VERSION 5.8 ;
BUSBITCHARS "[]" ;
DIVIDERCHAR "/" ;
UNITS
    DATABASE MICRONS 1000 ;
END UNITS

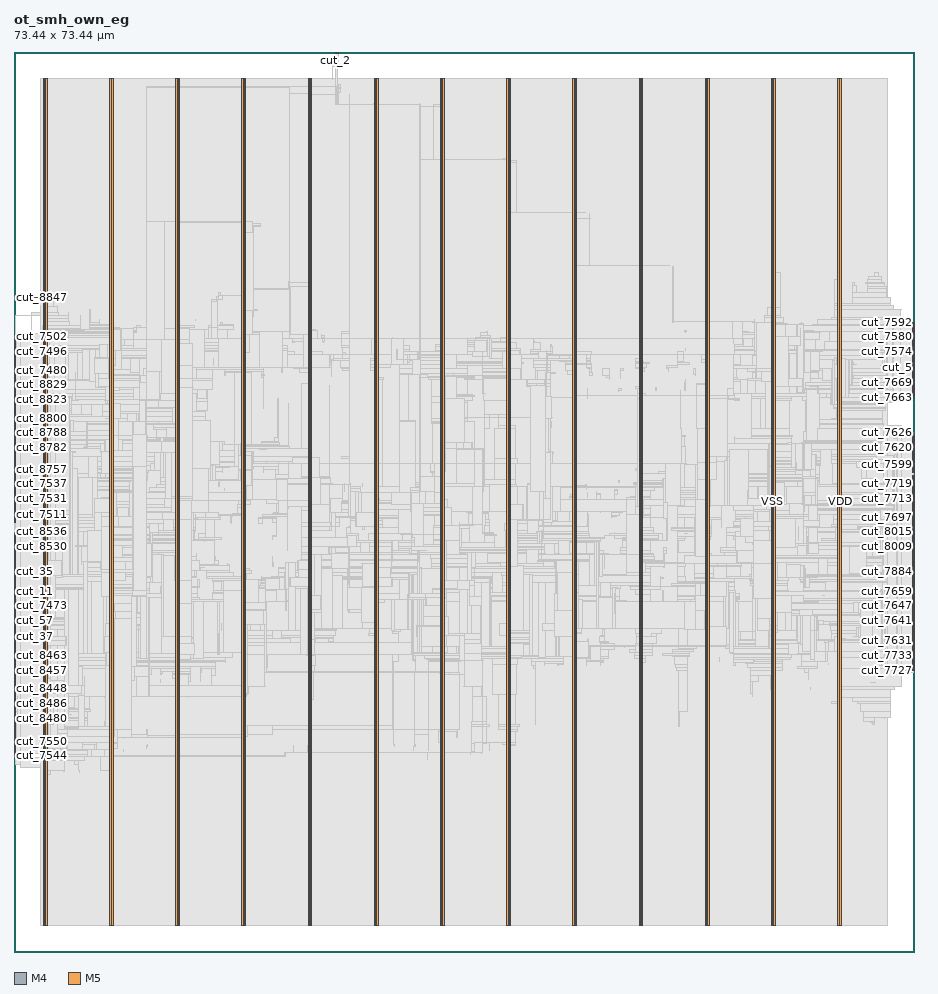
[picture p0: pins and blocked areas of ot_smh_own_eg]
MACRO ot_smh_own_eg
  FOREIGN ot_smh_own_eg 0 0 ;
  CLASS BLOCK ;
  SIZE 73.44 BY 73.44 ;
  PIN cut_10
    DIRECTION INPUT ;
    USE SIGNAL ;
    PORT
      LAYER M4 ;
        RECT  0 28.656 0.084 28.68 ;
    END
  END cut_10
  PIN cut_11
    DIRECTION INPUT ;
    USE SIGNAL ;
    PORT
      LAYER M4 ;
        RECT  0 28.752 0.084 28.776 ;
    END
  END cut_11
  PIN cut_12
    DIRECTION INPUT ;
    USE SIGNAL ;
    PORT
      LAYER M4 ;
        RECT  0 28.848 0.084 28.872 ;
    END
  END cut_12
  PIN cut_13
    DIRECTION INPUT ;
    USE SIGNAL ;
    PORT
      LAYER M4 ;
        RECT  0 28.944 0.084 28.968 ;
    END
  END cut_13
  PIN cut_14
    DIRECTION INPUT ;
    USE SIGNAL ;
    PORT
      LAYER M4 ;
        RECT  0 29.04 0.084 29.064 ;
    END
  END cut_14
  PIN cut_15
    DIRECTION INPUT ;
    USE SIGNAL ;
    PORT
      LAYER M4 ;
        RECT  0 29.136 0.084 29.16 ;
    END
  END cut_15
  PIN cut_16
    DIRECTION INPUT ;
    USE SIGNAL ;
    PORT
      LAYER M4 ;
        RECT  0 29.232 0.084 29.256 ;
    END
  END cut_16
  PIN cut_17
    DIRECTION INPUT ;
    USE SIGNAL ;
    PORT
      LAYER M4 ;
        RECT  0 29.328 0.084 29.352 ;
    END
  END cut_17
  PIN cut_18
    DIRECTION INPUT ;
    USE SIGNAL ;
    PORT
      LAYER M4 ;
        RECT  0 29.424 0.084 29.448 ;
    END
  END cut_18
  PIN cut_19
    DIRECTION INPUT ;
    USE SIGNAL ;
    PORT
      LAYER M4 ;
        RECT  0 29.52 0.084 29.544 ;
    END
  END cut_19
  PIN cut_2
    DIRECTION INPUT ;
    USE SIGNAL ;
    PORT
      LAYER M5 ;
        RECT  26.256 73.356 26.28 73.44 ;
    END
  END cut_2
  PIN cut_20
    DIRECTION INPUT ;
    USE SIGNAL ;
    PORT
      LAYER M4 ;
        RECT  0 29.616 0.084 29.64 ;
    END
  END cut_20
  PIN cut_21
    DIRECTION INPUT ;
    USE SIGNAL ;
    PORT
      LAYER M4 ;
        RECT  0 29.712 0.084 29.736 ;
    END
  END cut_21
  PIN cut_22
    DIRECTION INPUT ;
    USE SIGNAL ;
    PORT
      LAYER M4 ;
        RECT  0 29.808 0.084 29.832 ;
    END
  END cut_22
  PIN cut_23
    DIRECTION INPUT ;
    USE SIGNAL ;
    PORT
      LAYER M4 ;
        RECT  0 29.904 0.084 29.928 ;
    END
  END cut_23
  PIN cut_24
    DIRECTION INPUT ;
    USE SIGNAL ;
    PORT
      LAYER M4 ;
        RECT  0 30 0.084 30.024 ;
    END
  END cut_24
  PIN cut_25
    DIRECTION INPUT ;
    USE SIGNAL ;
    PORT
      LAYER M4 ;
        RECT  0 30.096 0.084 30.12 ;
    END
  END cut_25
  PIN cut_26
    DIRECTION INPUT ;
    USE SIGNAL ;
    PORT
      LAYER M4 ;
        RECT  0 30.192 0.084 30.216 ;
    END
  END cut_26
  PIN cut_27
    DIRECTION INPUT ;
    USE SIGNAL ;
    PORT
      LAYER M4 ;
        RECT  0 30.288 0.084 30.312 ;
    END
  END cut_27
  PIN cut_28
    DIRECTION INPUT ;
    USE SIGNAL ;
    PORT
      LAYER M4 ;
        RECT  0 30.384 0.084 30.408 ;
    END
  END cut_28
  PIN cut_29
    DIRECTION INPUT ;
    USE SIGNAL ;
    PORT
      LAYER M4 ;
        RECT  0 30.48 0.084 30.504 ;
    END
  END cut_29
  PIN cut_3
    DIRECTION INPUT ;
    USE SIGNAL ;
    PORT
      LAYER M5 ;
        RECT  26.352 73.356 26.376 73.44 ;
    END
  END cut_3
  PIN cut_30
    DIRECTION INPUT ;
    USE SIGNAL ;
    PORT
      LAYER M4 ;
        RECT  0 30.576 0.084 30.6 ;
    END
  END cut_30
  PIN cut_31
    DIRECTION INPUT ;
    USE SIGNAL ;
    PORT
      LAYER M4 ;
        RECT  0 30.672 0.084 30.696 ;
    END
  END cut_31
  PIN cut_32
    DIRECTION INPUT ;
    USE SIGNAL ;
    PORT
      LAYER M4 ;
        RECT  0 30.768 0.084 30.792 ;
    END
  END cut_32
  PIN cut_33
    DIRECTION INPUT ;
    USE SIGNAL ;
    PORT
      LAYER M4 ;
        RECT  0 30.864 0.084 30.888 ;
    END
  END cut_33
  PIN cut_34
    DIRECTION INPUT ;
    USE SIGNAL ;
    PORT
      LAYER M4 ;
        RECT  0 30.96 0.084 30.984 ;
    END
  END cut_34
  PIN cut_35
    DIRECTION INPUT ;
    USE SIGNAL ;
    PORT
      LAYER M4 ;
        RECT  0 31.056 0.084 31.08 ;
    END
  END cut_35
  PIN cut_36
    DIRECTION INPUT ;
    USE SIGNAL ;
    PORT
      LAYER M4 ;
        RECT  0 31.152 0.084 31.176 ;
    END
  END cut_36
  PIN cut_37
    DIRECTION INPUT ;
    USE SIGNAL ;
    PORT
      LAYER M4 ;
        RECT  0 25.104 0.084 25.128 ;
    END
  END cut_37
  PIN cut_38
    DIRECTION INPUT ;
    USE SIGNAL ;
    PORT
      LAYER M4 ;
        RECT  0 25.2 0.084 25.224 ;
    END
  END cut_38
  PIN cut_39
    DIRECTION INPUT ;
    USE SIGNAL ;
    PORT
      LAYER M4 ;
        RECT  0 25.296 0.084 25.32 ;
    END
  END cut_39
  PIN cut_4
    DIRECTION INPUT ;
    USE SIGNAL ;
    PORT
      LAYER M4 ;
        RECT  0 28.176 0.084 28.2 ;
    END
  END cut_4
  PIN cut_40
    DIRECTION INPUT ;
    USE SIGNAL ;
    PORT
      LAYER M4 ;
        RECT  0 25.392 0.084 25.416 ;
    END
  END cut_40
  PIN cut_41
    DIRECTION INPUT ;
    USE SIGNAL ;
    PORT
      LAYER M4 ;
        RECT  0 25.488 0.084 25.512 ;
    END
  END cut_41
  PIN cut_42
    DIRECTION INPUT ;
    USE SIGNAL ;
    PORT
      LAYER M4 ;
        RECT  0 25.584 0.084 25.608 ;
    END
  END cut_42
  PIN cut_43
    DIRECTION INPUT ;
    USE SIGNAL ;
    PORT
      LAYER M4 ;
        RECT  0 25.68 0.084 25.704 ;
    END
  END cut_43
  PIN cut_44
    DIRECTION INPUT ;
    USE SIGNAL ;
    PORT
      LAYER M4 ;
        RECT  0 25.776 0.084 25.8 ;
    END
  END cut_44
  PIN cut_45
    DIRECTION INPUT ;
    USE SIGNAL ;
    PORT
      LAYER M4 ;
        RECT  0 25.872 0.084 25.896 ;
    END
  END cut_45
  PIN cut_46
    DIRECTION INPUT ;
    USE SIGNAL ;
    PORT
      LAYER M4 ;
        RECT  0 25.968 0.084 25.992 ;
    END
  END cut_46
  PIN cut_47
    DIRECTION INPUT ;
    USE SIGNAL ;
    PORT
      LAYER M4 ;
        RECT  0 26.064 0.084 26.088 ;
    END
  END cut_47
  PIN cut_48
    DIRECTION INPUT ;
    USE SIGNAL ;
    PORT
      LAYER M4 ;
        RECT  0 26.16 0.084 26.184 ;
    END
  END cut_48
  PIN cut_49
    DIRECTION INPUT ;
    USE SIGNAL ;
    PORT
      LAYER M4 ;
        RECT  0 26.256 0.084 26.28 ;
    END
  END cut_49
  PIN cut_5
    DIRECTION OUTPUT ;
    USE SIGNAL ;
    PORT
      LAYER M4 ;
        RECT  73.356 48.336 73.44 48.36 ;
    END
  END cut_5
  PIN cut_50
    DIRECTION INPUT ;
    USE SIGNAL ;
    PORT
      LAYER M4 ;
        RECT  0 26.352 0.084 26.376 ;
    END
  END cut_50
  PIN cut_51
    DIRECTION INPUT ;
    USE SIGNAL ;
    PORT
      LAYER M4 ;
        RECT  0 26.448 0.084 26.472 ;
    END
  END cut_51
  PIN cut_52
    DIRECTION INPUT ;
    USE SIGNAL ;
    PORT
      LAYER M4 ;
        RECT  0 26.544 0.084 26.568 ;
    END
  END cut_52
  PIN cut_53
    DIRECTION INPUT ;
    USE SIGNAL ;
    PORT
      LAYER M4 ;
        RECT  0 26.64 0.084 26.664 ;
    END
  END cut_53
  PIN cut_54
    DIRECTION INPUT ;
    USE SIGNAL ;
    PORT
      LAYER M4 ;
        RECT  0 26.736 0.084 26.76 ;
    END
  END cut_54
  PIN cut_55
    DIRECTION INPUT ;
    USE SIGNAL ;
    PORT
      LAYER M4 ;
        RECT  0 26.832 0.084 26.856 ;
    END
  END cut_55
  PIN cut_56
    DIRECTION INPUT ;
    USE SIGNAL ;
    PORT
      LAYER M4 ;
        RECT  0 26.928 0.084 26.952 ;
    END
  END cut_56
  PIN cut_57
    DIRECTION INPUT ;
    USE SIGNAL ;
    PORT
      LAYER M4 ;
        RECT  0 27.024 0.084 27.048 ;
    END
  END cut_57
  PIN cut_6
    DIRECTION INPUT ;
    USE SIGNAL ;
    PORT
      LAYER M4 ;
        RECT  0 28.272 0.084 28.296 ;
    END
  END cut_6
  PIN cut_7
    DIRECTION INPUT ;
    USE SIGNAL ;
    PORT
      LAYER M4 ;
        RECT  0 28.368 0.084 28.392 ;
    END
  END cut_7
  PIN cut_7468
    DIRECTION INPUT ;
    USE SIGNAL ;
    PORT
      LAYER M4 ;
        RECT  0 27.12 0.084 27.144 ;
    END
  END cut_7468
  PIN cut_7469
    DIRECTION INPUT ;
    USE SIGNAL ;
    PORT
      LAYER M4 ;
        RECT  0 27.216 0.084 27.24 ;
    END
  END cut_7469
  PIN cut_7470
    DIRECTION INPUT ;
    USE SIGNAL ;
    PORT
      LAYER M4 ;
        RECT  0 27.312 0.084 27.336 ;
    END
  END cut_7470
  PIN cut_7471
    DIRECTION INPUT ;
    USE SIGNAL ;
    PORT
      LAYER M4 ;
        RECT  0 27.408 0.084 27.432 ;
    END
  END cut_7471
  PIN cut_7472
    DIRECTION INPUT ;
    USE SIGNAL ;
    PORT
      LAYER M4 ;
        RECT  0 27.504 0.084 27.528 ;
    END
  END cut_7472
  PIN cut_7473
    DIRECTION INPUT ;
    USE SIGNAL ;
    PORT
      LAYER M4 ;
        RECT  0 27.6 0.084 27.624 ;
    END
  END cut_7473
  PIN cut_7474
    DIRECTION INPUT ;
    USE SIGNAL ;
    PORT
      LAYER M4 ;
        RECT  0 27.696 0.084 27.72 ;
    END
  END cut_7474
  PIN cut_7475
    DIRECTION INPUT ;
    USE SIGNAL ;
    PORT
      LAYER M4 ;
        RECT  0 27.792 0.084 27.816 ;
    END
  END cut_7475
  PIN cut_7476
    DIRECTION INPUT ;
    USE SIGNAL ;
    PORT
      LAYER M4 ;
        RECT  0 27.888 0.084 27.912 ;
    END
  END cut_7476
  PIN cut_7477
    DIRECTION INPUT ;
    USE SIGNAL ;
    PORT
      LAYER M4 ;
        RECT  0 27.984 0.084 28.008 ;
    END
  END cut_7477
  PIN cut_7478
    DIRECTION INPUT ;
    USE SIGNAL ;
    PORT
      LAYER M4 ;
        RECT  0 28.08 0.084 28.104 ;
    END
  END cut_7478
  PIN cut_7479
    DIRECTION INPUT ;
    USE SIGNAL ;
    PORT
      LAYER M4 ;
        RECT  0 47.376 0.084 47.4 ;
    END
  END cut_7479
  PIN cut_7480
    DIRECTION INPUT ;
    USE SIGNAL ;
    PORT
      LAYER M4 ;
        RECT  0 47.472 0.084 47.496 ;
    END
  END cut_7480
  PIN cut_7481
    DIRECTION INPUT ;
    USE SIGNAL ;
    PORT
      LAYER M4 ;
        RECT  0 47.568 0.084 47.592 ;
    END
  END cut_7481
  PIN cut_7482
    DIRECTION INPUT ;
    USE SIGNAL ;
    PORT
      LAYER M4 ;
        RECT  0 47.664 0.084 47.688 ;
    END
  END cut_7482
  PIN cut_7483
    DIRECTION INPUT ;
    USE SIGNAL ;
    PORT
      LAYER M4 ;
        RECT  0 47.76 0.084 47.784 ;
    END
  END cut_7483
  PIN cut_7484
    DIRECTION INPUT ;
    USE SIGNAL ;
    PORT
      LAYER M4 ;
        RECT  0 47.856 0.084 47.88 ;
    END
  END cut_7484
  PIN cut_7485
    DIRECTION INPUT ;
    USE SIGNAL ;
    PORT
      LAYER M4 ;
        RECT  0 47.952 0.084 47.976 ;
    END
  END cut_7485
  PIN cut_7486
    DIRECTION INPUT ;
    USE SIGNAL ;
    PORT
      LAYER M4 ;
        RECT  0 48.048 0.084 48.072 ;
    END
  END cut_7486
  PIN cut_7487
    DIRECTION INPUT ;
    USE SIGNAL ;
    PORT
      LAYER M4 ;
        RECT  0 48.144 0.084 48.168 ;
    END
  END cut_7487
  PIN cut_7488
    DIRECTION INPUT ;
    USE SIGNAL ;
    PORT
      LAYER M4 ;
        RECT  0 48.24 0.084 48.264 ;
    END
  END cut_7488
  PIN cut_7489
    DIRECTION INPUT ;
    USE SIGNAL ;
    PORT
      LAYER M4 ;
        RECT  0 48.336 0.084 48.36 ;
    END
  END cut_7489
  PIN cut_7490
    DIRECTION INPUT ;
    USE SIGNAL ;
    PORT
      LAYER M4 ;
        RECT  0 48.432 0.084 48.456 ;
    END
  END cut_7490
  PIN cut_7491
    DIRECTION INPUT ;
    USE SIGNAL ;
    PORT
      LAYER M4 ;
        RECT  0 48.528 0.084 48.552 ;
    END
  END cut_7491
  PIN cut_7492
    DIRECTION INPUT ;
    USE SIGNAL ;
    PORT
      LAYER M4 ;
        RECT  0 48.624 0.084 48.648 ;
    END
  END cut_7492
  PIN cut_7493
    DIRECTION INPUT ;
    USE SIGNAL ;
    PORT
      LAYER M4 ;
        RECT  0 48.72 0.084 48.744 ;
    END
  END cut_7493
  PIN cut_7494
    DIRECTION INPUT ;
    USE SIGNAL ;
    PORT
      LAYER M4 ;
        RECT  0 48.816 0.084 48.84 ;
    END
  END cut_7494
  PIN cut_7495
    DIRECTION INPUT ;
    USE SIGNAL ;
    PORT
      LAYER M4 ;
        RECT  0 48.912 0.084 48.936 ;
    END
  END cut_7495
  PIN cut_7496
    DIRECTION INPUT ;
    USE SIGNAL ;
    PORT
      LAYER M4 ;
        RECT  0 49.008 0.084 49.032 ;
    END
  END cut_7496
  PIN cut_7497
    DIRECTION INPUT ;
    USE SIGNAL ;
    PORT
      LAYER M4 ;
        RECT  0 49.104 0.084 49.128 ;
    END
  END cut_7497
  PIN cut_7498
    DIRECTION INPUT ;
    USE SIGNAL ;
    PORT
      LAYER M4 ;
        RECT  0 49.2 0.084 49.224 ;
    END
  END cut_7498
  PIN cut_7499
    DIRECTION INPUT ;
    USE SIGNAL ;
    PORT
      LAYER M4 ;
        RECT  0 49.296 0.084 49.32 ;
    END
  END cut_7499
  PIN cut_7500
    DIRECTION INPUT ;
    USE SIGNAL ;
    PORT
      LAYER M4 ;
        RECT  0 49.392 0.084 49.416 ;
    END
  END cut_7500
  PIN cut_7501
    DIRECTION INPUT ;
    USE SIGNAL ;
    PORT
      LAYER M4 ;
        RECT  0 49.488 0.084 49.512 ;
    END
  END cut_7501
  PIN cut_7502
    DIRECTION INPUT ;
    USE SIGNAL ;
    PORT
      LAYER M4 ;
        RECT  0 49.584 0.084 49.608 ;
    END
  END cut_7502
  PIN cut_7503
    DIRECTION INPUT ;
    USE SIGNAL ;
    PORT
      LAYER M4 ;
        RECT  0 49.68 0.084 49.704 ;
    END
  END cut_7503
  PIN cut_7504
    DIRECTION INPUT ;
    USE SIGNAL ;
    PORT
      LAYER M4 ;
        RECT  0 49.776 0.084 49.8 ;
    END
  END cut_7504
  PIN cut_7505
    DIRECTION INPUT ;
    USE SIGNAL ;
    PORT
      LAYER M4 ;
        RECT  0 49.872 0.084 49.896 ;
    END
  END cut_7505
  PIN cut_7506
    DIRECTION INPUT ;
    USE SIGNAL ;
    PORT
      LAYER M4 ;
        RECT  0 49.968 0.084 49.992 ;
    END
  END cut_7506
  PIN cut_7507
    DIRECTION INPUT ;
    USE SIGNAL ;
    PORT
      LAYER M4 ;
        RECT  0 50.064 0.084 50.088 ;
    END
  END cut_7507
  PIN cut_7508
    DIRECTION INPUT ;
    USE SIGNAL ;
    PORT
      LAYER M4 ;
        RECT  0 50.16 0.084 50.184 ;
    END
  END cut_7508
  PIN cut_7509
    DIRECTION INPUT ;
    USE SIGNAL ;
    PORT
      LAYER M4 ;
        RECT  0 50.256 0.084 50.28 ;
    END
  END cut_7509
  PIN cut_7510
    DIRECTION INPUT ;
    USE SIGNAL ;
    PORT
      LAYER M4 ;
        RECT  0 50.352 0.084 50.376 ;
    END
  END cut_7510
  PIN cut_7511
    DIRECTION INPUT ;
    USE SIGNAL ;
    PORT
      LAYER M4 ;
        RECT  0 35.088 0.084 35.112 ;
    END
  END cut_7511
  PIN cut_7512
    DIRECTION INPUT ;
    USE SIGNAL ;
    PORT
      LAYER M4 ;
        RECT  0 35.184 0.084 35.208 ;
    END
  END cut_7512
  PIN cut_7513
    DIRECTION INPUT ;
    USE SIGNAL ;
    PORT
      LAYER M4 ;
        RECT  0 35.28 0.084 35.304 ;
    END
  END cut_7513
  PIN cut_7514
    DIRECTION INPUT ;
    USE SIGNAL ;
    PORT
      LAYER M4 ;
        RECT  0 35.376 0.084 35.4 ;
    END
  END cut_7514
  PIN cut_7515
    DIRECTION INPUT ;
    USE SIGNAL ;
    PORT
      LAYER M4 ;
        RECT  0 35.472 0.084 35.496 ;
    END
  END cut_7515
  PIN cut_7516
    DIRECTION INPUT ;
    USE SIGNAL ;
    PORT
      LAYER M4 ;
        RECT  0 35.568 0.084 35.592 ;
    END
  END cut_7516
  PIN cut_7517
    DIRECTION INPUT ;
    USE SIGNAL ;
    PORT
      LAYER M4 ;
        RECT  0 35.664 0.084 35.688 ;
    END
  END cut_7517
  PIN cut_7518
    DIRECTION INPUT ;
    USE SIGNAL ;
    PORT
      LAYER M4 ;
        RECT  0 35.76 0.084 35.784 ;
    END
  END cut_7518
  PIN cut_7519
    DIRECTION INPUT ;
    USE SIGNAL ;
    PORT
      LAYER M4 ;
        RECT  0 35.856 0.084 35.88 ;
    END
  END cut_7519
  PIN cut_7520
    DIRECTION INPUT ;
    USE SIGNAL ;
    PORT
      LAYER M4 ;
        RECT  0 35.952 0.084 35.976 ;
    END
  END cut_7520
  PIN cut_7521
    DIRECTION INPUT ;
    USE SIGNAL ;
    PORT
      LAYER M4 ;
        RECT  0 36.048 0.084 36.072 ;
    END
  END cut_7521
  PIN cut_7522
    DIRECTION INPUT ;
    USE SIGNAL ;
    PORT
      LAYER M4 ;
        RECT  0 36.144 0.084 36.168 ;
    END
  END cut_7522
  PIN cut_7523
    DIRECTION INPUT ;
    USE SIGNAL ;
    PORT
      LAYER M4 ;
        RECT  0 36.24 0.084 36.264 ;
    END
  END cut_7523
  PIN cut_7524
    DIRECTION INPUT ;
    USE SIGNAL ;
    PORT
      LAYER M4 ;
        RECT  0 36.336 0.084 36.36 ;
    END
  END cut_7524
  PIN cut_7525
    DIRECTION INPUT ;
    USE SIGNAL ;
    PORT
      LAYER M4 ;
        RECT  0 36.432 0.084 36.456 ;
    END
  END cut_7525
  PIN cut_7526
    DIRECTION INPUT ;
    USE SIGNAL ;
    PORT
      LAYER M4 ;
        RECT  0 36.528 0.084 36.552 ;
    END
  END cut_7526
  PIN cut_7527
    DIRECTION INPUT ;
    USE SIGNAL ;
    PORT
      LAYER M4 ;
        RECT  0 36.624 0.084 36.648 ;
    END
  END cut_7527
  PIN cut_7528
    DIRECTION INPUT ;
    USE SIGNAL ;
    PORT
      LAYER M4 ;
        RECT  0 36.72 0.084 36.744 ;
    END
  END cut_7528
  PIN cut_7529
    DIRECTION INPUT ;
    USE SIGNAL ;
    PORT
      LAYER M4 ;
        RECT  0 36.816 0.084 36.84 ;
    END
  END cut_7529
  PIN cut_7530
    DIRECTION INPUT ;
    USE SIGNAL ;
    PORT
      LAYER M4 ;
        RECT  0 36.912 0.084 36.936 ;
    END
  END cut_7530
  PIN cut_7531
    DIRECTION INPUT ;
    USE SIGNAL ;
    PORT
      LAYER M4 ;
        RECT  0 37.008 0.084 37.032 ;
    END
  END cut_7531
  PIN cut_7532
    DIRECTION INPUT ;
    USE SIGNAL ;
    PORT
      LAYER M4 ;
        RECT  0 37.104 0.084 37.128 ;
    END
  END cut_7532
  PIN cut_7533
    DIRECTION INPUT ;
    USE SIGNAL ;
    PORT
      LAYER M4 ;
        RECT  0 37.2 0.084 37.224 ;
    END
  END cut_7533
  PIN cut_7534
    DIRECTION INPUT ;
    USE SIGNAL ;
    PORT
      LAYER M4 ;
        RECT  0 37.296 0.084 37.32 ;
    END
  END cut_7534
  PIN cut_7535
    DIRECTION INPUT ;
    USE SIGNAL ;
    PORT
      LAYER M4 ;
        RECT  0 37.392 0.084 37.416 ;
    END
  END cut_7535
  PIN cut_7536
    DIRECTION INPUT ;
    USE SIGNAL ;
    PORT
      LAYER M4 ;
        RECT  0 37.488 0.084 37.512 ;
    END
  END cut_7536
  PIN cut_7537
    DIRECTION INPUT ;
    USE SIGNAL ;
    PORT
      LAYER M4 ;
        RECT  0 37.584 0.084 37.608 ;
    END
  END cut_7537
  PIN cut_7538
    DIRECTION INPUT ;
    USE SIGNAL ;
    PORT
      LAYER M4 ;
        RECT  0 37.68 0.084 37.704 ;
    END
  END cut_7538
  PIN cut_7539
    DIRECTION INPUT ;
    USE SIGNAL ;
    PORT
      LAYER M4 ;
        RECT  0 37.776 0.084 37.8 ;
    END
  END cut_7539
  PIN cut_7540
    DIRECTION INPUT ;
    USE SIGNAL ;
    PORT
      LAYER M4 ;
        RECT  0 37.872 0.084 37.896 ;
    END
  END cut_7540
  PIN cut_7541
    DIRECTION INPUT ;
    USE SIGNAL ;
    PORT
      LAYER M4 ;
        RECT  0 37.968 0.084 37.992 ;
    END
  END cut_7541
  PIN cut_7542
    DIRECTION INPUT ;
    USE SIGNAL ;
    PORT
      LAYER M4 ;
        RECT  0 38.064 0.084 38.088 ;
    END
  END cut_7542
  PIN cut_7543
    DIRECTION INPUT ;
    USE SIGNAL ;
    PORT
      LAYER M4 ;
        RECT  0 15.888 0.084 15.912 ;
    END
  END cut_7543
  PIN cut_7544
    DIRECTION INPUT ;
    USE SIGNAL ;
    PORT
      LAYER M4 ;
        RECT  0 15.984 0.084 16.008 ;
    END
  END cut_7544
  PIN cut_7545
    DIRECTION INPUT ;
    USE SIGNAL ;
    PORT
      LAYER M4 ;
        RECT  0 16.08 0.084 16.104 ;
    END
  END cut_7545
  PIN cut_7546
    DIRECTION INPUT ;
    USE SIGNAL ;
    PORT
      LAYER M4 ;
        RECT  0 16.176 0.084 16.2 ;
    END
  END cut_7546
  PIN cut_7547
    DIRECTION INPUT ;
    USE SIGNAL ;
    PORT
      LAYER M4 ;
        RECT  0 16.272 0.084 16.296 ;
    END
  END cut_7547
  PIN cut_7548
    DIRECTION INPUT ;
    USE SIGNAL ;
    PORT
      LAYER M4 ;
        RECT  0 16.368 0.084 16.392 ;
    END
  END cut_7548
  PIN cut_7549
    DIRECTION INPUT ;
    USE SIGNAL ;
    PORT
      LAYER M4 ;
        RECT  0 16.464 0.084 16.488 ;
    END
  END cut_7549
  PIN cut_7550
    DIRECTION INPUT ;
    USE SIGNAL ;
    PORT
      LAYER M4 ;
        RECT  0 16.56 0.084 16.584 ;
    END
  END cut_7550
  PIN cut_7551
    DIRECTION INPUT ;
    USE SIGNAL ;
    PORT
      LAYER M4 ;
        RECT  0 16.656 0.084 16.68 ;
    END
  END cut_7551
  PIN cut_7552
    DIRECTION INPUT ;
    USE SIGNAL ;
    PORT
      LAYER M4 ;
        RECT  0 16.752 0.084 16.776 ;
    END
  END cut_7552
  PIN cut_7553
    DIRECTION INPUT ;
    USE SIGNAL ;
    PORT
      LAYER M4 ;
        RECT  0 16.848 0.084 16.872 ;
    END
  END cut_7553
  PIN cut_7554
    DIRECTION INPUT ;
    USE SIGNAL ;
    PORT
      LAYER M4 ;
        RECT  0 16.944 0.084 16.968 ;
    END
  END cut_7554
  PIN cut_7555
    DIRECTION INPUT ;
    USE SIGNAL ;
    PORT
      LAYER M4 ;
        RECT  0 17.04 0.084 17.064 ;
    END
  END cut_7555
  PIN cut_7556
    DIRECTION INPUT ;
    USE SIGNAL ;
    PORT
      LAYER M4 ;
        RECT  0 17.136 0.084 17.16 ;
    END
  END cut_7556
  PIN cut_7557
    DIRECTION INPUT ;
    USE SIGNAL ;
    PORT
      LAYER M4 ;
        RECT  0 17.232 0.084 17.256 ;
    END
  END cut_7557
  PIN cut_7558
    DIRECTION INPUT ;
    USE SIGNAL ;
    PORT
      LAYER M4 ;
        RECT  0 17.328 0.084 17.352 ;
    END
  END cut_7558
  PIN cut_7559
    DIRECTION INPUT ;
    USE SIGNAL ;
    PORT
      LAYER M4 ;
        RECT  0 17.424 0.084 17.448 ;
    END
  END cut_7559
  PIN cut_7560
    DIRECTION INPUT ;
    USE SIGNAL ;
    PORT
      LAYER M4 ;
        RECT  0 17.52 0.084 17.544 ;
    END
  END cut_7560
  PIN cut_7561
    DIRECTION INPUT ;
    USE SIGNAL ;
    PORT
      LAYER M4 ;
        RECT  0 17.616 0.084 17.64 ;
    END
  END cut_7561
  PIN cut_7562
    DIRECTION INPUT ;
    USE SIGNAL ;
    PORT
      LAYER M4 ;
        RECT  0 17.712 0.084 17.736 ;
    END
  END cut_7562
  PIN cut_7563
    DIRECTION INPUT ;
    USE SIGNAL ;
    PORT
      LAYER M4 ;
        RECT  0 17.808 0.084 17.832 ;
    END
  END cut_7563
  PIN cut_7564
    DIRECTION INPUT ;
    USE SIGNAL ;
    PORT
      LAYER M4 ;
        RECT  0 17.904 0.084 17.928 ;
    END
  END cut_7564
  PIN cut_7565
    DIRECTION INPUT ;
    USE SIGNAL ;
    PORT
      LAYER M4 ;
        RECT  0 18 0.084 18.024 ;
    END
  END cut_7565
  PIN cut_7566
    DIRECTION INPUT ;
    USE SIGNAL ;
    PORT
      LAYER M4 ;
        RECT  0 18.096 0.084 18.12 ;
    END
  END cut_7566
  PIN cut_7567
    DIRECTION INPUT ;
    USE SIGNAL ;
    PORT
      LAYER M4 ;
        RECT  0 18.192 0.084 18.216 ;
    END
  END cut_7567
  PIN cut_7568
    DIRECTION OUTPUT ;
    USE SIGNAL ;
    PORT
      LAYER M4 ;
        RECT  73.356 48.432 73.44 48.456 ;
    END
  END cut_7568
  PIN cut_7569
    DIRECTION OUTPUT ;
    USE SIGNAL ;
    PORT
      LAYER M4 ;
        RECT  73.356 48.528 73.44 48.552 ;
    END
  END cut_7569
  PIN cut_7570
    DIRECTION OUTPUT ;
    USE SIGNAL ;
    PORT
      LAYER M4 ;
        RECT  73.356 48.624 73.44 48.648 ;
    END
  END cut_7570
  PIN cut_7571
    DIRECTION OUTPUT ;
    USE SIGNAL ;
    PORT
      LAYER M4 ;
        RECT  73.356 48.72 73.44 48.744 ;
    END
  END cut_7571
  PIN cut_7572
    DIRECTION OUTPUT ;
    USE SIGNAL ;
    PORT
      LAYER M4 ;
        RECT  73.356 48.816 73.44 48.84 ;
    END
  END cut_7572
  PIN cut_7573
    DIRECTION OUTPUT ;
    USE SIGNAL ;
    PORT
      LAYER M4 ;
        RECT  73.356 48.912 73.44 48.936 ;
    END
  END cut_7573
  PIN cut_7574
    DIRECTION OUTPUT ;
    USE SIGNAL ;
    PORT
      LAYER M4 ;
        RECT  73.356 49.008 73.44 49.032 ;
    END
  END cut_7574
  PIN cut_7575
    DIRECTION OUTPUT ;
    USE SIGNAL ;
    PORT
      LAYER M4 ;
        RECT  73.356 49.104 73.44 49.128 ;
    END
  END cut_7575
  PIN cut_7576
    DIRECTION OUTPUT ;
    USE SIGNAL ;
    PORT
      LAYER M4 ;
        RECT  73.356 49.2 73.44 49.224 ;
    END
  END cut_7576
  PIN cut_7577
    DIRECTION OUTPUT ;
    USE SIGNAL ;
    PORT
      LAYER M4 ;
        RECT  73.356 49.296 73.44 49.32 ;
    END
  END cut_7577
  PIN cut_7578
    DIRECTION OUTPUT ;
    USE SIGNAL ;
    PORT
      LAYER M4 ;
        RECT  73.356 49.392 73.44 49.416 ;
    END
  END cut_7578
  PIN cut_7579
    DIRECTION OUTPUT ;
    USE SIGNAL ;
    PORT
      LAYER M4 ;
        RECT  73.356 49.488 73.44 49.512 ;
    END
  END cut_7579
  PIN cut_7580
    DIRECTION OUTPUT ;
    USE SIGNAL ;
    PORT
      LAYER M4 ;
        RECT  73.356 49.584 73.44 49.608 ;
    END
  END cut_7580
  PIN cut_7581
    DIRECTION OUTPUT ;
    USE SIGNAL ;
    PORT
      LAYER M4 ;
        RECT  73.356 49.68 73.44 49.704 ;
    END
  END cut_7581
  PIN cut_7582
    DIRECTION OUTPUT ;
    USE SIGNAL ;
    PORT
      LAYER M4 ;
        RECT  73.356 49.776 73.44 49.8 ;
    END
  END cut_7582
  PIN cut_7583
    DIRECTION OUTPUT ;
    USE SIGNAL ;
    PORT
      LAYER M4 ;
        RECT  73.356 49.872 73.44 49.896 ;
    END
  END cut_7583
  PIN cut_7584
    DIRECTION OUTPUT ;
    USE SIGNAL ;
    PORT
      LAYER M4 ;
        RECT  73.356 49.968 73.44 49.992 ;
    END
  END cut_7584
  PIN cut_7585
    DIRECTION OUTPUT ;
    USE SIGNAL ;
    PORT
      LAYER M4 ;
        RECT  73.356 50.064 73.44 50.088 ;
    END
  END cut_7585
  PIN cut_7586
    DIRECTION OUTPUT ;
    USE SIGNAL ;
    PORT
      LAYER M4 ;
        RECT  73.356 50.16 73.44 50.184 ;
    END
  END cut_7586
  PIN cut_7587
    DIRECTION OUTPUT ;
    USE SIGNAL ;
    PORT
      LAYER M4 ;
        RECT  73.356 50.256 73.44 50.28 ;
    END
  END cut_7587
  PIN cut_7588
    DIRECTION OUTPUT ;
    USE SIGNAL ;
    PORT
      LAYER M4 ;
        RECT  73.356 50.352 73.44 50.376 ;
    END
  END cut_7588
  PIN cut_7589
    DIRECTION OUTPUT ;
    USE SIGNAL ;
    PORT
      LAYER M4 ;
        RECT  73.356 50.448 73.44 50.472 ;
    END
  END cut_7589
  PIN cut_7590
    DIRECTION OUTPUT ;
    USE SIGNAL ;
    PORT
      LAYER M4 ;
        RECT  73.356 50.544 73.44 50.568 ;
    END
  END cut_7590
  PIN cut_7591
    DIRECTION OUTPUT ;
    USE SIGNAL ;
    PORT
      LAYER M4 ;
        RECT  73.356 50.64 73.44 50.664 ;
    END
  END cut_7591
  PIN cut_7592
    DIRECTION OUTPUT ;
    USE SIGNAL ;
    PORT
      LAYER M4 ;
        RECT  73.356 50.736 73.44 50.76 ;
    END
  END cut_7592
  PIN cut_7593
    DIRECTION OUTPUT ;
    USE SIGNAL ;
    PORT
      LAYER M4 ;
        RECT  73.356 50.832 73.44 50.856 ;
    END
  END cut_7593
  PIN cut_7594
    DIRECTION OUTPUT ;
    USE SIGNAL ;
    PORT
      LAYER M4 ;
        RECT  73.356 50.928 73.44 50.952 ;
    END
  END cut_7594
  PIN cut_7595
    DIRECTION OUTPUT ;
    USE SIGNAL ;
    PORT
      LAYER M4 ;
        RECT  73.356 51.024 73.44 51.048 ;
    END
  END cut_7595
  PIN cut_7596
    DIRECTION OUTPUT ;
    USE SIGNAL ;
    PORT
      LAYER M4 ;
        RECT  73.356 51.12 73.44 51.144 ;
    END
  END cut_7596
  PIN cut_7597
    DIRECTION OUTPUT ;
    USE SIGNAL ;
    PORT
      LAYER M4 ;
        RECT  73.356 51.216 73.44 51.24 ;
    END
  END cut_7597
  PIN cut_7598
    DIRECTION OUTPUT ;
    USE SIGNAL ;
    PORT
      LAYER M4 ;
        RECT  73.356 51.312 73.44 51.336 ;
    END
  END cut_7598
  PIN cut_7599
    DIRECTION OUTPUT ;
    USE SIGNAL ;
    PORT
      LAYER M4 ;
        RECT  73.356 39.12 73.44 39.144 ;
    END
  END cut_7599
  PIN cut_7600
    DIRECTION OUTPUT ;
    USE SIGNAL ;
    PORT
      LAYER M4 ;
        RECT  73.356 39.216 73.44 39.24 ;
    END
  END cut_7600
  PIN cut_7601
    DIRECTION OUTPUT ;
    USE SIGNAL ;
    PORT
      LAYER M4 ;
        RECT  73.356 39.312 73.44 39.336 ;
    END
  END cut_7601
  PIN cut_7602
    DIRECTION OUTPUT ;
    USE SIGNAL ;
    PORT
      LAYER M4 ;
        RECT  73.356 39.408 73.44 39.432 ;
    END
  END cut_7602
  PIN cut_7603
    DIRECTION OUTPUT ;
    USE SIGNAL ;
    PORT
      LAYER M4 ;
        RECT  73.356 39.504 73.44 39.528 ;
    END
  END cut_7603
  PIN cut_7604
    DIRECTION OUTPUT ;
    USE SIGNAL ;
    PORT
      LAYER M4 ;
        RECT  73.356 39.6 73.44 39.624 ;
    END
  END cut_7604
  PIN cut_7605
    DIRECTION OUTPUT ;
    USE SIGNAL ;
    PORT
      LAYER M4 ;
        RECT  73.356 39.696 73.44 39.72 ;
    END
  END cut_7605
  PIN cut_7606
    DIRECTION OUTPUT ;
    USE SIGNAL ;
    PORT
      LAYER M4 ;
        RECT  73.356 39.792 73.44 39.816 ;
    END
  END cut_7606
  PIN cut_7607
    DIRECTION OUTPUT ;
    USE SIGNAL ;
    PORT
      LAYER M4 ;
        RECT  73.356 39.888 73.44 39.912 ;
    END
  END cut_7607
  PIN cut_7608
    DIRECTION OUTPUT ;
    USE SIGNAL ;
    PORT
      LAYER M4 ;
        RECT  73.356 39.984 73.44 40.008 ;
    END
  END cut_7608
  PIN cut_7609
    DIRECTION OUTPUT ;
    USE SIGNAL ;
    PORT
      LAYER M4 ;
        RECT  73.356 40.08 73.44 40.104 ;
    END
  END cut_7609
  PIN cut_7610
    DIRECTION OUTPUT ;
    USE SIGNAL ;
    PORT
      LAYER M4 ;
        RECT  73.356 40.176 73.44 40.2 ;
    END
  END cut_7610
  PIN cut_7611
    DIRECTION OUTPUT ;
    USE SIGNAL ;
    PORT
      LAYER M4 ;
        RECT  73.356 40.272 73.44 40.296 ;
    END
  END cut_7611
  PIN cut_7612
    DIRECTION OUTPUT ;
    USE SIGNAL ;
    PORT
      LAYER M4 ;
        RECT  73.356 40.368 73.44 40.392 ;
    END
  END cut_7612
  PIN cut_7613
    DIRECTION OUTPUT ;
    USE SIGNAL ;
    PORT
      LAYER M4 ;
        RECT  73.356 40.464 73.44 40.488 ;
    END
  END cut_7613
  PIN cut_7614
    DIRECTION OUTPUT ;
    USE SIGNAL ;
    PORT
      LAYER M4 ;
        RECT  73.356 40.56 73.44 40.584 ;
    END
  END cut_7614
  PIN cut_7615
    DIRECTION OUTPUT ;
    USE SIGNAL ;
    PORT
      LAYER M4 ;
        RECT  73.356 40.656 73.44 40.68 ;
    END
  END cut_7615
  PIN cut_7616
    DIRECTION OUTPUT ;
    USE SIGNAL ;
    PORT
      LAYER M4 ;
        RECT  73.356 40.752 73.44 40.776 ;
    END
  END cut_7616
  PIN cut_7617
    DIRECTION OUTPUT ;
    USE SIGNAL ;
    PORT
      LAYER M4 ;
        RECT  73.356 40.848 73.44 40.872 ;
    END
  END cut_7617
  PIN cut_7618
    DIRECTION OUTPUT ;
    USE SIGNAL ;
    PORT
      LAYER M4 ;
        RECT  73.356 40.944 73.44 40.968 ;
    END
  END cut_7618
  PIN cut_7619
    DIRECTION OUTPUT ;
    USE SIGNAL ;
    PORT
      LAYER M4 ;
        RECT  73.356 41.04 73.44 41.064 ;
    END
  END cut_7619
  PIN cut_7620
    DIRECTION OUTPUT ;
    USE SIGNAL ;
    PORT
      LAYER M4 ;
        RECT  73.356 41.136 73.44 41.16 ;
    END
  END cut_7620
  PIN cut_7621
    DIRECTION OUTPUT ;
    USE SIGNAL ;
    PORT
      LAYER M4 ;
        RECT  73.356 41.232 73.44 41.256 ;
    END
  END cut_7621
  PIN cut_7622
    DIRECTION OUTPUT ;
    USE SIGNAL ;
    PORT
      LAYER M4 ;
        RECT  73.356 41.328 73.44 41.352 ;
    END
  END cut_7622
  PIN cut_7623
    DIRECTION OUTPUT ;
    USE SIGNAL ;
    PORT
      LAYER M4 ;
        RECT  73.356 41.424 73.44 41.448 ;
    END
  END cut_7623
  PIN cut_7624
    DIRECTION OUTPUT ;
    USE SIGNAL ;
    PORT
      LAYER M4 ;
        RECT  73.356 41.52 73.44 41.544 ;
    END
  END cut_7624
  PIN cut_7625
    DIRECTION OUTPUT ;
    USE SIGNAL ;
    PORT
      LAYER M4 ;
        RECT  73.356 41.616 73.44 41.64 ;
    END
  END cut_7625
  PIN cut_7626
    DIRECTION OUTPUT ;
    USE SIGNAL ;
    PORT
      LAYER M4 ;
        RECT  73.356 41.712 73.44 41.736 ;
    END
  END cut_7626
  PIN cut_7627
    DIRECTION OUTPUT ;
    USE SIGNAL ;
    PORT
      LAYER M4 ;
        RECT  73.356 41.808 73.44 41.832 ;
    END
  END cut_7627
  PIN cut_7628
    DIRECTION OUTPUT ;
    USE SIGNAL ;
    PORT
      LAYER M4 ;
        RECT  73.356 41.904 73.44 41.928 ;
    END
  END cut_7628
  PIN cut_7629
    DIRECTION OUTPUT ;
    USE SIGNAL ;
    PORT
      LAYER M4 ;
        RECT  73.356 42 73.44 42.024 ;
    END
  END cut_7629
  PIN cut_7630
    DIRECTION OUTPUT ;
    USE SIGNAL ;
    PORT
      LAYER M4 ;
        RECT  73.356 42.096 73.44 42.12 ;
    END
  END cut_7630
  PIN cut_7631
    DIRECTION OUTPUT ;
    USE SIGNAL ;
    PORT
      LAYER M4 ;
        RECT  73.356 26.064 73.44 26.088 ;
    END
  END cut_7631
  PIN cut_7632
    DIRECTION OUTPUT ;
    USE SIGNAL ;
    PORT
      LAYER M4 ;
        RECT  73.356 26.16 73.44 26.184 ;
    END
  END cut_7632
  PIN cut_7633
    DIRECTION OUTPUT ;
    USE SIGNAL ;
    PORT
      LAYER M4 ;
        RECT  73.356 26.256 73.44 26.28 ;
    END
  END cut_7633
  PIN cut_7634
    DIRECTION OUTPUT ;
    USE SIGNAL ;
    PORT
      LAYER M4 ;
        RECT  73.356 26.352 73.44 26.376 ;
    END
  END cut_7634
  PIN cut_7635
    DIRECTION OUTPUT ;
    USE SIGNAL ;
    PORT
      LAYER M4 ;
        RECT  73.356 26.448 73.44 26.472 ;
    END
  END cut_7635
  PIN cut_7636
    DIRECTION OUTPUT ;
    USE SIGNAL ;
    PORT
      LAYER M4 ;
        RECT  73.356 26.544 73.44 26.568 ;
    END
  END cut_7636
  PIN cut_7637
    DIRECTION OUTPUT ;
    USE SIGNAL ;
    PORT
      LAYER M4 ;
        RECT  73.356 26.64 73.44 26.664 ;
    END
  END cut_7637
  PIN cut_7638
    DIRECTION OUTPUT ;
    USE SIGNAL ;
    PORT
      LAYER M4 ;
        RECT  73.356 26.736 73.44 26.76 ;
    END
  END cut_7638
  PIN cut_7639
    DIRECTION OUTPUT ;
    USE SIGNAL ;
    PORT
      LAYER M4 ;
        RECT  73.356 26.832 73.44 26.856 ;
    END
  END cut_7639
  PIN cut_7640
    DIRECTION OUTPUT ;
    USE SIGNAL ;
    PORT
      LAYER M4 ;
        RECT  73.356 26.928 73.44 26.952 ;
    END
  END cut_7640
  PIN cut_7641
    DIRECTION OUTPUT ;
    USE SIGNAL ;
    PORT
      LAYER M4 ;
        RECT  73.356 27.024 73.44 27.048 ;
    END
  END cut_7641
  PIN cut_7642
    DIRECTION OUTPUT ;
    USE SIGNAL ;
    PORT
      LAYER M4 ;
        RECT  73.356 27.12 73.44 27.144 ;
    END
  END cut_7642
  PIN cut_7643
    DIRECTION OUTPUT ;
    USE SIGNAL ;
    PORT
      LAYER M4 ;
        RECT  73.356 27.216 73.44 27.24 ;
    END
  END cut_7643
  PIN cut_7644
    DIRECTION OUTPUT ;
    USE SIGNAL ;
    PORT
      LAYER M4 ;
        RECT  73.356 27.312 73.44 27.336 ;
    END
  END cut_7644
  PIN cut_7645
    DIRECTION OUTPUT ;
    USE SIGNAL ;
    PORT
      LAYER M4 ;
        RECT  73.356 27.408 73.44 27.432 ;
    END
  END cut_7645
  PIN cut_7646
    DIRECTION OUTPUT ;
    USE SIGNAL ;
    PORT
      LAYER M4 ;
        RECT  73.356 27.504 73.44 27.528 ;
    END
  END cut_7646
  PIN cut_7647
    DIRECTION OUTPUT ;
    USE SIGNAL ;
    PORT
      LAYER M4 ;
        RECT  73.356 27.6 73.44 27.624 ;
    END
  END cut_7647
  PIN cut_7648
    DIRECTION OUTPUT ;
    USE SIGNAL ;
    PORT
      LAYER M4 ;
        RECT  73.356 27.696 73.44 27.72 ;
    END
  END cut_7648
  PIN cut_7649
    DIRECTION OUTPUT ;
    USE SIGNAL ;
    PORT
      LAYER M4 ;
        RECT  73.356 27.792 73.44 27.816 ;
    END
  END cut_7649
  PIN cut_7650
    DIRECTION OUTPUT ;
    USE SIGNAL ;
    PORT
      LAYER M4 ;
        RECT  73.356 27.888 73.44 27.912 ;
    END
  END cut_7650
  PIN cut_7651
    DIRECTION OUTPUT ;
    USE SIGNAL ;
    PORT
      LAYER M4 ;
        RECT  73.356 27.984 73.44 28.008 ;
    END
  END cut_7651
  PIN cut_7652
    DIRECTION OUTPUT ;
    USE SIGNAL ;
    PORT
      LAYER M4 ;
        RECT  73.356 28.08 73.44 28.104 ;
    END
  END cut_7652
  PIN cut_7653
    DIRECTION OUTPUT ;
    USE SIGNAL ;
    PORT
      LAYER M4 ;
        RECT  73.356 28.176 73.44 28.2 ;
    END
  END cut_7653
  PIN cut_7654
    DIRECTION OUTPUT ;
    USE SIGNAL ;
    PORT
      LAYER M4 ;
        RECT  73.356 28.272 73.44 28.296 ;
    END
  END cut_7654
  PIN cut_7655
    DIRECTION OUTPUT ;
    USE SIGNAL ;
    PORT
      LAYER M4 ;
        RECT  73.356 28.368 73.44 28.392 ;
    END
  END cut_7655
  PIN cut_7656
    DIRECTION OUTPUT ;
    USE SIGNAL ;
    PORT
      LAYER M4 ;
        RECT  73.356 28.464 73.44 28.488 ;
    END
  END cut_7656
  PIN cut_7657
    DIRECTION OUTPUT ;
    USE SIGNAL ;
    PORT
      LAYER M4 ;
        RECT  73.356 28.56 73.44 28.584 ;
    END
  END cut_7657
  PIN cut_7658
    DIRECTION OUTPUT ;
    USE SIGNAL ;
    PORT
      LAYER M4 ;
        RECT  73.356 28.656 73.44 28.68 ;
    END
  END cut_7658
  PIN cut_7659
    DIRECTION OUTPUT ;
    USE SIGNAL ;
    PORT
      LAYER M4 ;
        RECT  73.356 28.752 73.44 28.776 ;
    END
  END cut_7659
  PIN cut_7660
    DIRECTION OUTPUT ;
    USE SIGNAL ;
    PORT
      LAYER M4 ;
        RECT  73.356 28.848 73.44 28.872 ;
    END
  END cut_7660
  PIN cut_7661
    DIRECTION OUTPUT ;
    USE SIGNAL ;
    PORT
      LAYER M4 ;
        RECT  73.356 28.944 73.44 28.968 ;
    END
  END cut_7661
  PIN cut_7662
    DIRECTION OUTPUT ;
    USE SIGNAL ;
    PORT
      LAYER M4 ;
        RECT  73.356 29.04 73.44 29.064 ;
    END
  END cut_7662
  PIN cut_7663
    DIRECTION OUTPUT ;
    USE SIGNAL ;
    PORT
      LAYER M4 ;
        RECT  73.356 45.264 73.44 45.288 ;
    END
  END cut_7663
  PIN cut_7664
    DIRECTION OUTPUT ;
    USE SIGNAL ;
    PORT
      LAYER M4 ;
        RECT  73.356 45.36 73.44 45.384 ;
    END
  END cut_7664
  PIN cut_7665
    DIRECTION OUTPUT ;
    USE SIGNAL ;
    PORT
      LAYER M4 ;
        RECT  73.356 45.456 73.44 45.48 ;
    END
  END cut_7665
  PIN cut_7666
    DIRECTION OUTPUT ;
    USE SIGNAL ;
    PORT
      LAYER M4 ;
        RECT  73.356 45.552 73.44 45.576 ;
    END
  END cut_7666
  PIN cut_7667
    DIRECTION OUTPUT ;
    USE SIGNAL ;
    PORT
      LAYER M4 ;
        RECT  73.356 45.648 73.44 45.672 ;
    END
  END cut_7667
  PIN cut_7668
    DIRECTION OUTPUT ;
    USE SIGNAL ;
    PORT
      LAYER M4 ;
        RECT  73.356 45.744 73.44 45.768 ;
    END
  END cut_7668
  PIN cut_7669
    DIRECTION OUTPUT ;
    USE SIGNAL ;
    PORT
      LAYER M4 ;
        RECT  73.356 45.84 73.44 45.864 ;
    END
  END cut_7669
  PIN cut_7670
    DIRECTION OUTPUT ;
    USE SIGNAL ;
    PORT
      LAYER M4 ;
        RECT  73.356 45.936 73.44 45.96 ;
    END
  END cut_7670
  PIN cut_7671
    DIRECTION OUTPUT ;
    USE SIGNAL ;
    PORT
      LAYER M4 ;
        RECT  73.356 46.032 73.44 46.056 ;
    END
  END cut_7671
  PIN cut_7672
    DIRECTION OUTPUT ;
    USE SIGNAL ;
    PORT
      LAYER M4 ;
        RECT  73.356 46.128 73.44 46.152 ;
    END
  END cut_7672
  PIN cut_7673
    DIRECTION OUTPUT ;
    USE SIGNAL ;
    PORT
      LAYER M4 ;
        RECT  73.356 46.224 73.44 46.248 ;
    END
  END cut_7673
  PIN cut_7674
    DIRECTION OUTPUT ;
    USE SIGNAL ;
    PORT
      LAYER M4 ;
        RECT  73.356 46.32 73.44 46.344 ;
    END
  END cut_7674
  PIN cut_7675
    DIRECTION OUTPUT ;
    USE SIGNAL ;
    PORT
      LAYER M4 ;
        RECT  73.356 46.416 73.44 46.44 ;
    END
  END cut_7675
  PIN cut_7676
    DIRECTION OUTPUT ;
    USE SIGNAL ;
    PORT
      LAYER M4 ;
        RECT  73.356 46.512 73.44 46.536 ;
    END
  END cut_7676
  PIN cut_7677
    DIRECTION OUTPUT ;
    USE SIGNAL ;
    PORT
      LAYER M4 ;
        RECT  73.356 46.608 73.44 46.632 ;
    END
  END cut_7677
  PIN cut_7678
    DIRECTION OUTPUT ;
    USE SIGNAL ;
    PORT
      LAYER M4 ;
        RECT  73.356 46.704 73.44 46.728 ;
    END
  END cut_7678
  PIN cut_7679
    DIRECTION OUTPUT ;
    USE SIGNAL ;
    PORT
      LAYER M4 ;
        RECT  73.356 46.8 73.44 46.824 ;
    END
  END cut_7679
  PIN cut_7680
    DIRECTION OUTPUT ;
    USE SIGNAL ;
    PORT
      LAYER M4 ;
        RECT  73.356 46.896 73.44 46.92 ;
    END
  END cut_7680
  PIN cut_7681
    DIRECTION OUTPUT ;
    USE SIGNAL ;
    PORT
      LAYER M4 ;
        RECT  73.356 46.992 73.44 47.016 ;
    END
  END cut_7681
  PIN cut_7682
    DIRECTION OUTPUT ;
    USE SIGNAL ;
    PORT
      LAYER M4 ;
        RECT  73.356 47.088 73.44 47.112 ;
    END
  END cut_7682
  PIN cut_7683
    DIRECTION OUTPUT ;
    USE SIGNAL ;
    PORT
      LAYER M4 ;
        RECT  73.356 47.184 73.44 47.208 ;
    END
  END cut_7683
  PIN cut_7684
    DIRECTION OUTPUT ;
    USE SIGNAL ;
    PORT
      LAYER M4 ;
        RECT  73.356 47.28 73.44 47.304 ;
    END
  END cut_7684
  PIN cut_7685
    DIRECTION OUTPUT ;
    USE SIGNAL ;
    PORT
      LAYER M4 ;
        RECT  73.356 47.376 73.44 47.4 ;
    END
  END cut_7685
  PIN cut_7686
    DIRECTION OUTPUT ;
    USE SIGNAL ;
    PORT
      LAYER M4 ;
        RECT  73.356 47.472 73.44 47.496 ;
    END
  END cut_7686
  PIN cut_7687
    DIRECTION OUTPUT ;
    USE SIGNAL ;
    PORT
      LAYER M4 ;
        RECT  73.356 47.568 73.44 47.592 ;
    END
  END cut_7687
  PIN cut_7688
    DIRECTION OUTPUT ;
    USE SIGNAL ;
    PORT
      LAYER M4 ;
        RECT  73.356 47.664 73.44 47.688 ;
    END
  END cut_7688
  PIN cut_7689
    DIRECTION OUTPUT ;
    USE SIGNAL ;
    PORT
      LAYER M4 ;
        RECT  73.356 47.76 73.44 47.784 ;
    END
  END cut_7689
  PIN cut_7690
    DIRECTION OUTPUT ;
    USE SIGNAL ;
    PORT
      LAYER M4 ;
        RECT  73.356 47.856 73.44 47.88 ;
    END
  END cut_7690
  PIN cut_7691
    DIRECTION OUTPUT ;
    USE SIGNAL ;
    PORT
      LAYER M4 ;
        RECT  73.356 47.952 73.44 47.976 ;
    END
  END cut_7691
  PIN cut_7692
    DIRECTION OUTPUT ;
    USE SIGNAL ;
    PORT
      LAYER M4 ;
        RECT  73.356 48.048 73.44 48.072 ;
    END
  END cut_7692
  PIN cut_7693
    DIRECTION OUTPUT ;
    USE SIGNAL ;
    PORT
      LAYER M4 ;
        RECT  73.356 48.144 73.44 48.168 ;
    END
  END cut_7693
  PIN cut_7694
    DIRECTION OUTPUT ;
    USE SIGNAL ;
    PORT
      LAYER M4 ;
        RECT  73.356 48.24 73.44 48.264 ;
    END
  END cut_7694
  PIN cut_7695
    DIRECTION OUTPUT ;
    USE SIGNAL ;
    PORT
      LAYER M4 ;
        RECT  73.356 35.28 73.44 35.304 ;
    END
  END cut_7695
  PIN cut_7696
    DIRECTION OUTPUT ;
    USE SIGNAL ;
    PORT
      LAYER M4 ;
        RECT  73.356 35.376 73.44 35.4 ;
    END
  END cut_7696
  PIN cut_7697
    DIRECTION OUTPUT ;
    USE SIGNAL ;
    PORT
      LAYER M4 ;
        RECT  73.356 35.472 73.44 35.496 ;
    END
  END cut_7697
  PIN cut_7698
    DIRECTION OUTPUT ;
    USE SIGNAL ;
    PORT
      LAYER M4 ;
        RECT  73.356 35.568 73.44 35.592 ;
    END
  END cut_7698
  PIN cut_7699
    DIRECTION OUTPUT ;
    USE SIGNAL ;
    PORT
      LAYER M4 ;
        RECT  73.356 35.664 73.44 35.688 ;
    END
  END cut_7699
  PIN cut_7700
    DIRECTION OUTPUT ;
    USE SIGNAL ;
    PORT
      LAYER M4 ;
        RECT  73.356 35.76 73.44 35.784 ;
    END
  END cut_7700
  PIN cut_7701
    DIRECTION OUTPUT ;
    USE SIGNAL ;
    PORT
      LAYER M4 ;
        RECT  73.356 35.856 73.44 35.88 ;
    END
  END cut_7701
  PIN cut_7702
    DIRECTION OUTPUT ;
    USE SIGNAL ;
    PORT
      LAYER M4 ;
        RECT  73.356 35.952 73.44 35.976 ;
    END
  END cut_7702
  PIN cut_7703
    DIRECTION OUTPUT ;
    USE SIGNAL ;
    PORT
      LAYER M4 ;
        RECT  73.356 36.048 73.44 36.072 ;
    END
  END cut_7703
  PIN cut_7704
    DIRECTION OUTPUT ;
    USE SIGNAL ;
    PORT
      LAYER M4 ;
        RECT  73.356 36.144 73.44 36.168 ;
    END
  END cut_7704
  PIN cut_7705
    DIRECTION OUTPUT ;
    USE SIGNAL ;
    PORT
      LAYER M4 ;
        RECT  73.356 36.24 73.44 36.264 ;
    END
  END cut_7705
  PIN cut_7706
    DIRECTION OUTPUT ;
    USE SIGNAL ;
    PORT
      LAYER M4 ;
        RECT  73.356 36.336 73.44 36.36 ;
    END
  END cut_7706
  PIN cut_7707
    DIRECTION OUTPUT ;
    USE SIGNAL ;
    PORT
      LAYER M4 ;
        RECT  73.356 36.432 73.44 36.456 ;
    END
  END cut_7707
  PIN cut_7708
    DIRECTION OUTPUT ;
    USE SIGNAL ;
    PORT
      LAYER M4 ;
        RECT  73.356 36.528 73.44 36.552 ;
    END
  END cut_7708
  PIN cut_7709
    DIRECTION OUTPUT ;
    USE SIGNAL ;
    PORT
      LAYER M4 ;
        RECT  73.356 36.624 73.44 36.648 ;
    END
  END cut_7709
  PIN cut_7710
    DIRECTION OUTPUT ;
    USE SIGNAL ;
    PORT
      LAYER M4 ;
        RECT  73.356 36.72 73.44 36.744 ;
    END
  END cut_7710
  PIN cut_7711
    DIRECTION OUTPUT ;
    USE SIGNAL ;
    PORT
      LAYER M4 ;
        RECT  73.356 36.816 73.44 36.84 ;
    END
  END cut_7711
  PIN cut_7712
    DIRECTION OUTPUT ;
    USE SIGNAL ;
    PORT
      LAYER M4 ;
        RECT  73.356 36.912 73.44 36.936 ;
    END
  END cut_7712
  PIN cut_7713
    DIRECTION OUTPUT ;
    USE SIGNAL ;
    PORT
      LAYER M4 ;
        RECT  73.356 37.008 73.44 37.032 ;
    END
  END cut_7713
  PIN cut_7714
    DIRECTION OUTPUT ;
    USE SIGNAL ;
    PORT
      LAYER M4 ;
        RECT  73.356 37.104 73.44 37.128 ;
    END
  END cut_7714
  PIN cut_7715
    DIRECTION OUTPUT ;
    USE SIGNAL ;
    PORT
      LAYER M4 ;
        RECT  73.356 37.2 73.44 37.224 ;
    END
  END cut_7715
  PIN cut_7716
    DIRECTION OUTPUT ;
    USE SIGNAL ;
    PORT
      LAYER M4 ;
        RECT  73.356 37.296 73.44 37.32 ;
    END
  END cut_7716
  PIN cut_7717
    DIRECTION OUTPUT ;
    USE SIGNAL ;
    PORT
      LAYER M4 ;
        RECT  73.356 37.392 73.44 37.416 ;
    END
  END cut_7717
  PIN cut_7718
    DIRECTION OUTPUT ;
    USE SIGNAL ;
    PORT
      LAYER M4 ;
        RECT  73.356 37.488 73.44 37.512 ;
    END
  END cut_7718
  PIN cut_7719
    DIRECTION OUTPUT ;
    USE SIGNAL ;
    PORT
      LAYER M4 ;
        RECT  73.356 37.584 73.44 37.608 ;
    END
  END cut_7719
  PIN cut_7720
    DIRECTION OUTPUT ;
    USE SIGNAL ;
    PORT
      LAYER M4 ;
        RECT  73.356 37.68 73.44 37.704 ;
    END
  END cut_7720
  PIN cut_7721
    DIRECTION OUTPUT ;
    USE SIGNAL ;
    PORT
      LAYER M4 ;
        RECT  73.356 37.776 73.44 37.8 ;
    END
  END cut_7721
  PIN cut_7722
    DIRECTION OUTPUT ;
    USE SIGNAL ;
    PORT
      LAYER M4 ;
        RECT  73.356 37.872 73.44 37.896 ;
    END
  END cut_7722
  PIN cut_7723
    DIRECTION OUTPUT ;
    USE SIGNAL ;
    PORT
      LAYER M4 ;
        RECT  73.356 37.968 73.44 37.992 ;
    END
  END cut_7723
  PIN cut_7724
    DIRECTION OUTPUT ;
    USE SIGNAL ;
    PORT
      LAYER M4 ;
        RECT  73.356 38.064 73.44 38.088 ;
    END
  END cut_7724
  PIN cut_7725
    DIRECTION OUTPUT ;
    USE SIGNAL ;
    PORT
      LAYER M4 ;
        RECT  73.356 38.16 73.44 38.184 ;
    END
  END cut_7725
  PIN cut_7726
    DIRECTION OUTPUT ;
    USE SIGNAL ;
    PORT
      LAYER M4 ;
        RECT  73.356 38.256 73.44 38.28 ;
    END
  END cut_7726
  PIN cut_7727
    DIRECTION OUTPUT ;
    USE SIGNAL ;
    PORT
      LAYER M4 ;
        RECT  73.356 22.992 73.44 23.016 ;
    END
  END cut_7727
  PIN cut_7728
    DIRECTION OUTPUT ;
    USE SIGNAL ;
    PORT
      LAYER M4 ;
        RECT  73.356 23.088 73.44 23.112 ;
    END
  END cut_7728
  PIN cut_7729
    DIRECTION OUTPUT ;
    USE SIGNAL ;
    PORT
      LAYER M4 ;
        RECT  73.356 23.184 73.44 23.208 ;
    END
  END cut_7729
  PIN cut_7730
    DIRECTION OUTPUT ;
    USE SIGNAL ;
    PORT
      LAYER M4 ;
        RECT  73.356 23.28 73.44 23.304 ;
    END
  END cut_7730
  PIN cut_7731
    DIRECTION OUTPUT ;
    USE SIGNAL ;
    PORT
      LAYER M4 ;
        RECT  73.356 23.376 73.44 23.4 ;
    END
  END cut_7731
  PIN cut_7732
    DIRECTION OUTPUT ;
    USE SIGNAL ;
    PORT
      LAYER M4 ;
        RECT  73.356 23.472 73.44 23.496 ;
    END
  END cut_7732
  PIN cut_7733
    DIRECTION OUTPUT ;
    USE SIGNAL ;
    PORT
      LAYER M4 ;
        RECT  73.356 23.568 73.44 23.592 ;
    END
  END cut_7733
  PIN cut_7734
    DIRECTION OUTPUT ;
    USE SIGNAL ;
    PORT
      LAYER M4 ;
        RECT  73.356 23.664 73.44 23.688 ;
    END
  END cut_7734
  PIN cut_7735
    DIRECTION OUTPUT ;
    USE SIGNAL ;
    PORT
      LAYER M4 ;
        RECT  73.356 23.76 73.44 23.784 ;
    END
  END cut_7735
  PIN cut_7736
    DIRECTION OUTPUT ;
    USE SIGNAL ;
    PORT
      LAYER M4 ;
        RECT  73.356 23.856 73.44 23.88 ;
    END
  END cut_7736
  PIN cut_7737
    DIRECTION OUTPUT ;
    USE SIGNAL ;
    PORT
      LAYER M4 ;
        RECT  73.356 23.952 73.44 23.976 ;
    END
  END cut_7737
  PIN cut_7738
    DIRECTION OUTPUT ;
    USE SIGNAL ;
    PORT
      LAYER M4 ;
        RECT  73.356 24.048 73.44 24.072 ;
    END
  END cut_7738
  PIN cut_7739
    DIRECTION OUTPUT ;
    USE SIGNAL ;
    PORT
      LAYER M4 ;
        RECT  73.356 24.144 73.44 24.168 ;
    END
  END cut_7739
  PIN cut_7740
    DIRECTION OUTPUT ;
    USE SIGNAL ;
    PORT
      LAYER M4 ;
        RECT  73.356 24.24 73.44 24.264 ;
    END
  END cut_7740
  PIN cut_7741
    DIRECTION OUTPUT ;
    USE SIGNAL ;
    PORT
      LAYER M4 ;
        RECT  73.356 24.336 73.44 24.36 ;
    END
  END cut_7741
  PIN cut_7742
    DIRECTION OUTPUT ;
    USE SIGNAL ;
    PORT
      LAYER M4 ;
        RECT  73.356 24.432 73.44 24.456 ;
    END
  END cut_7742
  PIN cut_7743
    DIRECTION OUTPUT ;
    USE SIGNAL ;
    PORT
      LAYER M4 ;
        RECT  73.356 24.528 73.44 24.552 ;
    END
  END cut_7743
  PIN cut_7744
    DIRECTION OUTPUT ;
    USE SIGNAL ;
    PORT
      LAYER M4 ;
        RECT  73.356 24.624 73.44 24.648 ;
    END
  END cut_7744
  PIN cut_7745
    DIRECTION OUTPUT ;
    USE SIGNAL ;
    PORT
      LAYER M4 ;
        RECT  73.356 24.72 73.44 24.744 ;
    END
  END cut_7745
  PIN cut_7746
    DIRECTION OUTPUT ;
    USE SIGNAL ;
    PORT
      LAYER M4 ;
        RECT  73.356 24.816 73.44 24.84 ;
    END
  END cut_7746
  PIN cut_7747
    DIRECTION OUTPUT ;
    USE SIGNAL ;
    PORT
      LAYER M4 ;
        RECT  73.356 24.912 73.44 24.936 ;
    END
  END cut_7747
  PIN cut_7748
    DIRECTION OUTPUT ;
    USE SIGNAL ;
    PORT
      LAYER M4 ;
        RECT  73.356 25.008 73.44 25.032 ;
    END
  END cut_7748
  PIN cut_7749
    DIRECTION OUTPUT ;
    USE SIGNAL ;
    PORT
      LAYER M4 ;
        RECT  73.356 25.104 73.44 25.128 ;
    END
  END cut_7749
  PIN cut_7750
    DIRECTION OUTPUT ;
    USE SIGNAL ;
    PORT
      LAYER M4 ;
        RECT  73.356 25.2 73.44 25.224 ;
    END
  END cut_7750
  PIN cut_7751
    DIRECTION OUTPUT ;
    USE SIGNAL ;
    PORT
      LAYER M4 ;
        RECT  73.356 25.296 73.44 25.32 ;
    END
  END cut_7751
  PIN cut_7752
    DIRECTION OUTPUT ;
    USE SIGNAL ;
    PORT
      LAYER M4 ;
        RECT  73.356 25.392 73.44 25.416 ;
    END
  END cut_7752
  PIN cut_7753
    DIRECTION OUTPUT ;
    USE SIGNAL ;
    PORT
      LAYER M4 ;
        RECT  73.356 25.488 73.44 25.512 ;
    END
  END cut_7753
  PIN cut_7754
    DIRECTION OUTPUT ;
    USE SIGNAL ;
    PORT
      LAYER M4 ;
        RECT  73.356 25.584 73.44 25.608 ;
    END
  END cut_7754
  PIN cut_7755
    DIRECTION OUTPUT ;
    USE SIGNAL ;
    PORT
      LAYER M4 ;
        RECT  73.356 25.68 73.44 25.704 ;
    END
  END cut_7755
  PIN cut_7756
    DIRECTION OUTPUT ;
    USE SIGNAL ;
    PORT
      LAYER M4 ;
        RECT  73.356 25.776 73.44 25.8 ;
    END
  END cut_7756
  PIN cut_7757
    DIRECTION OUTPUT ;
    USE SIGNAL ;
    PORT
      LAYER M4 ;
        RECT  73.356 25.872 73.44 25.896 ;
    END
  END cut_7757
  PIN cut_7758
    DIRECTION OUTPUT ;
    USE SIGNAL ;
    PORT
      LAYER M4 ;
        RECT  73.356 25.968 73.44 25.992 ;
    END
  END cut_7758
  PIN cut_7759
    DIRECTION OUTPUT ;
    USE SIGNAL ;
    PORT
      LAYER M4 ;
        RECT  73.356 29.136 73.44 29.16 ;
    END
  END cut_7759
  PIN cut_7760
    DIRECTION OUTPUT ;
    USE SIGNAL ;
    PORT
      LAYER M4 ;
        RECT  73.356 29.232 73.44 29.256 ;
    END
  END cut_7760
  PIN cut_7761
    DIRECTION OUTPUT ;
    USE SIGNAL ;
    PORT
      LAYER M4 ;
        RECT  73.356 29.328 73.44 29.352 ;
    END
  END cut_7761
  PIN cut_7762
    DIRECTION OUTPUT ;
    USE SIGNAL ;
    PORT
      LAYER M4 ;
        RECT  73.356 29.424 73.44 29.448 ;
    END
  END cut_7762
  PIN cut_7763
    DIRECTION OUTPUT ;
    USE SIGNAL ;
    PORT
      LAYER M4 ;
        RECT  73.356 29.52 73.44 29.544 ;
    END
  END cut_7763
  PIN cut_7764
    DIRECTION OUTPUT ;
    USE SIGNAL ;
    PORT
      LAYER M4 ;
        RECT  73.356 29.616 73.44 29.64 ;
    END
  END cut_7764
  PIN cut_7765
    DIRECTION OUTPUT ;
    USE SIGNAL ;
    PORT
      LAYER M4 ;
        RECT  73.356 29.712 73.44 29.736 ;
    END
  END cut_7765
  PIN cut_7766
    DIRECTION OUTPUT ;
    USE SIGNAL ;
    PORT
      LAYER M4 ;
        RECT  73.356 29.808 73.44 29.832 ;
    END
  END cut_7766
  PIN cut_7767
    DIRECTION OUTPUT ;
    USE SIGNAL ;
    PORT
      LAYER M4 ;
        RECT  73.356 29.904 73.44 29.928 ;
    END
  END cut_7767
  PIN cut_7768
    DIRECTION OUTPUT ;
    USE SIGNAL ;
    PORT
      LAYER M5 ;
        RECT  26.448 73.356 26.472 73.44 ;
    END
  END cut_7768
  PIN cut_7873
    DIRECTION OUTPUT ;
    USE SIGNAL ;
    PORT
      LAYER M4 ;
        RECT  73.356 30 73.44 30.024 ;
    END
  END cut_7873
  PIN cut_7874
    DIRECTION OUTPUT ;
    USE SIGNAL ;
    PORT
      LAYER M4 ;
        RECT  73.356 30.096 73.44 30.12 ;
    END
  END cut_7874
  PIN cut_7875
    DIRECTION OUTPUT ;
    USE SIGNAL ;
    PORT
      LAYER M4 ;
        RECT  73.356 30.192 73.44 30.216 ;
    END
  END cut_7875
  PIN cut_7876
    DIRECTION OUTPUT ;
    USE SIGNAL ;
    PORT
      LAYER M4 ;
        RECT  73.356 30.288 73.44 30.312 ;
    END
  END cut_7876
  PIN cut_7877
    DIRECTION OUTPUT ;
    USE SIGNAL ;
    PORT
      LAYER M4 ;
        RECT  73.356 30.384 73.44 30.408 ;
    END
  END cut_7877
  PIN cut_7878
    DIRECTION OUTPUT ;
    USE SIGNAL ;
    PORT
      LAYER M4 ;
        RECT  73.356 30.48 73.44 30.504 ;
    END
  END cut_7878
  PIN cut_7879
    DIRECTION OUTPUT ;
    USE SIGNAL ;
    PORT
      LAYER M4 ;
        RECT  73.356 30.576 73.44 30.6 ;
    END
  END cut_7879
  PIN cut_7880
    DIRECTION OUTPUT ;
    USE SIGNAL ;
    PORT
      LAYER M4 ;
        RECT  73.356 30.672 73.44 30.696 ;
    END
  END cut_7880
  PIN cut_7881
    DIRECTION OUTPUT ;
    USE SIGNAL ;
    PORT
      LAYER M4 ;
        RECT  73.356 30.768 73.44 30.792 ;
    END
  END cut_7881
  PIN cut_7882
    DIRECTION OUTPUT ;
    USE SIGNAL ;
    PORT
      LAYER M4 ;
        RECT  73.356 30.864 73.44 30.888 ;
    END
  END cut_7882
  PIN cut_7883
    DIRECTION OUTPUT ;
    USE SIGNAL ;
    PORT
      LAYER M4 ;
        RECT  73.356 30.96 73.44 30.984 ;
    END
  END cut_7883
  PIN cut_7884
    DIRECTION OUTPUT ;
    USE SIGNAL ;
    PORT
      LAYER M4 ;
        RECT  73.356 31.056 73.44 31.08 ;
    END
  END cut_7884
  PIN cut_7885
    DIRECTION OUTPUT ;
    USE SIGNAL ;
    PORT
      LAYER M4 ;
        RECT  73.356 31.152 73.44 31.176 ;
    END
  END cut_7885
  PIN cut_7886
    DIRECTION OUTPUT ;
    USE SIGNAL ;
    PORT
      LAYER M4 ;
        RECT  73.356 31.248 73.44 31.272 ;
    END
  END cut_7886
  PIN cut_7887
    DIRECTION OUTPUT ;
    USE SIGNAL ;
    PORT
      LAYER M4 ;
        RECT  73.356 31.344 73.44 31.368 ;
    END
  END cut_7887
  PIN cut_7888
    DIRECTION OUTPUT ;
    USE SIGNAL ;
    PORT
      LAYER M4 ;
        RECT  73.356 31.44 73.44 31.464 ;
    END
  END cut_7888
  PIN cut_7889
    DIRECTION OUTPUT ;
    USE SIGNAL ;
    PORT
      LAYER M4 ;
        RECT  73.356 31.536 73.44 31.56 ;
    END
  END cut_7889
  PIN cut_7890
    DIRECTION OUTPUT ;
    USE SIGNAL ;
    PORT
      LAYER M4 ;
        RECT  73.356 31.632 73.44 31.656 ;
    END
  END cut_7890
  PIN cut_7891
    DIRECTION OUTPUT ;
    USE SIGNAL ;
    PORT
      LAYER M4 ;
        RECT  73.356 31.728 73.44 31.752 ;
    END
  END cut_7891
  PIN cut_7892
    DIRECTION OUTPUT ;
    USE SIGNAL ;
    PORT
      LAYER M4 ;
        RECT  73.356 31.824 73.44 31.848 ;
    END
  END cut_7892
  PIN cut_7893
    DIRECTION OUTPUT ;
    USE SIGNAL ;
    PORT
      LAYER M4 ;
        RECT  73.356 31.92 73.44 31.944 ;
    END
  END cut_7893
  PIN cut_7894
    DIRECTION OUTPUT ;
    USE SIGNAL ;
    PORT
      LAYER M4 ;
        RECT  73.356 32.016 73.44 32.04 ;
    END
  END cut_7894
  PIN cut_7895
    DIRECTION OUTPUT ;
    USE SIGNAL ;
    PORT
      LAYER M4 ;
        RECT  73.356 32.112 73.44 32.136 ;
    END
  END cut_7895
  PIN cut_7896
    DIRECTION OUTPUT ;
    USE SIGNAL ;
    PORT
      LAYER M4 ;
        RECT  73.356 32.208 73.44 32.232 ;
    END
  END cut_7896
  PIN cut_7897
    DIRECTION OUTPUT ;
    USE SIGNAL ;
    PORT
      LAYER M4 ;
        RECT  73.356 32.304 73.44 32.328 ;
    END
  END cut_7897
  PIN cut_7898
    DIRECTION OUTPUT ;
    USE SIGNAL ;
    PORT
      LAYER M4 ;
        RECT  73.356 32.4 73.44 32.424 ;
    END
  END cut_7898
  PIN cut_8
    DIRECTION INPUT ;
    USE SIGNAL ;
    PORT
      LAYER M4 ;
        RECT  0 28.464 0.084 28.488 ;
    END
  END cut_8
  PIN cut_8003
    DIRECTION OUTPUT ;
    USE SIGNAL ;
    PORT
      LAYER M4 ;
        RECT  73.356 32.496 73.44 32.52 ;
    END
  END cut_8003
  PIN cut_8004
    DIRECTION OUTPUT ;
    USE SIGNAL ;
    PORT
      LAYER M4 ;
        RECT  73.356 32.592 73.44 32.616 ;
    END
  END cut_8004
  PIN cut_8005
    DIRECTION OUTPUT ;
    USE SIGNAL ;
    PORT
      LAYER M4 ;
        RECT  73.356 32.688 73.44 32.712 ;
    END
  END cut_8005
  PIN cut_8006
    DIRECTION OUTPUT ;
    USE SIGNAL ;
    PORT
      LAYER M4 ;
        RECT  73.356 32.784 73.44 32.808 ;
    END
  END cut_8006
  PIN cut_8007
    DIRECTION OUTPUT ;
    USE SIGNAL ;
    PORT
      LAYER M4 ;
        RECT  73.356 32.88 73.44 32.904 ;
    END
  END cut_8007
  PIN cut_8008
    DIRECTION OUTPUT ;
    USE SIGNAL ;
    PORT
      LAYER M4 ;
        RECT  73.356 32.976 73.44 33 ;
    END
  END cut_8008
  PIN cut_8009
    DIRECTION OUTPUT ;
    USE SIGNAL ;
    PORT
      LAYER M4 ;
        RECT  73.356 33.072 73.44 33.096 ;
    END
  END cut_8009
  PIN cut_8010
    DIRECTION OUTPUT ;
    USE SIGNAL ;
    PORT
      LAYER M4 ;
        RECT  73.356 33.168 73.44 33.192 ;
    END
  END cut_8010
  PIN cut_8011
    DIRECTION OUTPUT ;
    USE SIGNAL ;
    PORT
      LAYER M4 ;
        RECT  73.356 33.264 73.44 33.288 ;
    END
  END cut_8011
  PIN cut_8012
    DIRECTION OUTPUT ;
    USE SIGNAL ;
    PORT
      LAYER M4 ;
        RECT  73.356 33.36 73.44 33.384 ;
    END
  END cut_8012
  PIN cut_8013
    DIRECTION OUTPUT ;
    USE SIGNAL ;
    PORT
      LAYER M4 ;
        RECT  73.356 33.456 73.44 33.48 ;
    END
  END cut_8013
  PIN cut_8014
    DIRECTION OUTPUT ;
    USE SIGNAL ;
    PORT
      LAYER M4 ;
        RECT  73.356 33.552 73.44 33.576 ;
    END
  END cut_8014
  PIN cut_8015
    DIRECTION OUTPUT ;
    USE SIGNAL ;
    PORT
      LAYER M4 ;
        RECT  73.356 33.648 73.44 33.672 ;
    END
  END cut_8015
  PIN cut_8016
    DIRECTION OUTPUT ;
    USE SIGNAL ;
    PORT
      LAYER M4 ;
        RECT  73.356 33.744 73.44 33.768 ;
    END
  END cut_8016
  PIN cut_8017
    DIRECTION OUTPUT ;
    USE SIGNAL ;
    PORT
      LAYER M4 ;
        RECT  73.356 33.84 73.44 33.864 ;
    END
  END cut_8017
  PIN cut_8018
    DIRECTION OUTPUT ;
    USE SIGNAL ;
    PORT
      LAYER M4 ;
        RECT  73.356 33.936 73.44 33.96 ;
    END
  END cut_8018
  PIN cut_8019
    DIRECTION OUTPUT ;
    USE SIGNAL ;
    PORT
      LAYER M4 ;
        RECT  73.356 34.032 73.44 34.056 ;
    END
  END cut_8019
  PIN cut_8020
    DIRECTION OUTPUT ;
    USE SIGNAL ;
    PORT
      LAYER M4 ;
        RECT  73.356 34.128 73.44 34.152 ;
    END
  END cut_8020
  PIN cut_8021
    DIRECTION OUTPUT ;
    USE SIGNAL ;
    PORT
      LAYER M4 ;
        RECT  73.356 34.224 73.44 34.248 ;
    END
  END cut_8021
  PIN cut_8022
    DIRECTION OUTPUT ;
    USE SIGNAL ;
    PORT
      LAYER M4 ;
        RECT  73.356 34.32 73.44 34.344 ;
    END
  END cut_8022
  PIN cut_8023
    DIRECTION OUTPUT ;
    USE SIGNAL ;
    PORT
      LAYER M4 ;
        RECT  73.356 34.416 73.44 34.44 ;
    END
  END cut_8023
  PIN cut_8024
    DIRECTION OUTPUT ;
    USE SIGNAL ;
    PORT
      LAYER M4 ;
        RECT  73.356 34.512 73.44 34.536 ;
    END
  END cut_8024
  PIN cut_8025
    DIRECTION OUTPUT ;
    USE SIGNAL ;
    PORT
      LAYER M4 ;
        RECT  73.356 34.608 73.44 34.632 ;
    END
  END cut_8025
  PIN cut_8026
    DIRECTION OUTPUT ;
    USE SIGNAL ;
    PORT
      LAYER M4 ;
        RECT  73.356 34.704 73.44 34.728 ;
    END
  END cut_8026
  PIN cut_8027
    DIRECTION OUTPUT ;
    USE SIGNAL ;
    PORT
      LAYER M4 ;
        RECT  73.356 34.8 73.44 34.824 ;
    END
  END cut_8027
  PIN cut_8028
    DIRECTION OUTPUT ;
    USE SIGNAL ;
    PORT
      LAYER M4 ;
        RECT  73.356 34.896 73.44 34.92 ;
    END
  END cut_8028
  PIN cut_8382
    DIRECTION INPUT ;
    USE SIGNAL ;
    PORT
      LAYER M4 ;
        RECT  0 18.288 0.084 18.312 ;
    END
  END cut_8382
  PIN cut_8383
    DIRECTION INPUT ;
    USE SIGNAL ;
    PORT
      LAYER M4 ;
        RECT  0 18.384 0.084 18.408 ;
    END
  END cut_8383
  PIN cut_8386
    DIRECTION INPUT ;
    USE SIGNAL ;
    PORT
      LAYER M4 ;
        RECT  0 18.48 0.084 18.504 ;
    END
  END cut_8386
  PIN cut_8387
    DIRECTION INPUT ;
    USE SIGNAL ;
    PORT
      LAYER M4 ;
        RECT  0 18.576 0.084 18.6 ;
    END
  END cut_8387
  PIN cut_8440
    DIRECTION OUTPUT ;
    USE SIGNAL ;
    PORT
      LAYER M4 ;
        RECT  73.356 34.992 73.44 35.016 ;
    END
  END cut_8440
  PIN cut_8441
    DIRECTION OUTPUT ;
    USE SIGNAL ;
    PORT
      LAYER M4 ;
        RECT  73.356 35.088 73.44 35.112 ;
    END
  END cut_8441
  PIN cut_8442
    DIRECTION OUTPUT ;
    USE SIGNAL ;
    PORT
      LAYER M4 ;
        RECT  73.356 35.184 73.44 35.208 ;
    END
  END cut_8442
  PIN cut_8444
    DIRECTION INPUT ;
    USE SIGNAL ;
    PORT
      LAYER M4 ;
        RECT  0 18.672 0.084 18.696 ;
    END
  END cut_8444
  PIN cut_8445
    DIRECTION INPUT ;
    USE SIGNAL ;
    PORT
      LAYER M4 ;
        RECT  0 18.768 0.084 18.792 ;
    END
  END cut_8445
  PIN cut_8446
    DIRECTION INPUT ;
    USE SIGNAL ;
    PORT
      LAYER M4 ;
        RECT  0 18.864 0.084 18.888 ;
    END
  END cut_8446
  PIN cut_8447
    DIRECTION INPUT ;
    USE SIGNAL ;
    PORT
      LAYER M4 ;
        RECT  0 22.032 0.084 22.056 ;
    END
  END cut_8447
  PIN cut_8448
    DIRECTION INPUT ;
    USE SIGNAL ;
    PORT
      LAYER M4 ;
        RECT  0 22.128 0.084 22.152 ;
    END
  END cut_8448
  PIN cut_8449
    DIRECTION INPUT ;
    USE SIGNAL ;
    PORT
      LAYER M4 ;
        RECT  0 22.224 0.084 22.248 ;
    END
  END cut_8449
  PIN cut_8450
    DIRECTION INPUT ;
    USE SIGNAL ;
    PORT
      LAYER M4 ;
        RECT  0 22.32 0.084 22.344 ;
    END
  END cut_8450
  PIN cut_8451
    DIRECTION INPUT ;
    USE SIGNAL ;
    PORT
      LAYER M4 ;
        RECT  0 22.416 0.084 22.44 ;
    END
  END cut_8451
  PIN cut_8452
    DIRECTION INPUT ;
    USE SIGNAL ;
    PORT
      LAYER M4 ;
        RECT  0 22.512 0.084 22.536 ;
    END
  END cut_8452
  PIN cut_8453
    DIRECTION INPUT ;
    USE SIGNAL ;
    PORT
      LAYER M4 ;
        RECT  0 22.608 0.084 22.632 ;
    END
  END cut_8453
  PIN cut_8454
    DIRECTION INPUT ;
    USE SIGNAL ;
    PORT
      LAYER M4 ;
        RECT  0 22.704 0.084 22.728 ;
    END
  END cut_8454
  PIN cut_8455
    DIRECTION INPUT ;
    USE SIGNAL ;
    PORT
      LAYER M4 ;
        RECT  0 22.8 0.084 22.824 ;
    END
  END cut_8455
  PIN cut_8456
    DIRECTION INPUT ;
    USE SIGNAL ;
    PORT
      LAYER M4 ;
        RECT  0 22.896 0.084 22.92 ;
    END
  END cut_8456
  PIN cut_8457
    DIRECTION INPUT ;
    USE SIGNAL ;
    PORT
      LAYER M4 ;
        RECT  0 22.992 0.084 23.016 ;
    END
  END cut_8457
  PIN cut_8458
    DIRECTION INPUT ;
    USE SIGNAL ;
    PORT
      LAYER M4 ;
        RECT  0 23.088 0.084 23.112 ;
    END
  END cut_8458
  PIN cut_8459
    DIRECTION INPUT ;
    USE SIGNAL ;
    PORT
      LAYER M4 ;
        RECT  0 23.184 0.084 23.208 ;
    END
  END cut_8459
  PIN cut_8460
    DIRECTION INPUT ;
    USE SIGNAL ;
    PORT
      LAYER M4 ;
        RECT  0 23.28 0.084 23.304 ;
    END
  END cut_8460
  PIN cut_8461
    DIRECTION INPUT ;
    USE SIGNAL ;
    PORT
      LAYER M4 ;
        RECT  0 23.376 0.084 23.4 ;
    END
  END cut_8461
  PIN cut_8462
    DIRECTION INPUT ;
    USE SIGNAL ;
    PORT
      LAYER M4 ;
        RECT  0 23.472 0.084 23.496 ;
    END
  END cut_8462
  PIN cut_8463
    DIRECTION INPUT ;
    USE SIGNAL ;
    PORT
      LAYER M4 ;
        RECT  0 23.568 0.084 23.592 ;
    END
  END cut_8463
  PIN cut_8464
    DIRECTION INPUT ;
    USE SIGNAL ;
    PORT
      LAYER M4 ;
        RECT  0 23.664 0.084 23.688 ;
    END
  END cut_8464
  PIN cut_8465
    DIRECTION INPUT ;
    USE SIGNAL ;
    PORT
      LAYER M4 ;
        RECT  0 23.76 0.084 23.784 ;
    END
  END cut_8465
  PIN cut_8466
    DIRECTION INPUT ;
    USE SIGNAL ;
    PORT
      LAYER M4 ;
        RECT  0 23.856 0.084 23.88 ;
    END
  END cut_8466
  PIN cut_8467
    DIRECTION INPUT ;
    USE SIGNAL ;
    PORT
      LAYER M4 ;
        RECT  0 23.952 0.084 23.976 ;
    END
  END cut_8467
  PIN cut_8468
    DIRECTION INPUT ;
    USE SIGNAL ;
    PORT
      LAYER M4 ;
        RECT  0 24.048 0.084 24.072 ;
    END
  END cut_8468
  PIN cut_8469
    DIRECTION INPUT ;
    USE SIGNAL ;
    PORT
      LAYER M4 ;
        RECT  0 24.144 0.084 24.168 ;
    END
  END cut_8469
  PIN cut_8470
    DIRECTION INPUT ;
    USE SIGNAL ;
    PORT
      LAYER M4 ;
        RECT  0 24.24 0.084 24.264 ;
    END
  END cut_8470
  PIN cut_8471
    DIRECTION INPUT ;
    USE SIGNAL ;
    PORT
      LAYER M4 ;
        RECT  0 24.336 0.084 24.36 ;
    END
  END cut_8471
  PIN cut_8472
    DIRECTION INPUT ;
    USE SIGNAL ;
    PORT
      LAYER M4 ;
        RECT  0 24.432 0.084 24.456 ;
    END
  END cut_8472
  PIN cut_8473
    DIRECTION INPUT ;
    USE SIGNAL ;
    PORT
      LAYER M4 ;
        RECT  0 24.528 0.084 24.552 ;
    END
  END cut_8473
  PIN cut_8474
    DIRECTION INPUT ;
    USE SIGNAL ;
    PORT
      LAYER M4 ;
        RECT  0 24.624 0.084 24.648 ;
    END
  END cut_8474
  PIN cut_8475
    DIRECTION INPUT ;
    USE SIGNAL ;
    PORT
      LAYER M4 ;
        RECT  0 24.72 0.084 24.744 ;
    END
  END cut_8475
  PIN cut_8476
    DIRECTION INPUT ;
    USE SIGNAL ;
    PORT
      LAYER M4 ;
        RECT  0 24.816 0.084 24.84 ;
    END
  END cut_8476
  PIN cut_8477
    DIRECTION INPUT ;
    USE SIGNAL ;
    PORT
      LAYER M4 ;
        RECT  0 24.912 0.084 24.936 ;
    END
  END cut_8477
  PIN cut_8478
    DIRECTION INPUT ;
    USE SIGNAL ;
    PORT
      LAYER M4 ;
        RECT  0 25.008 0.084 25.032 ;
    END
  END cut_8478
  PIN cut_8479
    DIRECTION INPUT ;
    USE SIGNAL ;
    PORT
      LAYER M4 ;
        RECT  0 18.96 0.084 18.984 ;
    END
  END cut_8479
  PIN cut_8480
    DIRECTION INPUT ;
    USE SIGNAL ;
    PORT
      LAYER M4 ;
        RECT  0 19.056 0.084 19.08 ;
    END
  END cut_8480
  PIN cut_8481
    DIRECTION INPUT ;
    USE SIGNAL ;
    PORT
      LAYER M4 ;
        RECT  0 19.152 0.084 19.176 ;
    END
  END cut_8481
  PIN cut_8482
    DIRECTION INPUT ;
    USE SIGNAL ;
    PORT
      LAYER M4 ;
        RECT  0 19.248 0.084 19.272 ;
    END
  END cut_8482
  PIN cut_8483
    DIRECTION INPUT ;
    USE SIGNAL ;
    PORT
      LAYER M4 ;
        RECT  0 19.344 0.084 19.368 ;
    END
  END cut_8483
  PIN cut_8484
    DIRECTION INPUT ;
    USE SIGNAL ;
    PORT
      LAYER M4 ;
        RECT  0 19.44 0.084 19.464 ;
    END
  END cut_8484
  PIN cut_8485
    DIRECTION INPUT ;
    USE SIGNAL ;
    PORT
      LAYER M4 ;
        RECT  0 19.536 0.084 19.56 ;
    END
  END cut_8485
  PIN cut_8486
    DIRECTION INPUT ;
    USE SIGNAL ;
    PORT
      LAYER M4 ;
        RECT  0 19.632 0.084 19.656 ;
    END
  END cut_8486
  PIN cut_8487
    DIRECTION INPUT ;
    USE SIGNAL ;
    PORT
      LAYER M4 ;
        RECT  0 19.728 0.084 19.752 ;
    END
  END cut_8487
  PIN cut_8488
    DIRECTION INPUT ;
    USE SIGNAL ;
    PORT
      LAYER M4 ;
        RECT  0 19.824 0.084 19.848 ;
    END
  END cut_8488
  PIN cut_8489
    DIRECTION INPUT ;
    USE SIGNAL ;
    PORT
      LAYER M4 ;
        RECT  0 19.92 0.084 19.944 ;
    END
  END cut_8489
  PIN cut_8490
    DIRECTION INPUT ;
    USE SIGNAL ;
    PORT
      LAYER M4 ;
        RECT  0 20.016 0.084 20.04 ;
    END
  END cut_8490
  PIN cut_8491
    DIRECTION INPUT ;
    USE SIGNAL ;
    PORT
      LAYER M4 ;
        RECT  0 20.112 0.084 20.136 ;
    END
  END cut_8491
  PIN cut_8492
    DIRECTION INPUT ;
    USE SIGNAL ;
    PORT
      LAYER M4 ;
        RECT  0 20.208 0.084 20.232 ;
    END
  END cut_8492
  PIN cut_8493
    DIRECTION INPUT ;
    USE SIGNAL ;
    PORT
      LAYER M4 ;
        RECT  0 20.304 0.084 20.328 ;
    END
  END cut_8493
  PIN cut_8494
    DIRECTION INPUT ;
    USE SIGNAL ;
    PORT
      LAYER M4 ;
        RECT  0 20.4 0.084 20.424 ;
    END
  END cut_8494
  PIN cut_8495
    DIRECTION INPUT ;
    USE SIGNAL ;
    PORT
      LAYER M4 ;
        RECT  0 20.496 0.084 20.52 ;
    END
  END cut_8495
  PIN cut_8496
    DIRECTION INPUT ;
    USE SIGNAL ;
    PORT
      LAYER M4 ;
        RECT  0 20.592 0.084 20.616 ;
    END
  END cut_8496
  PIN cut_8497
    DIRECTION INPUT ;
    USE SIGNAL ;
    PORT
      LAYER M4 ;
        RECT  0 20.688 0.084 20.712 ;
    END
  END cut_8497
  PIN cut_8498
    DIRECTION INPUT ;
    USE SIGNAL ;
    PORT
      LAYER M4 ;
        RECT  0 20.784 0.084 20.808 ;
    END
  END cut_8498
  PIN cut_8499
    DIRECTION INPUT ;
    USE SIGNAL ;
    PORT
      LAYER M4 ;
        RECT  0 20.88 0.084 20.904 ;
    END
  END cut_8499
  PIN cut_8500
    DIRECTION INPUT ;
    USE SIGNAL ;
    PORT
      LAYER M4 ;
        RECT  0 20.976 0.084 21 ;
    END
  END cut_8500
  PIN cut_8501
    DIRECTION INPUT ;
    USE SIGNAL ;
    PORT
      LAYER M4 ;
        RECT  0 21.072 0.084 21.096 ;
    END
  END cut_8501
  PIN cut_8502
    DIRECTION INPUT ;
    USE SIGNAL ;
    PORT
      LAYER M4 ;
        RECT  0 21.168 0.084 21.192 ;
    END
  END cut_8502
  PIN cut_8503
    DIRECTION INPUT ;
    USE SIGNAL ;
    PORT
      LAYER M4 ;
        RECT  0 21.264 0.084 21.288 ;
    END
  END cut_8503
  PIN cut_8504
    DIRECTION INPUT ;
    USE SIGNAL ;
    PORT
      LAYER M4 ;
        RECT  0 21.36 0.084 21.384 ;
    END
  END cut_8504
  PIN cut_8505
    DIRECTION INPUT ;
    USE SIGNAL ;
    PORT
      LAYER M4 ;
        RECT  0 21.456 0.084 21.48 ;
    END
  END cut_8505
  PIN cut_8506
    DIRECTION INPUT ;
    USE SIGNAL ;
    PORT
      LAYER M4 ;
        RECT  0 21.552 0.084 21.576 ;
    END
  END cut_8506
  PIN cut_8507
    DIRECTION INPUT ;
    USE SIGNAL ;
    PORT
      LAYER M4 ;
        RECT  0 21.648 0.084 21.672 ;
    END
  END cut_8507
  PIN cut_8508
    DIRECTION INPUT ;
    USE SIGNAL ;
    PORT
      LAYER M4 ;
        RECT  0 21.744 0.084 21.768 ;
    END
  END cut_8508
  PIN cut_8509
    DIRECTION INPUT ;
    USE SIGNAL ;
    PORT
      LAYER M4 ;
        RECT  0 21.84 0.084 21.864 ;
    END
  END cut_8509
  PIN cut_8510
    DIRECTION INPUT ;
    USE SIGNAL ;
    PORT
      LAYER M4 ;
        RECT  0 21.936 0.084 21.96 ;
    END
  END cut_8510
  PIN cut_8511
    DIRECTION INPUT ;
    USE SIGNAL ;
    PORT
      LAYER M4 ;
        RECT  0 31.248 0.084 31.272 ;
    END
  END cut_8511
  PIN cut_8512
    DIRECTION INPUT ;
    USE SIGNAL ;
    PORT
      LAYER M4 ;
        RECT  0 31.344 0.084 31.368 ;
    END
  END cut_8512
  PIN cut_8513
    DIRECTION INPUT ;
    USE SIGNAL ;
    PORT
      LAYER M4 ;
        RECT  0 31.44 0.084 31.464 ;
    END
  END cut_8513
  PIN cut_8514
    DIRECTION INPUT ;
    USE SIGNAL ;
    PORT
      LAYER M4 ;
        RECT  0 31.536 0.084 31.56 ;
    END
  END cut_8514
  PIN cut_8515
    DIRECTION INPUT ;
    USE SIGNAL ;
    PORT
      LAYER M4 ;
        RECT  0 31.632 0.084 31.656 ;
    END
  END cut_8515
  PIN cut_8516
    DIRECTION INPUT ;
    USE SIGNAL ;
    PORT
      LAYER M4 ;
        RECT  0 31.728 0.084 31.752 ;
    END
  END cut_8516
  PIN cut_8517
    DIRECTION INPUT ;
    USE SIGNAL ;
    PORT
      LAYER M4 ;
        RECT  0 31.824 0.084 31.848 ;
    END
  END cut_8517
  PIN cut_8518
    DIRECTION INPUT ;
    USE SIGNAL ;
    PORT
      LAYER M4 ;
        RECT  0 31.92 0.084 31.944 ;
    END
  END cut_8518
  PIN cut_8519
    DIRECTION INPUT ;
    USE SIGNAL ;
    PORT
      LAYER M4 ;
        RECT  0 32.016 0.084 32.04 ;
    END
  END cut_8519
  PIN cut_8520
    DIRECTION INPUT ;
    USE SIGNAL ;
    PORT
      LAYER M4 ;
        RECT  0 32.112 0.084 32.136 ;
    END
  END cut_8520
  PIN cut_8521
    DIRECTION INPUT ;
    USE SIGNAL ;
    PORT
      LAYER M4 ;
        RECT  0 32.208 0.084 32.232 ;
    END
  END cut_8521
  PIN cut_8522
    DIRECTION INPUT ;
    USE SIGNAL ;
    PORT
      LAYER M4 ;
        RECT  0 32.304 0.084 32.328 ;
    END
  END cut_8522
  PIN cut_8523
    DIRECTION INPUT ;
    USE SIGNAL ;
    PORT
      LAYER M4 ;
        RECT  0 32.4 0.084 32.424 ;
    END
  END cut_8523
  PIN cut_8524
    DIRECTION INPUT ;
    USE SIGNAL ;
    PORT
      LAYER M4 ;
        RECT  0 32.496 0.084 32.52 ;
    END
  END cut_8524
  PIN cut_8525
    DIRECTION INPUT ;
    USE SIGNAL ;
    PORT
      LAYER M4 ;
        RECT  0 32.592 0.084 32.616 ;
    END
  END cut_8525
  PIN cut_8526
    DIRECTION INPUT ;
    USE SIGNAL ;
    PORT
      LAYER M4 ;
        RECT  0 32.688 0.084 32.712 ;
    END
  END cut_8526
  PIN cut_8527
    DIRECTION INPUT ;
    USE SIGNAL ;
    PORT
      LAYER M4 ;
        RECT  0 32.784 0.084 32.808 ;
    END
  END cut_8527
  PIN cut_8528
    DIRECTION INPUT ;
    USE SIGNAL ;
    PORT
      LAYER M4 ;
        RECT  0 32.88 0.084 32.904 ;
    END
  END cut_8528
  PIN cut_8529
    DIRECTION INPUT ;
    USE SIGNAL ;
    PORT
      LAYER M4 ;
        RECT  0 32.976 0.084 33 ;
    END
  END cut_8529
  PIN cut_8530
    DIRECTION INPUT ;
    USE SIGNAL ;
    PORT
      LAYER M4 ;
        RECT  0 33.072 0.084 33.096 ;
    END
  END cut_8530
  PIN cut_8531
    DIRECTION INPUT ;
    USE SIGNAL ;
    PORT
      LAYER M4 ;
        RECT  0 33.168 0.084 33.192 ;
    END
  END cut_8531
  PIN cut_8532
    DIRECTION INPUT ;
    USE SIGNAL ;
    PORT
      LAYER M4 ;
        RECT  0 33.264 0.084 33.288 ;
    END
  END cut_8532
  PIN cut_8533
    DIRECTION INPUT ;
    USE SIGNAL ;
    PORT
      LAYER M4 ;
        RECT  0 33.36 0.084 33.384 ;
    END
  END cut_8533
  PIN cut_8534
    DIRECTION INPUT ;
    USE SIGNAL ;
    PORT
      LAYER M4 ;
        RECT  0 33.456 0.084 33.48 ;
    END
  END cut_8534
  PIN cut_8535
    DIRECTION INPUT ;
    USE SIGNAL ;
    PORT
      LAYER M4 ;
        RECT  0 33.552 0.084 33.576 ;
    END
  END cut_8535
  PIN cut_8536
    DIRECTION INPUT ;
    USE SIGNAL ;
    PORT
      LAYER M4 ;
        RECT  0 33.648 0.084 33.672 ;
    END
  END cut_8536
  PIN cut_8537
    DIRECTION INPUT ;
    USE SIGNAL ;
    PORT
      LAYER M4 ;
        RECT  0 33.744 0.084 33.768 ;
    END
  END cut_8537
  PIN cut_8538
    DIRECTION INPUT ;
    USE SIGNAL ;
    PORT
      LAYER M4 ;
        RECT  0 33.84 0.084 33.864 ;
    END
  END cut_8538
  PIN cut_8539
    DIRECTION INPUT ;
    USE SIGNAL ;
    PORT
      LAYER M4 ;
        RECT  0 33.936 0.084 33.96 ;
    END
  END cut_8539
  PIN cut_8690
    DIRECTION INPUT ;
    USE SIGNAL ;
    PORT
      LAYER M4 ;
        RECT  0 34.032 0.084 34.056 ;
    END
  END cut_8690
  PIN cut_8691
    DIRECTION INPUT ;
    USE SIGNAL ;
    PORT
      LAYER M4 ;
        RECT  0 34.128 0.084 34.152 ;
    END
  END cut_8691
  PIN cut_8694
    DIRECTION INPUT ;
    USE SIGNAL ;
    PORT
      LAYER M4 ;
        RECT  0 34.224 0.084 34.248 ;
    END
  END cut_8694
  PIN cut_8695
    DIRECTION INPUT ;
    USE SIGNAL ;
    PORT
      LAYER M4 ;
        RECT  0 38.16 0.084 38.184 ;
    END
  END cut_8695
  PIN cut_8748
    DIRECTION OUTPUT ;
    USE SIGNAL ;
    PORT
      LAYER M4 ;
        RECT  73.356 38.352 73.44 38.376 ;
    END
  END cut_8748
  PIN cut_8749
    DIRECTION OUTPUT ;
    USE SIGNAL ;
    PORT
      LAYER M4 ;
        RECT  73.356 38.448 73.44 38.472 ;
    END
  END cut_8749
  PIN cut_8750
    DIRECTION OUTPUT ;
    USE SIGNAL ;
    PORT
      LAYER M4 ;
        RECT  73.356 38.544 73.44 38.568 ;
    END
  END cut_8750
  PIN cut_8752
    DIRECTION INPUT ;
    USE SIGNAL ;
    PORT
      LAYER M4 ;
        RECT  0 38.256 0.084 38.28 ;
    END
  END cut_8752
  PIN cut_8753
    DIRECTION INPUT ;
    USE SIGNAL ;
    PORT
      LAYER M4 ;
        RECT  0 38.352 0.084 38.376 ;
    END
  END cut_8753
  PIN cut_8754
    DIRECTION INPUT ;
    USE SIGNAL ;
    PORT
      LAYER M4 ;
        RECT  0 38.448 0.084 38.472 ;
    END
  END cut_8754
  PIN cut_8755
    DIRECTION INPUT ;
    USE SIGNAL ;
    PORT
      LAYER M4 ;
        RECT  0 38.544 0.084 38.568 ;
    END
  END cut_8755
  PIN cut_8756
    DIRECTION INPUT ;
    USE SIGNAL ;
    PORT
      LAYER M4 ;
        RECT  0 38.64 0.084 38.664 ;
    END
  END cut_8756
  PIN cut_8757
    DIRECTION INPUT ;
    USE SIGNAL ;
    PORT
      LAYER M4 ;
        RECT  0 38.736 0.084 38.76 ;
    END
  END cut_8757
  PIN cut_8758
    DIRECTION INPUT ;
    USE SIGNAL ;
    PORT
      LAYER M4 ;
        RECT  0 38.832 0.084 38.856 ;
    END
  END cut_8758
  PIN cut_8759
    DIRECTION INPUT ;
    USE SIGNAL ;
    PORT
      LAYER M4 ;
        RECT  0 38.928 0.084 38.952 ;
    END
  END cut_8759
  PIN cut_8760
    DIRECTION INPUT ;
    USE SIGNAL ;
    PORT
      LAYER M4 ;
        RECT  0 39.024 0.084 39.048 ;
    END
  END cut_8760
  PIN cut_8761
    DIRECTION INPUT ;
    USE SIGNAL ;
    PORT
      LAYER M4 ;
        RECT  0 39.12 0.084 39.144 ;
    END
  END cut_8761
  PIN cut_8762
    DIRECTION INPUT ;
    USE SIGNAL ;
    PORT
      LAYER M4 ;
        RECT  0 39.216 0.084 39.24 ;
    END
  END cut_8762
  PIN cut_8763
    DIRECTION INPUT ;
    USE SIGNAL ;
    PORT
      LAYER M4 ;
        RECT  0 39.312 0.084 39.336 ;
    END
  END cut_8763
  PIN cut_8764
    DIRECTION INPUT ;
    USE SIGNAL ;
    PORT
      LAYER M4 ;
        RECT  0 39.408 0.084 39.432 ;
    END
  END cut_8764
  PIN cut_8765
    DIRECTION INPUT ;
    USE SIGNAL ;
    PORT
      LAYER M4 ;
        RECT  0 39.504 0.084 39.528 ;
    END
  END cut_8765
  PIN cut_8766
    DIRECTION INPUT ;
    USE SIGNAL ;
    PORT
      LAYER M4 ;
        RECT  0 39.6 0.084 39.624 ;
    END
  END cut_8766
  PIN cut_8767
    DIRECTION INPUT ;
    USE SIGNAL ;
    PORT
      LAYER M4 ;
        RECT  0 39.696 0.084 39.72 ;
    END
  END cut_8767
  PIN cut_8768
    DIRECTION INPUT ;
    USE SIGNAL ;
    PORT
      LAYER M4 ;
        RECT  0 39.792 0.084 39.816 ;
    END
  END cut_8768
  PIN cut_8769
    DIRECTION INPUT ;
    USE SIGNAL ;
    PORT
      LAYER M4 ;
        RECT  0 39.888 0.084 39.912 ;
    END
  END cut_8769
  PIN cut_8770
    DIRECTION INPUT ;
    USE SIGNAL ;
    PORT
      LAYER M4 ;
        RECT  0 39.984 0.084 40.008 ;
    END
  END cut_8770
  PIN cut_8771
    DIRECTION INPUT ;
    USE SIGNAL ;
    PORT
      LAYER M4 ;
        RECT  0 40.08 0.084 40.104 ;
    END
  END cut_8771
  PIN cut_8772
    DIRECTION INPUT ;
    USE SIGNAL ;
    PORT
      LAYER M4 ;
        RECT  0 40.176 0.084 40.2 ;
    END
  END cut_8772
  PIN cut_8773
    DIRECTION INPUT ;
    USE SIGNAL ;
    PORT
      LAYER M4 ;
        RECT  0 40.272 0.084 40.296 ;
    END
  END cut_8773
  PIN cut_8774
    DIRECTION INPUT ;
    USE SIGNAL ;
    PORT
      LAYER M4 ;
        RECT  0 40.368 0.084 40.392 ;
    END
  END cut_8774
  PIN cut_8775
    DIRECTION INPUT ;
    USE SIGNAL ;
    PORT
      LAYER M4 ;
        RECT  0 40.464 0.084 40.488 ;
    END
  END cut_8775
  PIN cut_8776
    DIRECTION INPUT ;
    USE SIGNAL ;
    PORT
      LAYER M4 ;
        RECT  0 40.56 0.084 40.584 ;
    END
  END cut_8776
  PIN cut_8777
    DIRECTION INPUT ;
    USE SIGNAL ;
    PORT
      LAYER M4 ;
        RECT  0 40.656 0.084 40.68 ;
    END
  END cut_8777
  PIN cut_8778
    DIRECTION INPUT ;
    USE SIGNAL ;
    PORT
      LAYER M4 ;
        RECT  0 40.752 0.084 40.776 ;
    END
  END cut_8778
  PIN cut_8779
    DIRECTION INPUT ;
    USE SIGNAL ;
    PORT
      LAYER M4 ;
        RECT  0 40.848 0.084 40.872 ;
    END
  END cut_8779
  PIN cut_8780
    DIRECTION INPUT ;
    USE SIGNAL ;
    PORT
      LAYER M4 ;
        RECT  0 40.944 0.084 40.968 ;
    END
  END cut_8780
  PIN cut_8781
    DIRECTION INPUT ;
    USE SIGNAL ;
    PORT
      LAYER M4 ;
        RECT  0 41.04 0.084 41.064 ;
    END
  END cut_8781
  PIN cut_8782
    DIRECTION INPUT ;
    USE SIGNAL ;
    PORT
      LAYER M4 ;
        RECT  0 41.136 0.084 41.16 ;
    END
  END cut_8782
  PIN cut_8783
    DIRECTION INPUT ;
    USE SIGNAL ;
    PORT
      LAYER M4 ;
        RECT  0 41.232 0.084 41.256 ;
    END
  END cut_8783
  PIN cut_8784
    DIRECTION INPUT ;
    USE SIGNAL ;
    PORT
      LAYER M4 ;
        RECT  0 41.328 0.084 41.352 ;
    END
  END cut_8784
  PIN cut_8785
    DIRECTION INPUT ;
    USE SIGNAL ;
    PORT
      LAYER M4 ;
        RECT  0 41.424 0.084 41.448 ;
    END
  END cut_8785
  PIN cut_8786
    DIRECTION INPUT ;
    USE SIGNAL ;
    PORT
      LAYER M4 ;
        RECT  0 41.52 0.084 41.544 ;
    END
  END cut_8786
  PIN cut_8787
    DIRECTION INPUT ;
    USE SIGNAL ;
    PORT
      LAYER M4 ;
        RECT  0 41.616 0.084 41.64 ;
    END
  END cut_8787
  PIN cut_8788
    DIRECTION INPUT ;
    USE SIGNAL ;
    PORT
      LAYER M4 ;
        RECT  0 41.712 0.084 41.736 ;
    END
  END cut_8788
  PIN cut_8789
    DIRECTION INPUT ;
    USE SIGNAL ;
    PORT
      LAYER M4 ;
        RECT  0 41.808 0.084 41.832 ;
    END
  END cut_8789
  PIN cut_8790
    DIRECTION INPUT ;
    USE SIGNAL ;
    PORT
      LAYER M4 ;
        RECT  0 41.904 0.084 41.928 ;
    END
  END cut_8790
  PIN cut_8791
    DIRECTION INPUT ;
    USE SIGNAL ;
    PORT
      LAYER M4 ;
        RECT  0 42 0.084 42.024 ;
    END
  END cut_8791
  PIN cut_8792
    DIRECTION INPUT ;
    USE SIGNAL ;
    PORT
      LAYER M4 ;
        RECT  0 42.096 0.084 42.12 ;
    END
  END cut_8792
  PIN cut_8793
    DIRECTION INPUT ;
    USE SIGNAL ;
    PORT
      LAYER M4 ;
        RECT  0 42.192 0.084 42.216 ;
    END
  END cut_8793
  PIN cut_8794
    DIRECTION INPUT ;
    USE SIGNAL ;
    PORT
      LAYER M4 ;
        RECT  0 42.288 0.084 42.312 ;
    END
  END cut_8794
  PIN cut_8795
    DIRECTION INPUT ;
    USE SIGNAL ;
    PORT
      LAYER M4 ;
        RECT  0 42.384 0.084 42.408 ;
    END
  END cut_8795
  PIN cut_8796
    DIRECTION INPUT ;
    USE SIGNAL ;
    PORT
      LAYER M4 ;
        RECT  0 42.48 0.084 42.504 ;
    END
  END cut_8796
  PIN cut_8797
    DIRECTION INPUT ;
    USE SIGNAL ;
    PORT
      LAYER M4 ;
        RECT  0 42.576 0.084 42.6 ;
    END
  END cut_8797
  PIN cut_8798
    DIRECTION INPUT ;
    USE SIGNAL ;
    PORT
      LAYER M4 ;
        RECT  0 42.672 0.084 42.696 ;
    END
  END cut_8798
  PIN cut_8799
    DIRECTION INPUT ;
    USE SIGNAL ;
    PORT
      LAYER M4 ;
        RECT  0 42.768 0.084 42.792 ;
    END
  END cut_8799
  PIN cut_8800
    DIRECTION INPUT ;
    USE SIGNAL ;
    PORT
      LAYER M4 ;
        RECT  0 42.864 0.084 42.888 ;
    END
  END cut_8800
  PIN cut_8801
    DIRECTION INPUT ;
    USE SIGNAL ;
    PORT
      LAYER M4 ;
        RECT  0 42.96 0.084 42.984 ;
    END
  END cut_8801
  PIN cut_8802
    DIRECTION INPUT ;
    USE SIGNAL ;
    PORT
      LAYER M4 ;
        RECT  0 43.056 0.084 43.08 ;
    END
  END cut_8802
  PIN cut_8803
    DIRECTION INPUT ;
    USE SIGNAL ;
    PORT
      LAYER M4 ;
        RECT  0 43.152 0.084 43.176 ;
    END
  END cut_8803
  PIN cut_8804
    DIRECTION INPUT ;
    USE SIGNAL ;
    PORT
      LAYER M4 ;
        RECT  0 43.248 0.084 43.272 ;
    END
  END cut_8804
  PIN cut_8805
    DIRECTION INPUT ;
    USE SIGNAL ;
    PORT
      LAYER M4 ;
        RECT  0 43.344 0.084 43.368 ;
    END
  END cut_8805
  PIN cut_8806
    DIRECTION INPUT ;
    USE SIGNAL ;
    PORT
      LAYER M4 ;
        RECT  0 43.44 0.084 43.464 ;
    END
  END cut_8806
  PIN cut_8807
    DIRECTION INPUT ;
    USE SIGNAL ;
    PORT
      LAYER M4 ;
        RECT  0 43.536 0.084 43.56 ;
    END
  END cut_8807
  PIN cut_8808
    DIRECTION INPUT ;
    USE SIGNAL ;
    PORT
      LAYER M4 ;
        RECT  0 43.632 0.084 43.656 ;
    END
  END cut_8808
  PIN cut_8809
    DIRECTION INPUT ;
    USE SIGNAL ;
    PORT
      LAYER M4 ;
        RECT  0 43.728 0.084 43.752 ;
    END
  END cut_8809
  PIN cut_8810
    DIRECTION INPUT ;
    USE SIGNAL ;
    PORT
      LAYER M4 ;
        RECT  0 43.824 0.084 43.848 ;
    END
  END cut_8810
  PIN cut_8811
    DIRECTION INPUT ;
    USE SIGNAL ;
    PORT
      LAYER M4 ;
        RECT  0 43.92 0.084 43.944 ;
    END
  END cut_8811
  PIN cut_8812
    DIRECTION INPUT ;
    USE SIGNAL ;
    PORT
      LAYER M4 ;
        RECT  0 44.016 0.084 44.04 ;
    END
  END cut_8812
  PIN cut_8813
    DIRECTION INPUT ;
    USE SIGNAL ;
    PORT
      LAYER M4 ;
        RECT  0 44.112 0.084 44.136 ;
    END
  END cut_8813
  PIN cut_8814
    DIRECTION INPUT ;
    USE SIGNAL ;
    PORT
      LAYER M4 ;
        RECT  0 44.208 0.084 44.232 ;
    END
  END cut_8814
  PIN cut_8815
    DIRECTION INPUT ;
    USE SIGNAL ;
    PORT
      LAYER M4 ;
        RECT  0 44.304 0.084 44.328 ;
    END
  END cut_8815
  PIN cut_8816
    DIRECTION INPUT ;
    USE SIGNAL ;
    PORT
      LAYER M4 ;
        RECT  0 44.4 0.084 44.424 ;
    END
  END cut_8816
  PIN cut_8817
    DIRECTION INPUT ;
    USE SIGNAL ;
    PORT
      LAYER M4 ;
        RECT  0 44.496 0.084 44.52 ;
    END
  END cut_8817
  PIN cut_8818
    DIRECTION INPUT ;
    USE SIGNAL ;
    PORT
      LAYER M4 ;
        RECT  0 44.592 0.084 44.616 ;
    END
  END cut_8818
  PIN cut_8819
    DIRECTION INPUT ;
    USE SIGNAL ;
    PORT
      LAYER M4 ;
        RECT  0 44.688 0.084 44.712 ;
    END
  END cut_8819
  PIN cut_8820
    DIRECTION INPUT ;
    USE SIGNAL ;
    PORT
      LAYER M4 ;
        RECT  0 44.784 0.084 44.808 ;
    END
  END cut_8820
  PIN cut_8821
    DIRECTION INPUT ;
    USE SIGNAL ;
    PORT
      LAYER M4 ;
        RECT  0 44.88 0.084 44.904 ;
    END
  END cut_8821
  PIN cut_8822
    DIRECTION INPUT ;
    USE SIGNAL ;
    PORT
      LAYER M4 ;
        RECT  0 44.976 0.084 45 ;
    END
  END cut_8822
  PIN cut_8823
    DIRECTION INPUT ;
    USE SIGNAL ;
    PORT
      LAYER M4 ;
        RECT  0 45.072 0.084 45.096 ;
    END
  END cut_8823
  PIN cut_8824
    DIRECTION INPUT ;
    USE SIGNAL ;
    PORT
      LAYER M4 ;
        RECT  0 45.168 0.084 45.192 ;
    END
  END cut_8824
  PIN cut_8825
    DIRECTION INPUT ;
    USE SIGNAL ;
    PORT
      LAYER M4 ;
        RECT  0 45.264 0.084 45.288 ;
    END
  END cut_8825
  PIN cut_8826
    DIRECTION INPUT ;
    USE SIGNAL ;
    PORT
      LAYER M4 ;
        RECT  0 45.36 0.084 45.384 ;
    END
  END cut_8826
  PIN cut_8827
    DIRECTION INPUT ;
    USE SIGNAL ;
    PORT
      LAYER M4 ;
        RECT  0 45.456 0.084 45.48 ;
    END
  END cut_8827
  PIN cut_8828
    DIRECTION INPUT ;
    USE SIGNAL ;
    PORT
      LAYER M4 ;
        RECT  0 45.552 0.084 45.576 ;
    END
  END cut_8828
  PIN cut_8829
    DIRECTION INPUT ;
    USE SIGNAL ;
    PORT
      LAYER M4 ;
        RECT  0 45.648 0.084 45.672 ;
    END
  END cut_8829
  PIN cut_8830
    DIRECTION INPUT ;
    USE SIGNAL ;
    PORT
      LAYER M4 ;
        RECT  0 45.744 0.084 45.768 ;
    END
  END cut_8830
  PIN cut_8831
    DIRECTION INPUT ;
    USE SIGNAL ;
    PORT
      LAYER M4 ;
        RECT  0 45.84 0.084 45.864 ;
    END
  END cut_8831
  PIN cut_8832
    DIRECTION INPUT ;
    USE SIGNAL ;
    PORT
      LAYER M4 ;
        RECT  0 45.936 0.084 45.96 ;
    END
  END cut_8832
  PIN cut_8833
    DIRECTION INPUT ;
    USE SIGNAL ;
    PORT
      LAYER M4 ;
        RECT  0 46.032 0.084 46.056 ;
    END
  END cut_8833
  PIN cut_8834
    DIRECTION INPUT ;
    USE SIGNAL ;
    PORT
      LAYER M4 ;
        RECT  0 46.128 0.084 46.152 ;
    END
  END cut_8834
  PIN cut_8835
    DIRECTION INPUT ;
    USE SIGNAL ;
    PORT
      LAYER M4 ;
        RECT  0 46.224 0.084 46.248 ;
    END
  END cut_8835
  PIN cut_8836
    DIRECTION INPUT ;
    USE SIGNAL ;
    PORT
      LAYER M4 ;
        RECT  0 46.32 0.084 46.344 ;
    END
  END cut_8836
  PIN cut_8837
    DIRECTION INPUT ;
    USE SIGNAL ;
    PORT
      LAYER M4 ;
        RECT  0 46.416 0.084 46.44 ;
    END
  END cut_8837
  PIN cut_8838
    DIRECTION INPUT ;
    USE SIGNAL ;
    PORT
      LAYER M4 ;
        RECT  0 46.512 0.084 46.536 ;
    END
  END cut_8838
  PIN cut_8839
    DIRECTION INPUT ;
    USE SIGNAL ;
    PORT
      LAYER M4 ;
        RECT  0 46.608 0.084 46.632 ;
    END
  END cut_8839
  PIN cut_8840
    DIRECTION INPUT ;
    USE SIGNAL ;
    PORT
      LAYER M4 ;
        RECT  0 46.704 0.084 46.728 ;
    END
  END cut_8840
  PIN cut_8841
    DIRECTION INPUT ;
    USE SIGNAL ;
    PORT
      LAYER M4 ;
        RECT  0 46.8 0.084 46.824 ;
    END
  END cut_8841
  PIN cut_8842
    DIRECTION INPUT ;
    USE SIGNAL ;
    PORT
      LAYER M4 ;
        RECT  0 46.896 0.084 46.92 ;
    END
  END cut_8842
  PIN cut_8843
    DIRECTION INPUT ;
    USE SIGNAL ;
    PORT
      LAYER M4 ;
        RECT  0 46.992 0.084 47.016 ;
    END
  END cut_8843
  PIN cut_8844
    DIRECTION INPUT ;
    USE SIGNAL ;
    PORT
      LAYER M4 ;
        RECT  0 47.088 0.084 47.112 ;
    END
  END cut_8844
  PIN cut_8845
    DIRECTION INPUT ;
    USE SIGNAL ;
    PORT
      LAYER M4 ;
        RECT  0 47.184 0.084 47.208 ;
    END
  END cut_8845
  PIN cut_8846
    DIRECTION INPUT ;
    USE SIGNAL ;
    PORT
      LAYER M4 ;
        RECT  0 47.28 0.084 47.304 ;
    END
  END cut_8846
  PIN cut_8847
    DIRECTION INPUT ;
    USE SIGNAL ;
    PORT
      LAYER M4 ;
        RECT  0 53.424 0.084 53.448 ;
    END
    PORT
      LAYER M4 ;
        RECT  0.06 53.424 2.408 53.448 ;
    END
  END cut_8847
  PIN cut_8857
    DIRECTION OUTPUT ;
    USE SIGNAL ;
    PORT
      LAYER M4 ;
        RECT  73.356 38.64 73.44 38.664 ;
    END
  END cut_8857
  PIN cut_8858
    DIRECTION OUTPUT ;
    USE SIGNAL ;
    PORT
      LAYER M4 ;
        RECT  73.356 38.736 73.44 38.76 ;
    END
  END cut_8858
  PIN cut_8870
    DIRECTION OUTPUT ;
    USE SIGNAL ;
    PORT
      LAYER M4 ;
        RECT  73.356 38.832 73.44 38.856 ;
    END
  END cut_8870
  PIN cut_9
    DIRECTION INPUT ;
    USE SIGNAL ;
    PORT
      LAYER M4 ;
        RECT  0 28.56 0.084 28.584 ;
    END
  END cut_9
  PIN VDD
    DIRECTION INOUT ;
    USE POWER ;
    PORT
      LAYER M5 ;
        RECT  67.392 2.151 67.512 71.289 ;
        RECT  61.992 2.151 62.112 71.289 ;
        RECT  56.592 2.151 56.712 71.289 ;
        RECT  51.192 2.151 51.312 71.289 ;
        RECT  45.792 2.151 45.912 71.289 ;
        RECT  40.392 2.151 40.512 71.289 ;
        RECT  34.992 2.151 35.112 71.289 ;
        RECT  29.592 2.151 29.712 71.289 ;
        RECT  24.192 2.151 24.312 71.289 ;
        RECT  18.792 2.151 18.912 71.289 ;
        RECT  13.392 2.151 13.512 71.289 ;
        RECT  7.992 2.151 8.112 71.289 ;
        RECT  2.592 2.151 2.712 71.289 ;
    END
  END VDD
  PIN VSS
    DIRECTION INOUT ;
    USE GROUND ;
    PORT
      LAYER M5 ;
        RECT  67.2 2.137 67.32 71.303 ;
        RECT  61.8 2.137 61.92 71.303 ;
        RECT  56.4 2.137 56.52 71.303 ;
        RECT  51 2.137 51.12 71.303 ;
        RECT  45.6 2.137 45.72 71.303 ;
        RECT  40.2 2.137 40.32 71.303 ;
        RECT  34.8 2.137 34.92 71.303 ;
        RECT  29.4 2.137 29.52 71.303 ;
        RECT  24 2.137 24.12 71.303 ;
        RECT  18.6 2.137 18.72 71.303 ;
        RECT  13.2 2.137 13.32 71.303 ;
        RECT  7.8 2.137 7.92 71.303 ;
        RECT  2.4 2.137 2.52 71.303 ;
    END
  END VSS
  # OT_OBS_CLOSED layer=M5 d_um=1.536 added=137
  OBS
    LAYER RVTN ;
     RECT  2.16 2.16 71.28 2.295 ;
     RECT  2.16 2.565 71.28 2.835 ;
     RECT  2.16 3.105 71.28 3.375 ;
     RECT  2.16 3.645 71.28 3.915 ;
     RECT  2.16 4.185 71.28 4.455 ;
     RECT  2.16 4.725 71.28 4.995 ;
     RECT  2.16 5.265 71.28 5.535 ;
     RECT  2.16 5.805 71.28 6.075 ;
     RECT  2.16 6.345 71.28 6.615 ;
     RECT  2.16 6.885 71.28 7.155 ;
     RECT  2.16 7.425 71.28 7.695 ;
     RECT  2.16 7.965 71.28 8.235 ;
     RECT  2.16 8.505 71.28 8.775 ;
     RECT  2.16 9.045 71.28 9.315 ;
     RECT  2.16 9.585 71.28 9.855 ;
     RECT  2.16 10.125 71.28 10.395 ;
     RECT  2.16 10.665 71.28 10.935 ;
     RECT  2.16 11.205 71.28 11.475 ;
     RECT  2.16 11.745 71.28 12.015 ;
     RECT  2.16 12.285 71.28 12.555 ;
     RECT  2.16 12.825 71.28 13.095 ;
     RECT  2.16 13.365 71.28 13.635 ;
     RECT  2.16 13.905 71.28 14.175 ;
     RECT  2.16 14.445 71.28 14.715 ;
     RECT  2.16 14.985 71.28 15.255 ;
     RECT  2.16 15.525 71.28 15.795 ;
     RECT  2.16 16.065 71.28 16.335 ;
     RECT  2.16 16.605 71.28 16.875 ;
     RECT  2.16 17.145 71.28 17.415 ;
     RECT  2.16 17.685 71.28 17.955 ;
     RECT  2.16 18.225 71.28 18.495 ;
     RECT  2.16 18.765 71.28 19.035 ;
     RECT  2.16 19.305 71.28 19.575 ;
     RECT  2.16 19.845 71.28 20.115 ;
     RECT  2.16 20.385 71.28 20.655 ;
     RECT  2.16 20.925 71.28 21.195 ;
     RECT  2.16 21.465 71.28 21.735 ;
     RECT  2.16 22.005 71.28 22.275 ;
     RECT  2.16 22.545 71.28 22.815 ;
     RECT  2.16 23.085 71.28 23.355 ;
     RECT  2.16 23.625 71.28 23.895 ;
     RECT  2.16 24.165 71.28 24.435 ;
     RECT  2.16 24.705 71.28 24.975 ;
     RECT  2.16 25.245 71.28 25.515 ;
     RECT  2.16 25.785 71.28 26.055 ;
     RECT  2.16 26.325 71.28 26.595 ;
     RECT  2.16 26.865 71.28 27.135 ;
     RECT  2.16 27.405 71.28 27.675 ;
     RECT  2.16 27.945 71.28 28.215 ;
     RECT  2.16 28.485 71.28 28.755 ;
     RECT  2.16 29.025 71.28 29.295 ;
     RECT  2.16 29.565 71.28 29.835 ;
     RECT  2.16 30.105 71.28 30.375 ;
     RECT  2.16 30.645 71.28 30.915 ;
     RECT  2.16 31.185 71.28 31.455 ;
     RECT  2.16 31.725 71.28 31.995 ;
     RECT  2.16 32.265 71.28 32.535 ;
     RECT  2.16 32.805 71.28 33.075 ;
     RECT  2.16 33.345 71.28 33.615 ;
     RECT  2.16 33.885 71.28 34.155 ;
     RECT  2.16 34.425 71.28 34.695 ;
     RECT  2.16 34.965 71.28 35.235 ;
     RECT  2.16 35.505 71.28 35.775 ;
     RECT  2.16 36.045 71.28 36.315 ;
     RECT  2.16 36.585 71.28 36.855 ;
     RECT  2.16 37.125 71.28 37.395 ;
     RECT  2.16 37.665 71.28 37.935 ;
     RECT  2.16 38.205 71.28 38.475 ;
     RECT  2.16 38.745 71.28 39.015 ;
     RECT  2.16 39.285 71.28 39.555 ;
     RECT  2.16 39.825 71.28 40.095 ;
     RECT  2.16 40.365 71.28 40.635 ;
     RECT  2.16 40.905 71.28 41.175 ;
     RECT  2.16 41.445 71.28 41.715 ;
     RECT  2.16 41.985 71.28 42.255 ;
     RECT  2.16 42.525 71.28 42.795 ;
     RECT  2.16 43.065 71.28 43.335 ;
     RECT  2.16 43.605 71.28 43.875 ;
     RECT  2.16 44.145 71.28 44.415 ;
     RECT  2.16 44.685 71.28 44.955 ;
     RECT  2.16 45.225 71.28 45.495 ;
     RECT  2.16 45.765 71.28 46.035 ;
     RECT  2.16 46.305 71.28 46.575 ;
     RECT  2.16 46.845 71.28 47.115 ;
     RECT  2.16 47.385 71.28 47.655 ;
     RECT  2.16 47.925 71.28 48.195 ;
     RECT  2.16 48.465 71.28 48.735 ;
     RECT  2.16 49.005 71.28 49.275 ;
     RECT  2.16 49.545 71.28 49.815 ;
     RECT  2.16 50.085 71.28 50.355 ;
     RECT  2.16 50.625 71.28 50.895 ;
     RECT  2.16 51.165 71.28 51.435 ;
     RECT  2.16 51.705 71.28 51.975 ;
     RECT  2.16 52.245 71.28 52.515 ;
     RECT  2.16 52.785 71.28 53.055 ;
     RECT  2.16 53.325 71.28 53.595 ;
     RECT  2.16 53.865 71.28 54.135 ;
     RECT  2.16 54.405 71.28 54.675 ;
     RECT  2.16 54.945 71.28 55.215 ;
     RECT  2.16 55.485 71.28 55.755 ;
     RECT  2.16 56.025 71.28 56.295 ;
     RECT  2.16 56.565 71.28 56.835 ;
     RECT  2.16 57.105 71.28 57.375 ;
     RECT  2.16 57.645 71.28 57.915 ;
     RECT  2.16 58.185 71.28 58.455 ;
     RECT  2.16 58.725 71.28 58.995 ;
     RECT  2.16 59.265 71.28 59.535 ;
     RECT  2.16 59.805 71.28 60.075 ;
     RECT  2.16 60.345 71.28 60.615 ;
     RECT  2.16 60.885 71.28 61.155 ;
     RECT  2.16 61.425 71.28 61.695 ;
     RECT  2.16 61.965 71.28 62.235 ;
     RECT  2.16 62.505 71.28 62.775 ;
     RECT  2.16 63.045 71.28 63.315 ;
     RECT  2.16 63.585 71.28 63.855 ;
     RECT  2.16 64.125 71.28 64.395 ;
     RECT  2.16 64.665 71.28 64.935 ;
     RECT  2.16 65.205 71.28 65.475 ;
     RECT  2.16 65.745 71.28 66.015 ;
     RECT  2.16 66.285 71.28 66.555 ;
     RECT  2.16 66.825 71.28 67.095 ;
     RECT  2.16 67.365 71.28 67.635 ;
     RECT  2.16 67.905 71.28 68.175 ;
     RECT  2.16 68.445 71.28 68.715 ;
     RECT  2.16 68.985 71.28 69.255 ;
     RECT  2.16 69.525 71.28 69.795 ;
     RECT  2.16 70.065 71.28 70.335 ;
     RECT  2.16 70.605 71.28 70.875 ;
     RECT  2.16 71.145 71.28 71.28 ;
    LAYER RVTP ;
     RECT  2.16 2.295 71.28 2.565 ;
     RECT  2.16 2.835 71.28 3.105 ;
     RECT  2.16 3.375 71.28 3.645 ;
     RECT  2.16 3.915 71.28 4.185 ;
     RECT  2.16 4.455 71.28 4.725 ;
     RECT  2.16 4.995 71.28 5.265 ;
     RECT  2.16 5.535 71.28 5.805 ;
     RECT  2.16 6.075 71.28 6.345 ;
     RECT  2.16 6.615 71.28 6.885 ;
     RECT  2.16 7.155 71.28 7.425 ;
     RECT  2.16 7.695 71.28 7.965 ;
     RECT  2.16 8.235 71.28 8.505 ;
     RECT  2.16 8.775 71.28 9.045 ;
     RECT  2.16 9.315 71.28 9.585 ;
     RECT  2.16 9.855 71.28 10.125 ;
     RECT  2.16 10.395 71.28 10.665 ;
     RECT  2.16 10.935 71.28 11.205 ;
     RECT  2.16 11.475 71.28 11.745 ;
     RECT  2.16 12.015 71.28 12.285 ;
     RECT  2.16 12.555 71.28 12.825 ;
     RECT  2.16 13.095 71.28 13.365 ;
     RECT  2.16 13.635 71.28 13.905 ;
     RECT  2.16 14.175 71.28 14.445 ;
     RECT  2.16 14.715 71.28 14.985 ;
     RECT  2.16 15.255 71.28 15.525 ;
     RECT  2.16 15.795 71.28 16.065 ;
     RECT  2.16 16.335 71.28 16.605 ;
     RECT  2.16 16.875 71.28 17.145 ;
     RECT  2.16 17.415 71.28 17.685 ;
     RECT  2.16 17.955 71.28 18.225 ;
     RECT  2.16 18.495 71.28 18.765 ;
     RECT  2.16 19.035 71.28 19.305 ;
     RECT  2.16 19.575 71.28 19.845 ;
     RECT  2.16 20.115 71.28 20.385 ;
     RECT  2.16 20.655 71.28 20.925 ;
     RECT  2.16 21.195 71.28 21.465 ;
     RECT  2.16 21.735 71.28 22.005 ;
     RECT  2.16 22.275 71.28 22.545 ;
     RECT  2.16 22.815 71.28 23.085 ;
     RECT  2.16 23.355 71.28 23.625 ;
     RECT  2.16 23.895 71.28 24.165 ;
     RECT  2.16 24.435 71.28 24.705 ;
     RECT  2.16 24.975 71.28 25.245 ;
     RECT  2.16 25.515 71.28 25.785 ;
     RECT  2.16 26.055 71.28 26.325 ;
     RECT  2.16 26.595 71.28 26.865 ;
     RECT  2.16 27.135 71.28 27.405 ;
     RECT  2.16 27.675 71.28 27.945 ;
     RECT  2.16 28.215 71.28 28.485 ;
     RECT  2.16 28.755 71.28 29.025 ;
     RECT  2.16 29.295 71.28 29.565 ;
     RECT  2.16 29.835 71.28 30.105 ;
     RECT  2.16 30.375 71.28 30.645 ;
     RECT  2.16 30.915 71.28 31.185 ;
     RECT  2.16 31.455 71.28 31.725 ;
     RECT  2.16 31.995 71.28 32.265 ;
     RECT  2.16 32.535 71.28 32.805 ;
     RECT  2.16 33.075 71.28 33.345 ;
     RECT  2.16 33.615 71.28 33.885 ;
     RECT  2.16 34.155 71.28 34.425 ;
     RECT  2.16 34.695 71.28 34.965 ;
     RECT  2.16 35.235 71.28 35.505 ;
     RECT  2.16 35.775 71.28 36.045 ;
     RECT  2.16 36.315 71.28 36.585 ;
     RECT  2.16 36.855 71.28 37.125 ;
     RECT  2.16 37.395 71.28 37.665 ;
     RECT  2.16 37.935 71.28 38.205 ;
     RECT  2.16 38.475 71.28 38.745 ;
     RECT  2.16 39.015 71.28 39.285 ;
     RECT  2.16 39.555 71.28 39.825 ;
     RECT  2.16 40.095 71.28 40.365 ;
     RECT  2.16 40.635 71.28 40.905 ;
     RECT  2.16 41.175 71.28 41.445 ;
     RECT  2.16 41.715 71.28 41.985 ;
     RECT  2.16 42.255 71.28 42.525 ;
     RECT  2.16 42.795 71.28 43.065 ;
     RECT  2.16 43.335 71.28 43.605 ;
     RECT  2.16 43.875 71.28 44.145 ;
     RECT  2.16 44.415 71.28 44.685 ;
     RECT  2.16 44.955 71.28 45.225 ;
     RECT  2.16 45.495 71.28 45.765 ;
     RECT  2.16 46.035 71.28 46.305 ;
     RECT  2.16 46.575 71.28 46.845 ;
     RECT  2.16 47.115 71.28 47.385 ;
     RECT  2.16 47.655 71.28 47.925 ;
     RECT  2.16 48.195 71.28 48.465 ;
     RECT  2.16 48.735 71.28 49.005 ;
     RECT  2.16 49.275 71.28 49.545 ;
     RECT  2.16 49.815 71.28 50.085 ;
     RECT  2.16 50.355 71.28 50.625 ;
     RECT  2.16 50.895 71.28 51.165 ;
     RECT  2.16 51.435 71.28 51.705 ;
     RECT  2.16 51.975 71.28 52.245 ;
     RECT  2.16 52.515 71.28 52.785 ;
     RECT  2.16 53.055 71.28 53.325 ;
     RECT  2.16 53.595 71.28 53.865 ;
     RECT  2.16 54.135 71.28 54.405 ;
     RECT  2.16 54.675 71.28 54.945 ;
     RECT  2.16 55.215 71.28 55.485 ;
     RECT  2.16 55.755 71.28 56.025 ;
     RECT  2.16 56.295 71.28 56.565 ;
     RECT  2.16 56.835 71.28 57.105 ;
     RECT  2.16 57.375 71.28 57.645 ;
     RECT  2.16 57.915 71.28 58.185 ;
     RECT  2.16 58.455 71.28 58.725 ;
     RECT  2.16 58.995 71.28 59.265 ;
     RECT  2.16 59.535 71.28 59.805 ;
     RECT  2.16 60.075 71.28 60.345 ;
     RECT  2.16 60.615 71.28 60.885 ;
     RECT  2.16 61.155 71.28 61.425 ;
     RECT  2.16 61.695 71.28 61.965 ;
     RECT  2.16 62.235 71.28 62.505 ;
     RECT  2.16 62.775 71.28 63.045 ;
     RECT  2.16 63.315 71.28 63.585 ;
     RECT  2.16 63.855 71.28 64.125 ;
     RECT  2.16 64.395 71.28 64.665 ;
     RECT  2.16 64.935 71.28 65.205 ;
     RECT  2.16 65.475 71.28 65.745 ;
     RECT  2.16 66.015 71.28 66.285 ;
     RECT  2.16 66.555 71.28 66.825 ;
     RECT  2.16 67.095 71.28 67.365 ;
     RECT  2.16 67.635 71.28 67.905 ;
     RECT  2.16 68.175 71.28 68.445 ;
     RECT  2.16 68.715 71.28 68.985 ;
     RECT  2.16 69.255 71.28 69.525 ;
     RECT  2.16 69.795 71.28 70.065 ;
     RECT  2.16 70.335 71.28 70.605 ;
     RECT  2.16 70.875 71.28 71.145 ;
    LAYER M1 ;
     RECT  2.16 2.151 71.28 71.289 ;
    LAYER M2 ;
     RECT  0.103 15.3 0.139 15.318 ;
     RECT  0.103 19.818 0.139 20.718 ;
     RECT  0.103 21.51 0.139 21.528 ;
     RECT  0.103 22.518 0.139 22.536 ;
     RECT  0.103 26.532 0.139 26.55 ;
     RECT  0.103 44.424 0.139 44.442 ;
     RECT  0.139 19.818 0.175 21.528 ;
     RECT  0.139 22.518 0.175 22.77 ;
     RECT  0.139 30.852 0.175 30.87 ;
     RECT  0.103 37.98 0.175 37.998 ;
     RECT  0.103 39.186 0.175 39.51 ;
     RECT  0.139 44.388 0.175 44.442 ;
     RECT  0.175 30.852 0.211 30.942 ;
     RECT  0.211 30.69 0.247 30.942 ;
     RECT  0.175 36.522 0.247 36.54 ;
     RECT  0.103 29.574 0.283 29.592 ;
     RECT  0.247 30.42 0.283 30.942 ;
     RECT  0.175 37.98 0.311 39.51 ;
     RECT  0.211 41.796 0.347 41.814 ;
     RECT  0.175 44.118 0.463 44.442 ;
     RECT  0.139 15.3 0.499 15.858 ;
     RECT  0.499 15.228 0.535 15.858 ;
     RECT  0.175 17.082 0.535 17.1 ;
     RECT  0.499 23.904 0.535 23.922 ;
     RECT  0.139 26.532 0.535 26.928 ;
     RECT  0.247 36.522 0.535 36.81 ;
     RECT  0.103 45.81 0.535 45.828 ;
     RECT  0.103 47.862 0.535 47.88 ;
     RECT  0.103 33.426 1.147 33.444 ;
     RECT  0.103 34.74 1.147 34.758 ;
     RECT  0.535 36.522 1.183 36.882 ;
     RECT  0.311 37.98 1.183 38.736 ;
     RECT  0.311 39.492 1.183 39.51 ;
     RECT  0.283 28.8 1.399 28.818 ;
     RECT  0.283 29.574 1.399 30.942 ;
     RECT  0.103 51.912 1.399 51.93 ;
     RECT  1.147 33.426 1.471 34.758 ;
     RECT  0.103 18.198 1.723 18.558 ;
     RECT  0.175 19.512 1.723 22.77 ;
     RECT  1.399 28.8 1.723 30.942 ;
     RECT  0.535 47.16 1.723 47.88 ;
     RECT  0.103 25.56 1.759 25.578 ;
     RECT  0.535 26.532 1.759 27.504 ;
     RECT  1.723 28.8 1.759 31.14 ;
     RECT  0.535 45.81 1.759 46.062 ;
     RECT  1.723 47.052 1.759 47.88 ;
     RECT  1.759 45.81 1.867 47.88 ;
     RECT  1.147 48.672 1.867 49.23 ;
     RECT  1.867 45.81 1.939 49.23 ;
     RECT  1.723 50.13 1.939 50.148 ;
     RECT  1.471 32.814 2.047 34.758 ;
     RECT  1.183 37.98 2.047 39.51 ;
     RECT  1.687 40.374 2.047 40.392 ;
     RECT  0.535 15.03 2.16 15.858 ;
     RECT  0.535 16.956 2.16 17.1 ;
     RECT  1.723 18.198 2.16 22.77 ;
     RECT  0.535 23.67 2.16 23.922 ;
     RECT  1.147 24.75 2.16 24.768 ;
     RECT  1.759 25.56 2.16 27.504 ;
     RECT  1.759 28.8 2.16 31.68 ;
     RECT  2.047 32.814 2.16 34.992 ;
     RECT  1.183 35.982 2.16 36.882 ;
     RECT  2.047 37.98 2.16 40.392 ;
     RECT  1.939 42.534 2.16 42.552 ;
     RECT  0.463 43.416 2.16 44.442 ;
     RECT  1.939 45.81 2.16 50.148 ;
     RECT  1.399 51.912 2.16 52.2 ;
     RECT  2.16 2.151 71.28 71.289 ;
     RECT  71.28 44.856 71.339 53.424 ;
     RECT  71.28 19.116 71.519 19.134 ;
     RECT  71.339 52.416 71.519 53.424 ;
     RECT  71.339 44.856 71.735 51.462 ;
     RECT  71.519 52.416 71.771 52.776 ;
     RECT  71.28 21.438 71.843 22.806 ;
     RECT  71.735 44.856 71.843 51.354 ;
     RECT  71.843 21.636 71.879 22.806 ;
     RECT  71.879 21.636 71.915 22.032 ;
     RECT  71.28 23.598 72.347 42.984 ;
     RECT  71.843 46.206 72.347 51.354 ;
     RECT  72.347 23.598 72.383 35.73 ;
     RECT  72.347 36.756 72.383 36.918 ;
     RECT  72.347 38.106 72.383 39.204 ;
     RECT  72.347 40.176 72.383 42.984 ;
     RECT  72.347 46.206 72.383 50.994 ;
     RECT  71.771 52.416 72.383 52.434 ;
     RECT  71.915 21.636 72.419 21.654 ;
     RECT  72.383 25.596 72.419 29.628 ;
     RECT  72.383 30.888 72.419 34.182 ;
     RECT  72.383 35.316 72.419 35.73 ;
     RECT  71.843 44.928 72.419 45.45 ;
     RECT  72.383 48.978 72.419 49.194 ;
     RECT  72.419 25.596 72.455 25.974 ;
     RECT  72.419 35.586 72.455 35.73 ;
     RECT  72.419 32.472 72.491 32.634 ;
     RECT  72.419 30.888 73.283 30.906 ;
     RECT  72.455 25.596 73.319 25.884 ;
     RECT  72.419 27.036 73.319 28.476 ;
     RECT  72.491 32.472 73.319 32.49 ;
     RECT  72.419 33.39 73.319 33.444 ;
     RECT  72.383 41.454 73.319 42.174 ;
     RECT  73.319 25.596 73.355 25.614 ;
     RECT  73.319 27.036 73.355 27.936 ;
     RECT  72.419 29.61 73.355 29.628 ;
     RECT  72.419 31.662 73.355 31.68 ;
     RECT  73.319 33.426 73.355 33.444 ;
     RECT  72.455 35.712 73.355 35.73 ;
     RECT  72.383 36.9 73.355 36.918 ;
     RECT  72.383 38.556 73.355 38.574 ;
     RECT  72.383 40.176 73.355 40.194 ;
     RECT  73.319 42.156 73.355 42.174 ;
     RECT  72.419 45 73.355 45.45 ;
     RECT  72.383 46.386 73.355 47.07 ;
     RECT  72.419 48.978 73.355 48.996 ;
     RECT  71.879 22.788 73.427 22.806 ;
     RECT  73.327 24.138 73.427 24.156 ;
    LAYER M3 ;
     RECT  2.415 2.143 2.505 2.413 ;
     RECT  7.815 2.143 7.905 2.413 ;
     RECT  13.215 2.143 13.305 2.413 ;
     RECT  18.615 2.143 18.705 2.413 ;
     RECT  24.015 2.143 24.105 2.413 ;
     RECT  29.415 2.143 29.505 2.413 ;
     RECT  34.815 2.143 34.905 2.413 ;
     RECT  40.215 2.143 40.305 2.413 ;
     RECT  45.615 2.143 45.705 2.413 ;
     RECT  51.015 2.143 51.105 2.413 ;
     RECT  56.415 2.143 56.505 2.413 ;
     RECT  61.815 2.143 61.905 2.413 ;
     RECT  67.215 2.143 67.305 2.413 ;
     RECT  7.815 2.413 8.097 14.341 ;
     RECT  2.415 2.413 2.697 14.521 ;
     RECT  2.415 14.521 2.97 14.791 ;
     RECT  4.068 14.755 4.086 14.791 ;
     RECT  5.328 14.611 5.346 14.791 ;
     RECT  7.815 14.341 8.154 14.791 ;
     RECT  5.256 14.791 5.346 14.819 ;
     RECT  0.54 15.025 0.558 15.223 ;
     RECT  0.504 15.223 0.558 15.295 ;
     RECT  5.256 14.819 5.274 15.331 ;
     RECT  2.415 14.791 4.086 15.601 ;
     RECT  4.896 15.331 5.274 15.601 ;
     RECT  0.108 15.295 0.558 15.917 ;
     RECT  2.415 15.601 5.778 15.961 ;
     RECT  0.108 15.917 0.522 16.013 ;
     RECT  2.415 15.961 6.066 16.105 ;
     RECT  0.144 16.013 0.522 16.109 ;
     RECT  33.732 15.691 33.75 16.259 ;
     RECT  37.224 16.141 37.242 16.259 ;
     RECT  22.104 15.979 22.122 16.267 ;
     RECT  22.104 16.267 22.338 16.295 ;
     RECT  0.144 16.109 0.486 16.301 ;
     RECT  38.16 16.231 38.178 16.301 ;
     RECT  22.32 16.295 22.338 16.304 ;
     RECT  7.092 14.791 8.154 16.375 ;
     RECT  2.304 16.105 6.066 16.501 ;
     RECT  6.84 16.375 8.154 16.501 ;
     RECT  8.928 16.375 8.946 16.529 ;
     RECT  2.304 16.501 8.154 16.609 ;
     RECT  24.015 2.413 24.297 16.771 ;
     RECT  32.58 16.411 32.598 16.799 ;
     RECT  10.8 16.645 10.818 16.807 ;
     RECT  23.976 16.771 24.297 16.829 ;
     RECT  22.824 16.375 22.842 16.835 ;
     RECT  10.8 16.807 10.926 16.871 ;
     RECT  40.215 2.413 40.497 16.879 ;
     RECT  10.908 16.871 10.926 16.907 ;
     RECT  31.032 16.807 31.05 16.943 ;
     RECT  32.688 16.807 32.778 16.943 ;
     RECT  0.396 16.301 0.486 16.951 ;
     RECT  40.215 16.879 40.914 16.951 ;
     RECT  2.304 16.609 8.406 16.973 ;
     RECT  38.772 16.411 38.79 16.979 ;
     RECT  37.332 16.339 37.998 17.041 ;
     RECT  0.396 16.951 0.558 17.077 ;
     RECT  2.304 16.973 6.03 17.077 ;
     RECT  34.815 2.413 35.097 17.077 ;
     RECT  39.888 16.951 40.914 17.077 ;
     RECT  6.768 16.973 8.406 17.117 ;
     RECT  39.708 17.077 40.914 17.117 ;
     RECT  2.232 17.077 6.03 17.165 ;
     RECT  2.232 17.165 5.778 17.467 ;
     RECT  18.615 2.413 18.897 17.581 ;
     RECT  8.928 17.455 8.946 17.609 ;
     RECT  18.615 17.581 18.954 17.645 ;
     RECT  6.768 17.117 8.154 17.755 ;
     RECT  32.688 16.943 32.706 17.761 ;
     RECT  33.804 16.411 33.822 17.761 ;
     RECT  1.836 17.467 5.778 17.803 ;
     RECT  6.552 17.755 8.154 17.851 ;
     RECT  34.632 17.077 35.097 17.959 ;
     RECT  36.144 17.491 36.162 17.959 ;
     RECT  40.215 17.117 40.914 17.995 ;
     RECT  21.096 17.755 21.114 18.121 ;
     RECT  34.632 17.959 36.162 18.121 ;
     RECT  6.552 17.851 8.226 18.149 ;
     RECT  10.836 17.659 10.854 18.149 ;
     RECT  32.688 17.761 33.822 18.149 ;
     RECT  21.096 18.121 21.294 18.173 ;
     RECT  21.096 18.173 21.114 18.185 ;
     RECT  0.18 17.077 0.558 18.193 ;
     RECT  33.804 18.149 33.822 18.193 ;
     RECT  34.632 18.121 36.378 18.193 ;
     RECT  40.215 17.995 41.094 18.193 ;
     RECT  7.164 18.149 8.226 18.221 ;
     RECT  1.728 17.803 5.778 18.301 ;
     RECT  30.96 16.951 30.978 18.391 ;
     RECT  1.728 18.301 6.39 18.419 ;
     RECT  7.308 18.221 8.226 18.419 ;
     RECT  37.332 17.041 38.538 18.427 ;
     RECT  39.564 18.193 41.094 18.427 ;
     RECT  30.816 18.391 30.978 18.461 ;
     RECT  7.38 18.419 8.226 18.491 ;
     RECT  0.108 18.193 0.558 18.509 ;
     RECT  37.332 18.427 38.79 18.527 ;
     RECT  39.564 18.427 41.238 18.527 ;
     RECT  70.056 18.571 70.254 18.697 ;
     RECT  7.416 18.491 8.226 18.769 ;
     RECT  7.416 18.769 8.406 18.797 ;
     RECT  7.815 18.797 8.406 18.805 ;
     RECT  37.332 18.527 38.538 18.833 ;
     RECT  69.876 18.697 70.254 18.841 ;
     RECT  1.728 18.419 6.03 18.869 ;
     RECT  0.108 18.509 0.342 18.893 ;
     RECT  1.836 18.869 6.03 19.067 ;
     RECT  2.268 19.067 6.03 19.103 ;
     RECT  69.336 18.841 70.254 19.111 ;
     RECT  70.992 19.039 71.01 19.111 ;
     RECT  0.144 18.893 0.342 19.277 ;
     RECT  2.304 19.103 6.03 19.615 ;
     RECT  54.252 18.427 54.27 19.651 ;
     RECT  69.336 19.111 71.514 19.651 ;
     RECT  2.304 19.615 6.246 19.769 ;
     RECT  0.144 19.277 0.198 19.813 ;
     RECT  2.304 19.769 6.138 19.877 ;
     RECT  2.304 19.877 4.95 19.885 ;
     RECT  2.268 19.885 4.95 19.949 ;
     RECT  0.108 19.813 0.198 20.011 ;
     RECT  0.108 20.011 0.342 20.155 ;
     RECT  69.084 19.651 71.514 20.281 ;
     RECT  67.215 2.413 67.497 20.317 ;
     RECT  66.708 20.317 67.497 20.417 ;
     RECT  68.868 20.281 71.514 20.461 ;
     RECT  24.015 16.829 24.297 20.623 ;
     RECT  7.815 18.805 8.478 20.659 ;
     RECT  7.815 20.659 8.874 20.731 ;
     RECT  67.215 20.417 67.497 20.731 ;
     RECT  68.4 20.461 71.514 20.731 ;
     RECT  7.38 20.731 8.874 20.759 ;
     RECT  18.615 17.645 18.897 20.857 ;
     RECT  37.404 18.833 38.538 20.885 ;
     RECT  5.76 19.877 6.138 20.893 ;
     RECT  5.688 20.893 6.138 20.929 ;
     RECT  7.38 20.759 8.478 20.929 ;
     RECT  18.615 20.857 18.954 21.001 ;
     RECT  39.564 18.527 40.914 21.001 ;
     RECT  2.304 19.949 4.95 21.091 ;
     RECT  5.688 20.929 8.478 21.091 ;
     RECT  60.264 20.821 60.282 21.091 ;
     RECT  18.615 21.001 19.062 21.101 ;
     RECT  61.815 2.413 62.097 21.433 ;
     RECT  67.215 20.731 71.514 21.433 ;
     RECT  64.98 21.433 64.998 21.569 ;
     RECT  67.215 21.433 71.838 21.631 ;
     RECT  20.448 21.631 20.466 21.667 ;
     RECT  20.34 21.667 20.466 21.677 ;
     RECT  20.34 21.677 20.358 21.725 ;
     RECT  2.304 21.091 8.478 21.739 ;
     RECT  37.404 20.885 38.142 21.787 ;
     RECT  37.404 21.787 38.178 21.929 ;
     RECT  9.864 21.937 9.882 22.009 ;
     RECT  14.256 20.731 14.274 22.045 ;
     RECT  9.648 22.009 9.882 22.081 ;
     RECT  60.12 21.091 60.282 22.081 ;
     RECT  9.648 22.081 10.278 22.199 ;
     RECT  11.916 22.009 11.934 22.199 ;
     RECT  9.684 22.199 10.278 22.207 ;
     RECT  9.684 22.207 10.674 22.279 ;
     RECT  9.684 22.279 10.926 22.351 ;
     RECT  13.215 2.413 13.497 22.351 ;
     RECT  0.108 20.155 0.846 22.549 ;
     RECT  60.12 22.081 60.714 22.549 ;
     RECT  61.74 21.433 62.097 22.549 ;
     RECT  16.128 20.929 16.146 22.585 ;
     RECT  0.108 22.549 0.882 22.621 ;
     RECT  1.98 21.739 8.478 22.621 ;
     RECT  9.684 22.351 11.07 22.621 ;
     RECT  12.924 22.351 13.497 22.621 ;
     RECT  14.256 22.045 14.382 22.621 ;
     RECT  11.988 22.621 12.006 22.711 ;
     RECT  12.924 22.621 14.382 22.711 ;
     RECT  0.108 22.621 8.478 22.783 ;
     RECT  15.228 22.081 15.246 22.783 ;
     RECT  24.015 20.623 24.426 22.819 ;
     RECT  32.688 18.149 32.706 22.819 ;
     RECT  64.8 22.207 64.818 22.819 ;
     RECT  32.688 22.819 32.778 22.847 ;
     RECT  33.804 18.193 36.378 22.847 ;
     RECT  11.988 22.711 12.15 22.891 ;
     RECT  12.924 22.711 14.418 22.891 ;
     RECT  0.108 22.783 8.73 22.925 ;
     RECT  54.252 19.651 54.954 22.981 ;
     RECT  60.12 22.549 62.097 22.981 ;
     RECT  0.144 22.925 8.73 23.009 ;
     RECT  67.215 21.631 72.414 23.117 ;
     RECT  64.512 22.819 64.818 23.125 ;
     RECT  9.684 22.621 11.214 23.161 ;
     RECT  11.988 22.891 14.418 23.161 ;
     RECT  15.228 22.783 15.282 23.161 ;
     RECT  16.128 22.585 16.47 23.161 ;
     RECT  42.516 18.571 42.534 23.161 ;
     RECT  64.512 23.125 65.538 23.161 ;
     RECT  54.072 22.981 54.954 23.251 ;
     RECT  60.12 22.981 62.73 23.251 ;
     RECT  63.9 23.161 65.538 23.279 ;
     RECT  9.684 23.161 14.418 23.323 ;
     RECT  15.228 23.161 16.47 23.323 ;
     RECT  24.015 22.819 24.498 23.359 ;
     RECT  42.408 23.161 42.534 23.359 ;
     RECT  58.788 23.359 58.806 23.395 ;
     RECT  0.144 23.009 8.658 23.405 ;
     RECT  39.024 21.001 41.022 23.431 ;
     RECT  44.388 23.395 44.406 23.431 ;
     RECT  53.964 23.251 54.954 23.431 ;
     RECT  43.272 23.359 43.29 23.521 ;
     RECT  44.388 23.431 44.802 23.521 ;
     RECT  59.868 23.251 62.73 23.521 ;
     RECT  66.456 23.431 66.474 23.549 ;
     RECT  37.404 21.929 38.142 23.593 ;
     RECT  9.684 23.323 16.47 23.629 ;
     RECT  47.844 23.395 47.862 23.629 ;
     RECT  51.015 2.413 51.297 23.629 ;
     RECT  42.264 23.359 42.534 23.665 ;
     RECT  64.26 23.279 65.538 23.665 ;
     RECT  64.26 23.665 66.402 23.693 ;
     RECT  9.396 23.629 16.47 23.701 ;
     RECT  17.244 23.593 17.262 23.701 ;
     RECT  30.888 18.461 30.978 23.701 ;
     RECT  32.76 22.847 32.778 23.701 ;
     RECT  33.804 22.847 36.306 23.701 ;
     RECT  37.368 23.593 38.142 23.701 ;
     RECT  42.192 23.665 42.534 23.701 ;
     RECT  43.272 23.521 44.802 23.701 ;
     RECT  46.728 23.359 46.746 23.701 ;
     RECT  47.844 23.629 48.114 23.701 ;
     RECT  58.716 23.395 58.842 23.701 ;
     RECT  59.652 23.521 62.73 23.701 ;
     RECT  37.332 23.701 38.142 23.755 ;
     RECT  46.728 23.701 48.114 23.819 ;
     RECT  0.504 23.405 8.658 23.827 ;
     RECT  9.396 23.701 17.262 23.827 ;
     RECT  32.688 23.701 32.778 23.827 ;
     RECT  33.804 23.701 36.414 23.827 ;
     RECT  37.296 23.755 38.25 23.827 ;
     RECT  32.544 23.827 32.778 23.885 ;
     RECT  33.804 23.827 38.25 23.899 ;
     RECT  58.716 23.701 62.73 23.899 ;
     RECT  33.624 23.899 38.25 23.927 ;
     RECT  39.024 23.431 41.058 23.935 ;
     RECT  42.192 23.701 44.802 23.935 ;
     RECT  45.615 2.413 45.897 23.935 ;
     RECT  46.728 23.819 47.034 23.935 ;
     RECT  47.844 23.819 48.114 23.935 ;
     RECT  56.415 2.413 56.697 23.935 ;
     RECT  33.624 23.927 36.558 23.971 ;
     RECT  37.296 23.927 38.25 23.971 ;
     RECT  39.024 23.935 44.802 23.971 ;
     RECT  51.015 23.629 51.498 23.971 ;
     RECT  57.564 23.665 57.582 23.999 ;
     RECT  0.504 23.827 17.262 24.061 ;
     RECT  58.716 23.899 63.378 24.061 ;
     RECT  67.215 23.117 72.378 24.061 ;
     RECT  47.844 23.935 48.474 24.089 ;
     RECT  37.296 23.971 44.802 24.091 ;
     RECT  45.615 23.935 47.034 24.091 ;
     RECT  53.856 23.431 54.954 24.097 ;
     RECT  56.415 23.935 56.754 24.124 ;
     RECT  73.404 22.783 73.422 24.133 ;
     RECT  73.332 24.133 73.422 24.161 ;
     RECT  53.748 24.097 55.134 24.169 ;
     RECT  73.332 24.161 73.35 24.173 ;
     RECT  32.58 23.885 32.778 24.205 ;
     RECT  33.516 23.971 36.558 24.205 ;
     RECT  50.616 23.971 51.498 24.205 ;
     RECT  24.015 23.359 24.606 24.232 ;
     RECT  58.716 24.061 63.45 24.241 ;
     RECT  64.26 23.693 65.358 24.241 ;
     RECT  37.296 24.091 47.034 24.269 ;
     RECT  58.716 24.241 65.358 24.269 ;
     RECT  30.888 23.701 31.41 24.359 ;
     RECT  32.58 24.205 36.558 24.359 ;
     RECT  37.296 24.269 46.998 24.359 ;
     RECT  52.956 24.169 55.134 24.359 ;
     RECT  63.936 24.269 65.358 24.359 ;
     RECT  58.716 24.269 63.198 24.367 ;
     RECT  36.108 24.359 36.558 24.368 ;
     RECT  44.172 24.359 46.998 24.395 ;
     RECT  52.956 24.359 52.974 24.395 ;
     RECT  50.616 24.205 52.11 24.403 ;
     RECT  33.012 24.359 35.37 24.431 ;
     RECT  0.504 24.061 17.838 24.439 ;
     RECT  18.615 21.101 18.897 24.439 ;
     RECT  37.296 24.359 43.362 24.461 ;
     RECT  44.172 24.395 46.89 24.467 ;
     RECT  30.96 24.359 31.41 24.469 ;
     RECT  56.415 24.124 56.79 24.503 ;
     RECT  30.96 24.469 31.59 24.509 ;
     RECT  33.012 24.431 33.246 24.509 ;
     RECT  53.748 24.359 55.134 24.511 ;
     RECT  66.24 23.693 66.402 24.511 ;
     RECT  67.176 24.061 72.378 24.511 ;
     RECT  0.504 24.439 18.897 24.601 ;
     RECT  30.96 24.509 31.41 24.629 ;
     RECT  44.172 24.467 46.818 24.665 ;
     RECT  50.256 24.403 52.11 24.665 ;
     RECT  53.748 24.511 55.458 24.665 ;
     RECT  47.88 24.089 48.474 24.709 ;
     RECT  0.504 24.601 19.026 24.745 ;
     RECT  37.296 24.461 43.29 24.745 ;
     RECT  54.252 24.665 55.458 24.745 ;
     RECT  58.428 24.367 63.198 24.745 ;
     RECT  44.172 24.665 45.897 24.773 ;
     RECT  23.904 24.232 24.606 24.781 ;
     RECT  23.292 24.781 24.606 24.935 ;
     RECT  33.012 24.509 33.102 24.935 ;
     RECT  54.252 24.745 55.674 24.935 ;
     RECT  54.252 24.935 55.638 25.007 ;
     RECT  49.788 24.871 49.806 25.043 ;
     RECT  0.504 24.745 19.962 25.051 ;
     RECT  20.7 23.251 20.718 25.051 ;
     RECT  58.068 24.745 63.198 25.085 ;
     RECT  33.012 24.935 33.03 25.099 ;
     RECT  21.636 25.051 21.654 25.141 ;
     RECT  34.164 24.431 35.37 25.141 ;
     RECT  36.108 24.368 36.306 25.141 ;
     RECT  50.724 24.665 52.11 25.141 ;
     RECT  58.428 25.085 63.198 25.141 ;
     RECT  64.044 24.359 65.358 25.141 ;
     RECT  32.832 25.099 33.03 25.169 ;
     RECT  47.88 24.709 49.014 25.169 ;
     RECT  50.724 25.141 52.434 25.205 ;
     RECT  34.164 25.141 36.306 25.213 ;
     RECT  37.044 24.745 43.29 25.213 ;
     RECT  46.656 24.665 46.818 25.213 ;
     RECT  46.656 25.213 46.89 25.241 ;
     RECT  0.504 25.051 20.718 25.249 ;
     RECT  21.636 25.141 22.554 25.249 ;
     RECT  34.164 25.213 43.29 25.249 ;
     RECT  47.88 25.169 48.474 25.249 ;
     RECT  34.164 25.249 43.398 25.277 ;
     RECT  66.24 24.511 72.378 25.285 ;
     RECT  47.808 25.249 48.474 25.313 ;
     RECT  26.064 25.285 26.082 25.321 ;
     RECT  34.164 25.277 35.37 25.321 ;
     RECT  46.764 25.241 46.89 25.349 ;
     RECT  58.428 25.141 65.358 25.387 ;
     RECT  66.168 25.285 72.378 25.387 ;
     RECT  33.876 25.321 35.37 25.475 ;
     RECT  36.108 25.277 43.398 25.475 ;
     RECT  46.764 25.349 46.854 25.475 ;
     RECT  58.428 25.387 72.378 25.511 ;
     RECT  0.504 25.249 22.554 25.555 ;
     RECT  0.108 25.555 22.554 25.583 ;
     RECT  23.436 24.935 24.606 25.591 ;
     RECT  25.668 25.321 26.082 25.591 ;
     RECT  46.764 25.475 46.782 25.619 ;
     RECT  21.816 25.583 22.554 25.681 ;
     RECT  23.436 25.591 26.082 25.681 ;
     RECT  36.252 25.475 43.398 25.681 ;
     RECT  44.244 24.773 45.897 25.681 ;
     RECT  32.832 25.169 32.85 25.717 ;
     RECT  47.808 25.313 48.186 25.745 ;
     RECT  50.796 25.205 52.434 25.745 ;
     RECT  32.472 25.717 32.85 25.757 ;
     RECT  21.816 25.681 26.082 25.789 ;
     RECT  0.108 25.583 21.078 25.817 ;
     RECT  47.88 25.745 48.186 25.853 ;
     RECT  29.415 2.413 29.697 25.861 ;
     RECT  73.332 25.591 73.35 25.861 ;
     RECT  52.02 25.745 52.434 25.951 ;
     RECT  66.672 25.511 72.378 25.951 ;
     RECT  28.908 25.861 29.697 25.979 ;
     RECT  32.652 25.757 32.85 25.979 ;
     RECT  52.02 25.951 52.83 25.979 ;
     RECT  31.392 24.629 31.41 25.987 ;
     RECT  50.796 25.745 51.297 25.987 ;
     RECT  52.02 25.979 52.038 26.015 ;
     RECT  36.252 25.681 45.897 26.023 ;
     RECT  32.796 25.979 32.85 26.087 ;
     RECT  36.252 26.023 46.278 26.087 ;
     RECT  30.852 25.987 31.41 26.131 ;
     RECT  34.164 25.475 35.37 26.221 ;
     RECT  36.252 26.087 36.522 26.221 ;
     RECT  52.812 25.979 52.83 26.249 ;
     RECT  21.816 25.789 26.262 26.257 ;
     RECT  60.264 25.511 65.61 26.257 ;
     RECT  66.672 25.951 72.45 26.257 ;
     RECT  47.988 25.853 48.186 26.293 ;
     RECT  30.852 26.131 31.518 26.299 ;
     RECT  10.908 25.817 21.078 26.329 ;
     RECT  21.816 26.257 26.334 26.329 ;
     RECT  58.428 25.511 59.274 26.365 ;
     RECT  10.908 26.329 26.334 26.401 ;
     RECT  30.816 26.299 31.518 26.401 ;
     RECT  58.212 26.365 59.274 26.401 ;
     RECT  60.264 26.257 65.646 26.401 ;
     RECT  58.212 26.401 65.646 26.491 ;
     RECT  30.78 26.401 31.518 26.527 ;
     RECT  37.296 26.087 46.278 26.539 ;
     RECT  10.908 26.401 26.406 26.555 ;
     RECT  32.976 26.131 32.994 26.629 ;
     RECT  0.108 25.817 10.134 26.635 ;
     RECT  10.908 26.555 25.902 26.635 ;
     RECT  30.78 26.527 31.59 26.635 ;
     RECT  66.6 26.257 72.45 26.635 ;
     RECT  0.108 26.635 25.902 26.669 ;
     RECT  58.14 26.491 65.646 26.669 ;
     RECT  30.78 26.635 31.662 26.671 ;
     RECT  32.976 26.629 33.354 26.671 ;
     RECT  34.164 26.221 36.522 26.671 ;
     RECT  47.988 26.293 48.222 26.671 ;
     RECT  0.972 26.669 25.902 26.699 ;
     RECT  58.14 26.669 58.77 26.699 ;
     RECT  66.564 26.635 72.45 26.765 ;
     RECT  30.78 26.671 31.806 26.789 ;
     RECT  59.508 26.669 65.646 26.789 ;
     RECT  27.9 26.761 27.918 26.827 ;
     RECT  28.98 25.979 29.697 26.827 ;
     RECT  27.9 26.827 27.954 26.869 ;
     RECT  37.296 26.539 46.854 26.869 ;
     RECT  27.9 26.869 28.098 26.905 ;
     RECT  28.98 26.827 30.042 26.905 ;
     RECT  58.14 26.699 58.734 26.933 ;
     RECT  32.976 26.671 36.522 26.941 ;
     RECT  65.16 26.789 65.646 26.941 ;
     RECT  66.564 26.765 72.414 26.941 ;
     RECT  0.972 26.699 5.706 27.005 ;
     RECT  0.108 26.669 0.162 27.053 ;
     RECT  27.9 26.905 30.042 27.059 ;
     RECT  32.652 26.941 36.522 27.061 ;
     RECT  37.296 26.869 46.89 27.067 ;
     RECT  27.9 27.059 28.098 27.095 ;
     RECT  32.58 27.061 36.522 27.095 ;
     RECT  32.58 27.095 32.85 27.101 ;
     RECT  26.64 27.067 26.658 27.115 ;
     RECT  33.732 27.095 36.522 27.115 ;
     RECT  37.26 27.067 46.89 27.115 ;
     RECT  47.664 26.671 48.222 27.115 ;
     RECT  73.296 25.861 73.35 27.115 ;
     RECT  27.972 27.095 27.99 27.131 ;
     RECT  0.972 27.005 5.67 27.149 ;
     RECT  28.98 27.059 30.042 27.167 ;
     RECT  73.26 27.115 73.35 27.167 ;
     RECT  73.296 27.167 73.35 27.203 ;
     RECT  1.728 27.149 5.67 27.239 ;
     RECT  58.284 26.933 58.734 27.239 ;
     RECT  59.508 26.789 64.206 27.245 ;
     RECT  6.516 26.699 25.902 27.301 ;
     RECT  26.64 27.115 26.694 27.301 ;
     RECT  33.732 27.115 48.222 27.301 ;
     RECT  29.232 27.167 30.042 27.329 ;
     RECT  29.268 27.329 30.042 27.337 ;
     RECT  30.78 26.789 31.482 27.337 ;
     RECT  32.76 27.101 32.85 27.365 ;
     RECT  29.268 27.337 31.482 27.389 ;
     RECT  33.732 27.301 48.654 27.409 ;
     RECT  65.16 26.941 72.414 27.437 ;
     RECT  0.144 27.053 0.162 27.481 ;
     RECT  33.732 27.409 48.726 27.481 ;
     RECT  65.16 27.437 72.378 27.533 ;
     RECT  52.488 27.571 52.506 27.595 ;
     RECT  6.516 27.301 26.694 27.607 ;
     RECT  59.508 27.245 64.098 27.607 ;
     RECT  29.304 27.389 29.79 27.635 ;
     RECT  33.732 27.481 48.798 27.643 ;
     RECT  50.724 25.987 51.297 27.643 ;
     RECT  52.416 27.595 52.506 27.643 ;
     RECT  59.472 27.607 64.098 27.643 ;
     RECT  2.304 27.239 5.67 27.671 ;
     RECT  33.732 27.643 49.05 27.743 ;
     RECT  0.144 27.481 0.558 27.821 ;
     RECT  50.724 27.643 52.506 27.835 ;
     RECT  54.252 25.007 54.954 27.841 ;
     RECT  59.256 27.643 64.098 27.875 ;
     RECT  6.408 27.607 26.694 27.913 ;
     RECT  54.252 27.841 55.602 27.917 ;
     RECT  6.264 27.913 26.694 27.949 ;
     RECT  59.976 27.875 64.098 27.985 ;
     RECT  65.16 27.533 70.866 27.985 ;
     RECT  58.284 27.239 58.482 28.021 ;
     RECT  29.415 27.635 29.79 28.111 ;
     RECT  30.528 27.389 31.482 28.111 ;
     RECT  6.264 27.949 27.018 28.175 ;
     RECT  33.912 27.743 49.05 28.253 ;
     RECT  33.984 28.253 49.05 28.291 ;
     RECT  0.54 27.821 0.558 28.301 ;
     RECT  50.724 27.835 52.722 28.301 ;
     RECT  6.264 28.175 21.402 28.409 ;
     RECT  33.984 28.291 49.986 28.409 ;
     RECT  50.724 28.301 51.93 28.409 ;
     RECT  59.976 27.985 70.866 28.409 ;
     RECT  22.212 28.175 27.018 28.417 ;
     RECT  54.252 27.917 55.206 28.417 ;
     RECT  18.072 28.409 21.402 28.445 ;
     RECT  58.284 28.021 58.986 28.453 ;
     RECT  73.332 27.203 73.35 28.453 ;
     RECT  71.82 27.533 72.378 28.459 ;
     RECT  2.304 27.671 5.274 28.489 ;
     RECT  6.264 28.409 17.118 28.489 ;
     RECT  34.164 28.409 49.986 28.493 ;
     RECT  29.415 28.111 31.482 28.507 ;
     RECT  52.956 28.381 52.974 28.525 ;
     RECT  56.415 24.503 56.697 28.552 ;
     RECT  18.18 28.445 21.402 28.589 ;
     RECT  22.212 28.417 27.162 28.603 ;
     RECT  22.212 28.603 27.27 28.651 ;
     RECT  28.764 28.507 31.482 28.651 ;
     RECT  58.068 28.453 58.986 28.651 ;
     RECT  22.212 28.651 27.342 28.679 ;
     RECT  37.296 28.493 49.986 28.679 ;
     RECT  60.228 28.409 70.866 28.715 ;
     RECT  22.428 28.679 27.342 28.723 ;
     RECT  28.08 28.651 31.482 28.723 ;
     RECT  2.304 28.489 17.118 28.751 ;
     RECT  58.068 28.651 59.058 28.759 ;
     RECT  0.324 28.651 0.342 28.78 ;
     RECT  0.288 28.78 0.342 28.795 ;
     RECT  54.18 28.417 55.206 28.795 ;
     RECT  60.264 28.715 70.866 28.831 ;
     RECT  71.784 28.459 72.378 28.831 ;
     RECT  58.068 28.759 59.238 28.859 ;
     RECT  60.264 28.831 72.378 28.877 ;
     RECT  71.784 28.877 72.378 28.921 ;
     RECT  2.304 28.751 15.138 28.949 ;
     RECT  58.068 28.859 59.166 28.957 ;
     RECT  37.296 28.679 49.41 28.985 ;
     RECT  54.18 28.795 55.566 28.993 ;
     RECT  56.304 28.552 56.697 28.993 ;
     RECT  57.924 28.957 59.166 29.021 ;
     RECT  37.296 28.985 47.898 29.057 ;
     RECT  52.956 28.525 53.01 29.065 ;
     RECT  54.18 28.993 56.697 29.069 ;
     RECT  32.22 28.921 32.238 29.078 ;
     RECT  51.015 28.409 51.93 29.191 ;
     RECT  32.22 29.078 32.49 29.219 ;
     RECT  58.176 29.021 59.166 29.219 ;
     RECT  2.304 28.949 14.994 29.255 ;
     RECT  16.164 28.751 17.118 29.255 ;
     RECT  22.428 28.723 31.482 29.261 ;
     RECT  56.376 29.069 56.697 29.335 ;
     RECT  73.296 28.453 73.35 29.357 ;
     RECT  16.236 29.255 17.118 29.363 ;
     RECT  32.292 29.219 32.49 29.363 ;
     RECT  37.296 29.057 43.398 29.363 ;
     RECT  34.164 28.493 36.486 29.371 ;
     RECT  37.296 29.363 39.042 29.371 ;
     RECT  60.264 28.877 70.866 29.399 ;
     RECT  18.324 28.589 21.402 29.461 ;
     RECT  58.176 29.219 58.878 29.489 ;
     RECT  60.264 29.399 63.234 29.489 ;
     RECT  64.44 29.399 70.866 29.489 ;
     RECT  2.304 29.255 11.07 29.497 ;
     RECT  16.308 29.363 17.118 29.525 ;
     RECT  52.92 29.065 53.01 29.525 ;
     RECT  18.324 29.461 21.438 29.549 ;
     RECT  0.144 28.795 0.342 29.569 ;
     RECT  50.724 29.191 51.93 29.569 ;
     RECT  50.724 29.569 52.794 29.605 ;
     RECT  2.268 29.497 11.07 29.633 ;
     RECT  34.164 29.371 39.042 29.641 ;
     RECT  48.708 28.985 49.41 29.641 ;
     RECT  32.472 29.363 32.49 29.659 ;
     RECT  19.98 29.549 21.438 29.669 ;
     RECT  11.988 29.255 14.994 29.731 ;
     RECT  32.472 29.659 32.634 29.731 ;
     RECT  33.804 29.641 39.042 29.731 ;
     RECT  2.268 29.633 9.846 29.759 ;
     RECT  11.988 29.731 15.066 29.767 ;
     RECT  20.052 29.669 21.438 29.767 ;
     RECT  11.988 29.767 15.102 29.795 ;
     RECT  50.328 29.605 52.794 29.795 ;
     RECT  50.328 29.795 51.93 29.803 ;
     RECT  54.18 29.069 55.602 29.803 ;
     RECT  58.176 29.489 58.806 29.803 ;
     RECT  0.108 29.569 0.342 29.837 ;
     RECT  71.784 28.921 72.414 29.837 ;
     RECT  39.852 29.363 43.398 29.875 ;
     RECT  44.244 29.057 47.898 29.875 ;
     RECT  71.784 29.837 72.378 29.899 ;
     RECT  20.052 29.767 21.51 29.903 ;
     RECT  48.708 29.641 49.482 29.911 ;
     RECT  50.22 29.803 51.93 29.911 ;
     RECT  53.676 29.803 55.602 29.911 ;
     RECT  56.376 29.335 56.754 29.911 ;
     RECT  60.264 29.489 63.126 29.911 ;
     RECT  1.404 28.957 1.422 29.995 ;
     RECT  2.268 29.759 9.81 29.995 ;
     RECT  53.676 29.911 56.754 30.029 ;
     RECT  73.332 29.357 73.35 30.029 ;
     RECT  20.124 29.903 21.51 30.037 ;
     RECT  54.18 30.029 56.754 30.043 ;
     RECT  60.12 29.911 63.126 30.065 ;
     RECT  20.124 30.037 21.618 30.137 ;
     RECT  39.852 29.875 47.898 30.145 ;
     RECT  48.672 29.911 51.93 30.145 ;
     RECT  18.324 29.549 19.062 30.173 ;
     RECT  18.324 30.173 18.99 30.181 ;
     RECT  54.18 30.043 57.222 30.181 ;
     RECT  58.032 29.803 58.806 30.181 ;
     RECT  64.44 29.489 66.186 30.181 ;
     RECT  10.764 29.633 11.07 30.187 ;
     RECT  32.472 29.731 39.042 30.187 ;
     RECT  67.215 29.489 70.866 30.187 ;
     RECT  71.748 29.899 72.378 30.187 ;
     RECT  54.18 30.181 58.806 30.209 ;
     RECT  60.12 30.065 60.282 30.209 ;
     RECT  16.308 29.525 16.938 30.271 ;
     RECT  64.152 30.181 66.186 30.271 ;
     RECT  67.215 30.187 72.378 30.271 ;
     RECT  60.12 30.209 60.21 30.331 ;
     RECT  16.236 30.271 17.01 30.343 ;
     RECT  17.928 30.181 18.99 30.343 ;
     RECT  61.02 30.065 63.126 30.343 ;
     RECT  14.976 29.795 15.102 30.371 ;
     RECT  20.196 30.137 21.618 30.415 ;
     RECT  22.536 29.261 31.482 30.415 ;
     RECT  64.152 30.271 72.378 30.415 ;
     RECT  55.548 30.209 58.806 30.443 ;
     RECT  16.236 30.343 18.99 30.451 ;
     RECT  20.196 30.415 31.482 30.451 ;
     RECT  32.22 30.187 39.042 30.451 ;
     RECT  52.776 29.795 52.794 30.451 ;
     RECT  58.14 30.443 58.806 30.451 ;
     RECT  60.012 30.331 60.21 30.451 ;
     RECT  10.764 30.187 11.178 30.541 ;
     RECT  12.096 29.795 14.166 30.541 ;
     RECT  20.196 30.451 39.042 30.569 ;
     RECT  52.776 30.451 53.01 30.569 ;
     RECT  55.548 30.443 57.078 30.569 ;
     RECT  61.02 30.343 63.234 30.569 ;
     RECT  20.196 30.569 20.214 30.605 ;
     RECT  52.776 30.569 52.794 30.605 ;
     RECT  54.18 30.209 54.81 30.605 ;
     RECT  1.404 29.995 9.81 30.613 ;
     RECT  10.764 30.541 11.322 30.613 ;
     RECT  61.092 30.569 63.234 30.613 ;
     RECT  64.116 30.415 72.378 30.613 ;
     RECT  20.988 30.569 39.042 30.641 ;
     RECT  58.14 30.451 60.21 30.641 ;
     RECT  1.404 30.613 11.322 30.649 ;
     RECT  12.096 30.541 14.922 30.649 ;
     RECT  1.404 30.649 14.922 30.677 ;
     RECT  15.696 30.451 18.99 30.677 ;
     RECT  39.852 30.145 51.93 30.721 ;
     RECT  61.092 30.613 72.378 30.749 ;
     RECT  1.404 30.677 13.842 30.811 ;
     RECT  1.152 30.811 13.842 30.839 ;
     RECT  60.048 30.641 60.21 30.839 ;
     RECT  61.815 30.749 72.378 30.839 ;
     RECT  0.108 29.837 0.306 30.847 ;
     RECT  73.152 30.763 73.17 30.859 ;
     RECT  55.548 30.569 57.042 30.875 ;
     RECT  73.152 30.859 73.278 30.893 ;
     RECT  73.26 30.893 73.278 30.911 ;
     RECT  18.615 30.677 18.99 30.919 ;
     RECT  15.696 30.677 17.874 30.947 ;
     RECT  15.696 30.947 17.73 30.983 ;
     RECT  0.108 30.847 0.342 30.989 ;
     RECT  21.564 30.641 39.042 30.991 ;
     RECT  39.816 30.721 51.93 30.991 ;
     RECT  1.152 30.839 10.926 31.019 ;
     RECT  18.615 30.919 19.35 31.109 ;
     RECT  14.688 30.677 14.922 31.117 ;
     RECT  15.696 30.983 17.622 31.117 ;
     RECT  18.615 31.109 19.242 31.253 ;
     RECT  0.108 30.989 0.306 31.277 ;
     RECT  21.564 30.991 51.93 31.325 ;
     RECT  60.192 30.839 60.21 31.339 ;
     RECT  1.152 31.019 10.854 31.379 ;
     RECT  21.564 31.325 33.282 31.415 ;
     RECT  34.056 31.325 51.93 31.423 ;
     RECT  53.028 31.387 53.046 31.423 ;
     RECT  56.415 30.875 57.042 31.423 ;
     RECT  58.14 30.641 59.31 31.423 ;
     RECT  22.176 31.415 33.102 31.451 ;
     RECT  54.18 30.605 54.738 31.459 ;
     RECT  56.415 31.423 59.31 31.495 ;
     RECT  56.415 31.495 59.382 31.523 ;
     RECT  66.42 30.839 72.378 31.531 ;
     RECT  14.688 31.117 17.622 31.559 ;
     RECT  14.688 31.559 16.65 31.649 ;
     RECT  17.424 31.559 17.622 31.649 ;
     RECT  22.176 31.451 22.338 31.649 ;
     RECT  0.108 31.277 0.27 31.661 ;
     RECT  17.424 31.649 17.442 31.685 ;
     RECT  34.056 31.423 53.046 31.685 ;
     RECT  60.192 31.339 61.038 31.693 ;
     RECT  54.18 31.459 54.81 31.729 ;
     RECT  55.548 30.875 55.566 31.729 ;
     RECT  66.42 31.531 72.414 31.757 ;
     RECT  12.024 30.839 13.734 31.765 ;
     RECT  21.096 31.459 21.186 31.793 ;
     RECT  12.024 31.765 13.95 31.801 ;
     RECT  14.688 31.649 14.922 31.801 ;
     RECT  60.156 31.693 61.038 31.801 ;
     RECT  61.815 30.839 65.682 31.801 ;
     RECT  22.176 31.649 22.194 31.805 ;
     RECT  56.415 31.523 57.366 31.805 ;
     RECT  60.156 31.801 65.682 31.805 ;
     RECT  42.732 31.685 53.046 31.829 ;
     RECT  58.14 31.523 59.382 31.853 ;
     RECT  23.256 31.451 33.102 31.919 ;
     RECT  16.344 31.649 16.65 31.955 ;
     RECT  42.768 31.829 53.046 31.955 ;
     RECT  23.4 31.919 33.102 31.991 ;
     RECT  42.768 31.955 52.254 32.063 ;
     RECT  34.056 31.685 37.602 32.071 ;
     RECT  60.516 31.805 65.682 32.071 ;
     RECT  66.42 31.757 70.938 32.071 ;
     RECT  58.14 31.853 59.31 32.099 ;
     RECT  1.152 31.379 9.666 32.155 ;
     RECT  1.152 32.155 9.99 32.189 ;
     RECT  60.516 32.071 70.938 32.189 ;
     RECT  11.808 31.801 14.922 32.233 ;
     RECT  0.108 31.661 0.198 32.237 ;
     RECT  11.772 32.233 14.922 32.261 ;
     RECT  16.344 31.955 16.47 32.297 ;
     RECT  21.096 31.793 21.114 32.297 ;
     RECT  49.392 32.063 52.254 32.297 ;
     RECT  71.748 31.757 72.414 32.297 ;
     RECT  58.14 32.099 59.022 32.305 ;
     RECT  8.82 32.189 9.99 32.341 ;
     RECT  10.728 31.379 10.854 32.341 ;
     RECT  56.415 31.805 57.114 32.369 ;
     RECT  61.452 32.189 70.938 32.369 ;
     RECT  71.784 32.297 72.414 32.369 ;
     RECT  8.82 32.341 10.926 32.459 ;
     RECT  14.868 32.261 14.922 32.459 ;
     RECT  33.948 32.071 37.602 32.459 ;
     RECT  42.768 32.063 48.546 32.459 ;
     RECT  49.392 32.297 52.182 32.459 ;
     RECT  10.8 32.459 10.926 32.467 ;
     RECT  23.436 31.991 33.102 32.467 ;
     RECT  33.948 32.459 35.262 32.467 ;
     RECT  73.332 31.657 73.35 32.467 ;
     RECT  45.324 32.459 48.546 32.477 ;
     RECT  14.904 32.459 14.922 32.495 ;
     RECT  42.768 32.459 43.362 32.495 ;
     RECT  44.1 32.459 44.478 32.495 ;
     RECT  47.52 32.477 48.402 32.495 ;
     RECT  49.5 32.459 52.182 32.495 ;
     RECT  56.415 32.369 56.898 32.495 ;
     RECT  53.028 31.955 53.046 32.503 ;
     RECT  36.072 32.459 37.602 32.539 ;
     RECT  38.34 31.685 41.814 32.539 ;
     RECT  23.436 32.467 35.262 32.603 ;
     RECT  54.18 31.729 55.566 32.603 ;
     RECT  10.8 32.467 11.034 32.611 ;
     RECT  11.772 32.261 14.13 32.611 ;
     RECT  57.96 32.305 59.022 32.611 ;
     RECT  72.36 32.369 72.414 32.611 ;
     RECT  36.072 32.539 41.814 32.639 ;
     RECT  10.8 32.611 14.13 32.729 ;
     RECT  47.52 32.495 48.078 32.729 ;
     RECT  49.5 32.495 51.93 32.729 ;
     RECT  53.028 32.503 53.226 32.737 ;
     RECT  36.252 32.639 41.814 32.765 ;
     RECT  57.636 32.611 59.022 32.771 ;
     RECT  55.548 32.603 55.566 32.773 ;
     RECT  56.415 32.495 56.697 32.773 ;
     RECT  36.432 32.765 41.814 32.809 ;
     RECT  42.768 32.495 43.29 32.809 ;
     RECT  64.692 32.369 70.938 32.837 ;
     RECT  1.152 32.189 8.097 32.909 ;
     RECT  72.36 32.611 72.486 32.909 ;
     RECT  8.82 32.459 10.062 32.999 ;
     RECT  36.432 32.809 43.29 32.999 ;
     RECT  52.992 32.737 53.226 32.999 ;
     RECT  2.196 32.909 8.097 33.005 ;
     RECT  36.504 32.999 43.29 33.035 ;
     RECT  49.5 32.729 50.274 33.035 ;
     RECT  52.992 32.999 53.01 33.035 ;
     RECT  55.548 32.773 56.697 33.035 ;
     RECT  57.636 32.771 58.878 33.035 ;
     RECT  61.452 32.369 63.918 33.053 ;
     RECT  23.436 32.603 28.278 33.071 ;
     RECT  29.016 32.603 35.262 33.071 ;
     RECT  40.068 33.035 43.29 33.071 ;
     RECT  60.696 32.189 60.714 33.079 ;
     RECT  61.452 33.053 63.27 33.079 ;
     RECT  2.232 33.005 8.097 33.151 ;
     RECT  8.82 32.999 9.846 33.151 ;
     RECT  60.696 33.079 63.27 33.151 ;
     RECT  64.692 32.837 70.902 33.151 ;
     RECT  33.408 33.071 35.262 33.269 ;
     RECT  60.516 33.151 63.27 33.277 ;
     RECT  10.836 32.729 14.13 33.313 ;
     RECT  40.104 33.071 43.29 33.349 ;
     RECT  44.1 32.495 44.406 33.349 ;
     RECT  72.36 32.909 72.414 33.349 ;
     RECT  64.008 33.151 70.902 33.377 ;
     RECT  27.936 33.071 28.278 33.385 ;
     RECT  29.016 33.071 32.67 33.385 ;
     RECT  45.324 32.477 46.746 33.403 ;
     RECT  47.52 32.729 47.79 33.403 ;
     RECT  73.296 32.467 73.35 33.413 ;
     RECT  60.3 33.277 63.27 33.421 ;
     RECT  0.108 32.237 0.162 33.449 ;
     RECT  10.836 33.313 14.382 33.449 ;
     RECT  36.504 33.035 39.222 33.449 ;
     RECT  73.332 33.413 73.35 33.449 ;
     RECT  45.324 33.403 47.79 33.511 ;
     RECT  10.836 33.449 14.31 33.539 ;
     RECT  27.936 33.385 32.67 33.539 ;
     RECT  10.836 33.539 14.13 33.547 ;
     RECT  15.516 33.511 15.534 33.547 ;
     RECT  16.344 32.297 16.362 33.547 ;
     RECT  34.236 33.269 35.262 33.547 ;
     RECT  51.015 32.729 51.93 33.583 ;
     RECT  40.104 33.349 44.406 33.619 ;
     RECT  45.324 33.511 47.898 33.619 ;
     RECT  49.644 33.035 50.274 33.619 ;
     RECT  51.015 33.583 52.146 33.619 ;
     RECT  54.18 32.603 54.198 33.619 ;
     RECT  0.144 33.449 0.162 33.629 ;
     RECT  10.656 33.547 14.13 33.629 ;
     RECT  34.236 33.547 35.586 33.629 ;
     RECT  49.644 33.619 52.146 33.655 ;
     RECT  56.415 33.035 56.697 33.655 ;
     RECT  15.516 33.547 16.362 33.691 ;
     RECT  2.232 33.151 9.846 33.781 ;
     RECT  10.656 33.629 13.698 33.781 ;
     RECT  40.104 33.619 47.898 33.781 ;
     RECT  49.644 33.655 52.866 33.781 ;
     RECT  54.18 33.619 54.738 33.781 ;
     RECT  15.084 33.691 16.902 33.809 ;
     RECT  32.472 33.539 32.67 33.809 ;
     RECT  16.344 33.809 16.902 33.845 ;
     RECT  23.436 33.071 27.198 33.845 ;
     RECT  32.472 33.809 32.526 33.845 ;
     RECT  40.104 33.781 48.186 33.845 ;
     RECT  21.096 33.691 21.114 33.889 ;
     RECT  54.18 33.781 54.81 33.925 ;
     RECT  55.548 33.035 55.566 33.925 ;
     RECT  56.415 33.655 56.826 33.925 ;
     RECT  72.288 33.349 72.414 33.925 ;
     RECT  27.108 33.845 27.198 33.952 ;
     RECT  27.936 33.539 28.134 33.952 ;
     RECT  21.096 33.889 21.438 33.953 ;
     RECT  40.104 33.845 46.998 33.953 ;
     RECT  38.376 33.449 39.222 33.961 ;
     RECT  48.168 33.845 48.186 33.961 ;
     RECT  49.032 33.781 52.866 33.961 ;
     RECT  58.14 33.035 58.878 33.961 ;
     RECT  72.036 33.925 72.414 33.965 ;
     RECT  48.168 33.961 52.866 33.989 ;
     RECT  2.232 33.781 13.698 34.027 ;
     RECT  2.052 34.027 13.698 34.079 ;
     RECT  38.376 33.961 39.366 34.079 ;
     RECT  1.152 32.909 1.17 34.114 ;
     RECT  15.084 33.809 15.606 34.115 ;
     RECT  28.908 33.539 31.662 34.115 ;
     RECT  48.6 33.989 52.866 34.115 ;
     RECT  49.752 34.115 52.866 34.123 ;
     RECT  49.752 34.123 52.902 34.151 ;
     RECT  29.376 34.115 31.662 34.157 ;
     RECT  32.508 33.845 32.526 34.157 ;
     RECT  27.108 33.952 28.134 34.187 ;
     RECT  40.104 33.953 46.962 34.187 ;
     RECT  50.364 34.151 52.902 34.187 ;
     RECT  72.108 33.965 72.414 34.187 ;
     RECT  58.14 33.961 58.914 34.195 ;
     RECT  59.652 33.421 63.27 34.195 ;
     RECT  65.556 33.377 70.902 34.195 ;
     RECT  38.376 34.079 39.15 34.205 ;
     RECT  48.96 34.115 48.978 34.223 ;
     RECT  58.14 34.195 63.27 34.231 ;
     RECT  64.008 33.377 64.818 34.231 ;
     RECT  54.18 33.925 55.566 34.315 ;
     RECT  65.556 34.195 70.938 34.315 ;
     RECT  42.66 34.187 46.854 34.349 ;
     RECT  54.18 34.315 55.602 34.357 ;
     RECT  56.415 33.925 56.934 34.357 ;
     RECT  40.104 34.187 41.886 34.363 ;
     RECT  11.808 34.079 13.698 34.385 ;
     RECT  50.364 34.187 52.146 34.385 ;
     RECT  54.18 34.357 55.638 34.393 ;
     RECT  50.436 34.385 52.146 34.421 ;
     RECT  12.996 34.385 13.698 34.501 ;
     RECT  14.688 34.315 14.85 34.501 ;
     RECT  36.504 33.449 37.134 34.555 ;
     RECT  53.64 34.393 55.638 34.591 ;
     RECT  56.376 34.357 56.934 34.591 ;
     RECT  29.376 34.157 31.41 34.619 ;
     RECT  34.236 33.629 35.262 34.619 ;
     RECT  50.724 34.421 52.146 34.619 ;
     RECT  58.104 34.231 64.818 34.619 ;
     RECT  65.556 34.315 71.262 34.619 ;
     RECT  2.052 34.079 11.07 34.655 ;
     RECT  12.996 34.501 14.85 34.655 ;
     RECT  27.108 34.187 27.45 34.655 ;
     RECT  53.64 34.591 56.934 34.655 ;
     RECT  58.716 34.619 64.818 34.663 ;
     RECT  65.556 34.619 65.754 34.663 ;
     RECT  10.728 34.655 11.07 34.691 ;
     RECT  23.436 33.845 26.262 34.699 ;
     RECT  66.672 34.619 71.262 34.699 ;
     RECT  27.288 34.655 27.45 34.727 ;
     RECT  42.768 34.349 46.854 34.727 ;
     RECT  1.152 34.114 1.206 34.733 ;
     RECT  58.716 34.663 65.754 34.733 ;
     RECT  66.672 34.699 71.298 34.735 ;
     RECT  72.108 34.187 72.378 34.735 ;
     RECT  42.768 34.727 45.897 34.763 ;
     RECT  46.692 34.727 46.854 34.763 ;
     RECT  55.548 34.655 56.934 34.763 ;
     RECT  58.716 34.733 59.706 34.763 ;
     RECT  34.236 34.619 35.097 34.799 ;
     RECT  38.376 34.205 38.826 34.799 ;
     RECT  36.324 34.555 37.134 34.843 ;
     RECT  28.44 34.465 28.602 34.861 ;
     RECT  29.376 34.619 30.078 34.861 ;
     RECT  36.324 34.843 37.458 34.877 ;
     RECT  66.672 34.735 72.378 34.889 ;
     RECT  40.032 34.363 41.886 34.925 ;
     RECT  10.764 34.691 11.07 34.933 ;
     RECT  11.808 34.385 12.186 34.933 ;
     RECT  2.052 34.655 9.99 34.997 ;
     RECT  19.944 34.969 19.962 35.005 ;
     RECT  17.748 34.933 17.766 35.041 ;
     RECT  21.42 33.953 21.438 35.041 ;
     RECT  23.436 34.699 26.55 35.069 ;
     RECT  36.324 34.877 36.342 35.069 ;
     RECT  38.448 34.799 38.826 35.069 ;
     RECT  43.884 34.763 45.897 35.159 ;
     RECT  58.716 34.763 59.67 35.159 ;
     RECT  2.268 34.997 9.99 35.195 ;
     RECT  40.176 34.925 41.886 35.195 ;
     RECT  43.956 35.159 44.334 35.195 ;
     RECT  60.516 34.733 65.754 35.195 ;
     RECT  27.432 34.727 27.45 35.239 ;
     RECT  28.44 34.861 30.078 35.239 ;
     RECT  40.215 35.195 41.886 35.239 ;
     RECT  42.768 34.763 43.146 35.239 ;
     RECT  38.448 35.069 38.79 35.267 ;
     RECT  66.888 34.889 72.378 35.267 ;
     RECT  14.832 34.655 14.85 35.311 ;
     RECT  15.588 34.115 15.606 35.311 ;
     RECT  16.344 33.845 16.362 35.311 ;
     RECT  56.415 34.763 56.934 35.311 ;
     RECT  57.708 34.663 57.726 35.311 ;
     RECT  71.712 35.267 72.378 35.311 ;
     RECT  19.944 35.005 20.286 35.401 ;
     RECT  21.096 35.041 21.438 35.401 ;
     RECT  27.432 35.239 30.078 35.401 ;
     RECT  31.392 34.619 31.41 35.401 ;
     RECT  0.108 34.735 0.126 35.405 ;
     RECT  50.724 34.619 51.93 35.419 ;
     RECT  14.832 35.311 16.83 35.429 ;
     RECT  2.268 35.195 9.918 35.465 ;
     RECT  12.996 34.655 14.058 35.465 ;
     RECT  15.588 35.429 16.83 35.465 ;
     RECT  19.944 35.401 21.438 35.465 ;
     RECT  40.215 35.239 43.146 35.465 ;
     RECT  56.415 35.311 57.726 35.465 ;
     RECT  25.164 35.069 26.55 35.473 ;
     RECT  27.432 35.401 31.41 35.473 ;
     RECT  46.764 34.763 46.854 35.473 ;
     RECT  54.18 34.655 54.738 35.473 ;
     RECT  55.548 34.763 55.674 35.473 ;
     RECT  17.676 35.041 17.766 35.509 ;
     RECT  20.268 35.465 21.438 35.509 ;
     RECT  22.284 32.773 22.302 35.509 ;
     RECT  48.78 35.473 48.798 35.509 ;
     RECT  58.86 35.159 59.67 35.509 ;
     RECT  60.516 35.195 64.818 35.509 ;
     RECT  16.668 35.465 16.83 35.581 ;
     RECT  17.676 35.509 17.838 35.581 ;
     RECT  18.615 31.253 18.897 35.581 ;
     RECT  33.408 33.269 33.426 35.581 ;
     RECT  34.308 34.799 35.097 35.581 ;
     RECT  48.78 35.509 49.158 35.581 ;
     RECT  50.688 35.419 51.93 35.581 ;
     RECT  71.712 35.311 72.414 35.581 ;
     RECT  25.164 35.473 31.41 35.609 ;
     RECT  33.408 35.581 35.097 35.671 ;
     RECT  54.18 35.473 55.674 35.671 ;
     RECT  56.415 35.465 56.754 35.671 ;
     RECT  65.556 35.195 65.754 35.671 ;
     RECT  66.888 35.267 70.686 35.671 ;
     RECT  12.996 35.465 13.59 35.699 ;
     RECT  16.668 35.581 18.897 35.699 ;
     RECT  20.268 35.509 22.302 35.699 ;
     RECT  58.86 35.509 64.818 35.699 ;
     RECT  2.268 35.465 8.442 35.735 ;
     RECT  14.832 35.429 14.85 35.735 ;
     RECT  16.668 35.699 16.83 35.735 ;
     RECT  17.676 35.699 18.897 35.735 ;
     RECT  20.268 35.699 20.286 35.735 ;
     RECT  46.764 35.473 46.89 35.735 ;
     RECT  50.364 35.581 51.93 35.735 ;
     RECT  37.116 34.877 37.458 35.779 ;
     RECT  38.448 35.267 38.718 35.779 ;
     RECT  21.132 35.699 22.302 35.789 ;
     RECT  17.82 35.735 18.897 35.807 ;
     RECT  21.204 35.789 22.302 35.807 ;
     RECT  25.164 35.609 25.866 35.815 ;
     RECT  37.116 35.779 38.718 35.851 ;
     RECT  48.78 35.581 49.446 35.851 ;
     RECT  21.204 35.807 21.546 35.879 ;
     RECT  46.764 35.735 46.782 35.879 ;
     RECT  0.144 35.515 0.162 35.885 ;
     RECT  16.668 35.735 16.686 35.885 ;
     RECT  9.36 35.465 9.918 35.941 ;
     RECT  10.764 34.933 12.186 35.941 ;
     RECT  12.996 35.699 13.554 35.941 ;
     RECT  33.408 35.671 35.154 35.941 ;
     RECT  40.215 35.465 41.886 35.941 ;
     RECT  1.188 34.733 1.206 35.947 ;
     RECT  45.324 35.159 45.897 35.947 ;
     RECT  46.728 35.941 46.746 35.947 ;
     RECT  36.9 35.851 38.718 35.969 ;
     RECT  48.78 35.851 49.662 35.969 ;
     RECT  45.324 35.947 46.746 35.981 ;
     RECT  47.88 35.851 47.898 36.005 ;
     RECT  49.428 35.969 49.446 36.005 ;
     RECT  23.436 35.069 24.297 36.013 ;
     RECT  25.092 35.815 25.866 36.013 ;
     RECT  58.86 35.699 63.27 36.013 ;
     RECT  1.188 35.947 1.278 36.043 ;
     RECT  38.016 35.969 38.718 36.049 ;
     RECT  39.852 35.941 41.886 36.049 ;
     RECT  58.752 36.013 63.27 36.049 ;
     RECT  65.556 35.671 70.686 36.049 ;
     RECT  1.152 36.043 1.278 36.077 ;
     RECT  73.332 35.707 73.35 36.077 ;
     RECT  26.748 35.609 31.41 36.085 ;
     RECT  32.4 35.899 32.418 36.085 ;
     RECT  36.9 35.969 37.242 36.085 ;
     RECT  42.804 35.465 43.146 36.121 ;
     RECT  44.172 35.195 44.334 36.121 ;
     RECT  65.556 36.049 70.722 36.121 ;
     RECT  71.712 35.581 72.45 36.121 ;
     RECT  45.324 35.981 46.53 36.125 ;
     RECT  50.976 35.735 51.93 36.149 ;
     RECT  65.556 36.121 72.45 36.173 ;
     RECT  22.284 35.807 22.302 36.211 ;
     RECT  10.764 35.941 13.554 36.239 ;
     RECT  2.304 35.735 8.442 36.283 ;
     RECT  9.36 35.941 10.026 36.283 ;
     RECT  18.252 35.807 18.897 36.283 ;
     RECT  33.408 35.941 35.37 36.283 ;
     RECT  36.324 36.085 37.242 36.283 ;
     RECT  1.152 36.077 1.17 36.317 ;
     RECT  23.436 36.013 25.866 36.319 ;
     RECT  54.18 35.671 56.754 36.331 ;
     RECT  22.284 36.211 22.41 36.355 ;
     RECT  23.292 36.319 25.866 36.355 ;
     RECT  64.44 35.699 64.818 36.475 ;
     RECT  65.556 36.173 72.378 36.475 ;
     RECT  2.304 36.283 10.026 36.481 ;
     RECT  10.764 36.239 12.258 36.481 ;
     RECT  18.252 36.283 18.918 36.481 ;
     RECT  54.18 36.331 56.79 36.481 ;
     RECT  64.44 36.475 72.378 36.481 ;
     RECT  12.996 36.239 13.554 36.517 ;
     RECT  54.18 36.481 56.826 36.517 ;
     RECT  57.708 35.465 57.726 36.517 ;
     RECT  18.252 36.481 19.278 36.545 ;
     RECT  52.992 36.319 53.01 36.545 ;
     RECT  12.996 36.517 13.662 36.553 ;
     RECT  42.804 36.121 44.334 36.571 ;
     RECT  26.748 36.085 32.418 36.619 ;
     RECT  33.408 36.283 37.242 36.619 ;
     RECT  20.592 36.589 20.61 36.625 ;
     RECT  21.42 35.879 21.546 36.625 ;
     RECT  26.748 36.619 37.242 36.625 ;
     RECT  38.016 36.049 41.886 36.625 ;
     RECT  42.696 36.571 44.334 36.625 ;
     RECT  58.716 36.049 63.27 36.625 ;
     RECT  64.224 36.481 72.378 36.625 ;
     RECT  26.712 36.625 37.242 36.689 ;
     RECT  0.18 36.517 0.198 36.715 ;
     RECT  12.996 36.553 13.698 36.751 ;
     RECT  14.508 36.475 14.526 36.751 ;
     RECT  26.712 36.689 28.566 36.779 ;
     RECT  54.18 36.517 57.726 36.811 ;
     RECT  18.324 36.545 19.278 36.851 ;
     RECT  26.784 36.779 28.53 36.851 ;
     RECT  0.18 36.715 0.342 36.859 ;
     RECT  29.415 36.689 37.242 36.859 ;
     RECT  38.016 36.625 44.334 36.859 ;
     RECT  12.996 36.751 14.526 36.893 ;
     RECT  47.88 36.787 47.898 36.895 ;
     RECT  73.332 36.811 73.35 36.923 ;
     RECT  49.968 36.895 49.986 36.931 ;
     RECT  51.015 36.149 51.93 36.931 ;
     RECT  20.592 36.625 21.546 36.955 ;
     RECT  22.284 36.355 25.866 36.955 ;
     RECT  20.592 36.955 25.866 36.959 ;
     RECT  29.415 36.859 44.334 37.003 ;
     RECT  2.304 36.481 12.258 37.021 ;
     RECT  12.996 36.893 13.986 37.021 ;
     RECT  18.324 36.851 19.134 37.049 ;
     RECT  20.592 36.959 25.074 37.049 ;
     RECT  26.784 36.851 28.278 37.049 ;
     RECT  45.324 36.125 45.897 37.049 ;
     RECT  49.968 36.931 51.93 37.049 ;
     RECT  54.036 36.811 57.726 37.049 ;
     RECT  54.108 37.049 57.726 37.057 ;
     RECT  18.324 37.049 18.954 37.085 ;
     RECT  29.415 37.003 44.406 37.157 ;
     RECT  15.588 35.465 15.606 37.165 ;
     RECT  32.364 37.157 44.406 37.192 ;
     RECT  45.36 37.049 45.897 37.193 ;
     RECT  50.328 37.049 51.93 37.193 ;
     RECT  2.304 37.021 13.986 37.195 ;
     RECT  29.415 37.157 31.59 37.319 ;
     RECT  54.108 37.057 57.978 37.339 ;
     RECT  58.716 36.625 72.378 37.339 ;
     RECT  2.268 37.195 13.986 37.355 ;
     RECT  45.432 37.193 45.897 37.355 ;
     RECT  47.556 36.895 47.898 37.355 ;
     RECT  48.996 36.931 49.014 37.363 ;
     RECT  0.18 36.859 0.558 37.387 ;
     RECT  10.908 37.355 13.986 37.391 ;
     RECT  47.556 37.355 47.862 37.427 ;
     RECT  21.096 37.049 21.546 37.463 ;
     RECT  46.764 37.057 46.782 37.463 ;
     RECT  15.264 37.165 15.606 37.471 ;
     RECT  0.18 37.387 0.666 37.517 ;
     RECT  54.108 37.339 72.378 37.517 ;
     RECT  15.192 37.471 15.606 37.561 ;
     RECT  2.268 37.355 10.134 37.579 ;
     RECT  2.196 37.579 10.134 37.589 ;
     RECT  11.016 37.391 13.986 37.589 ;
     RECT  18.615 37.085 18.954 37.589 ;
     RECT  47.52 37.471 47.538 37.589 ;
     RECT  2.196 37.589 9.99 37.625 ;
     RECT  15.192 37.561 15.822 37.625 ;
     RECT  32.364 37.192 44.622 37.625 ;
     RECT  48.996 37.363 49.23 37.625 ;
     RECT  54.108 37.517 63.918 37.625 ;
     RECT  50.724 37.193 51.93 37.633 ;
     RECT  22.392 37.049 25.074 37.705 ;
     RECT  25.848 36.959 25.866 37.705 ;
     RECT  49.032 37.625 49.23 37.733 ;
     RECT  38.376 37.625 44.478 37.769 ;
     RECT  2.196 37.625 9.414 37.771 ;
     RECT  26.856 37.049 28.242 37.831 ;
     RECT  15.588 37.625 15.822 37.858 ;
     RECT  17.136 37.669 17.154 37.859 ;
     RECT  41.868 37.769 44.478 37.859 ;
     RECT  50.724 37.633 52.254 37.867 ;
     RECT  54.108 37.625 57.726 37.867 ;
     RECT  11.088 37.589 13.986 37.895 ;
     RECT  32.364 37.625 37.566 37.895 ;
     RECT  41.868 37.859 42.894 37.901 ;
     RECT  45.615 37.355 45.897 37.903 ;
     RECT  46.728 37.741 46.746 37.903 ;
     RECT  15.588 37.858 15.858 37.931 ;
     RECT  43.74 37.859 44.478 37.931 ;
     RECT  32.76 37.895 37.566 37.949 ;
     RECT  2.052 37.771 9.414 37.963 ;
     RECT  54 37.867 57.726 37.963 ;
     RECT  43.74 37.931 44.334 37.967 ;
     RECT  0.18 37.517 0.27 37.975 ;
     RECT  26.676 37.831 28.242 38.003 ;
     RECT  29.415 37.319 31.482 38.003 ;
     RECT  45.615 37.903 46.746 38.039 ;
     RECT  21.348 37.463 21.546 38.101 ;
     RECT  22.392 37.705 25.866 38.101 ;
     RECT  11.628 37.895 13.986 38.129 ;
     RECT  26.748 38.003 27.486 38.129 ;
     RECT  32.76 37.949 33.246 38.129 ;
     RECT  38.376 37.769 41.022 38.129 ;
     RECT  41.904 37.901 42.894 38.129 ;
     RECT  21.348 38.101 25.866 38.155 ;
     RECT  11.88 38.129 13.986 38.165 ;
     RECT  46.62 38.039 46.746 38.165 ;
     RECT  64.728 37.517 72.378 38.165 ;
     RECT  50.724 37.867 53.082 38.173 ;
     RECT  27.36 38.129 27.486 38.189 ;
     RECT  41.904 38.129 42.858 38.189 ;
     RECT  66.78 38.165 72.378 38.189 ;
     RECT  21.348 38.155 26.01 38.201 ;
     RECT  28.44 38.011 28.458 38.201 ;
     RECT  34.164 37.949 37.566 38.201 ;
     RECT  50.544 38.173 53.082 38.245 ;
     RECT  53.964 37.963 57.726 38.245 ;
     RECT  16.704 37.975 16.794 38.273 ;
     RECT  32.76 38.129 33.174 38.309 ;
     RECT  42.516 38.189 42.714 38.309 ;
     RECT  50.544 38.245 57.726 38.309 ;
     RECT  1.692 37.963 9.414 38.371 ;
     RECT  11.952 38.165 13.986 38.395 ;
     RECT  58.716 37.625 63.918 38.395 ;
     RECT  64.728 38.165 65.754 38.395 ;
     RECT  16.776 38.273 16.794 38.399 ;
     RECT  49.356 38.281 49.374 38.435 ;
     RECT  1.692 38.371 9.522 38.443 ;
     RECT  58.716 38.395 65.754 38.443 ;
     RECT  51.015 38.309 57.726 38.471 ;
     RECT  54.072 38.471 57.726 38.515 ;
     RECT  58.572 38.443 65.754 38.515 ;
     RECT  18.615 37.589 18.897 38.551 ;
     RECT  38.376 38.129 40.914 38.579 ;
     RECT  73.332 38.347 73.35 38.579 ;
     RECT  1.692 38.443 9.81 38.635 ;
     RECT  21.348 38.201 25.866 38.669 ;
     RECT  27.36 38.189 27.414 38.669 ;
     RECT  54.072 38.515 65.754 38.669 ;
     RECT  1.296 38.635 9.81 38.705 ;
     RECT  11.952 38.395 14.418 38.705 ;
     RECT  23.436 38.669 25.866 38.705 ;
     RECT  1.296 38.705 6.066 38.731 ;
     RECT  54.108 38.669 65.754 38.741 ;
     RECT  15.588 37.931 15.678 38.749 ;
     RECT  23.436 38.705 25.722 38.765 ;
     RECT  18.615 38.551 18.954 38.785 ;
     RECT  15.372 38.749 16.038 38.821 ;
     RECT  0.108 37.975 0.27 38.923 ;
     RECT  54.252 38.741 65.754 38.939 ;
     RECT  18.615 38.785 19.134 38.947 ;
     RECT  21.348 38.669 22.41 38.975 ;
     RECT  42.696 38.309 42.714 39.019 ;
     RECT  43.74 37.967 43.758 39.019 ;
     RECT  1.188 38.731 6.066 39.047 ;
     RECT  0.108 38.923 0.342 39.053 ;
     RECT  6.804 38.705 9.81 39.055 ;
     RECT  51.015 38.471 53.262 39.083 ;
     RECT  6.804 39.055 10.026 39.091 ;
     RECT  10.872 38.515 10.89 39.091 ;
     RECT  18.615 38.947 19.242 39.091 ;
     RECT  34.164 38.201 35.097 39.091 ;
     RECT  15.336 38.821 16.038 39.181 ;
     RECT  17.028 39.091 17.046 39.181 ;
     RECT  52.56 39.083 53.262 39.209 ;
     RECT  15.336 39.181 17.046 39.217 ;
     RECT  0.108 39.053 0.306 39.245 ;
     RECT  33.984 39.091 35.097 39.245 ;
     RECT  54.252 38.939 63.774 39.245 ;
     RECT  51.015 39.083 51.297 39.325 ;
     RECT  6.804 39.091 10.998 39.361 ;
     RECT  20.376 39.091 20.394 39.361 ;
     RECT  21.348 38.975 21.546 39.361 ;
     RECT  54.468 39.245 63.774 39.389 ;
     RECT  6.804 39.361 11.034 39.451 ;
     RECT  11.952 38.705 14.022 39.451 ;
     RECT  18.615 39.091 19.494 39.451 ;
     RECT  50.724 39.325 51.297 39.479 ;
     RECT  0.108 39.245 0.198 39.533 ;
     RECT  14.832 39.217 17.046 39.559 ;
     RECT  14.832 39.559 17.55 39.589 ;
     RECT  18.576 39.451 19.53 39.589 ;
     RECT  6.804 39.451 14.094 39.631 ;
     RECT  14.832 39.589 19.53 39.631 ;
     RECT  20.376 39.361 21.546 39.631 ;
     RECT  55.62 39.389 63.774 39.659 ;
     RECT  64.512 38.939 65.754 39.721 ;
     RECT  55.764 39.659 63.774 39.739 ;
     RECT  64.512 39.721 65.79 39.739 ;
     RECT  54.468 39.389 54.846 39.857 ;
     RECT  66.78 38.189 70.938 39.865 ;
     RECT  55.764 39.739 65.79 39.893 ;
     RECT  22.392 38.975 22.41 39.901 ;
     RECT  23.436 38.765 24.297 39.901 ;
     RECT  39.168 38.579 40.914 39.901 ;
     RECT  55.764 39.893 56.754 39.917 ;
     RECT  6.804 39.631 21.546 39.991 ;
     RECT  22.392 39.901 24.297 39.991 ;
     RECT  0.108 39.533 0.126 40.013 ;
     RECT  57.528 39.893 65.79 40.061 ;
     RECT  57.96 40.061 65.79 40.109 ;
     RECT  66.744 39.865 70.938 40.171 ;
     RECT  71.676 38.189 72.378 40.171 ;
     RECT  73.332 39.787 73.35 40.199 ;
     RECT  39.168 39.901 41.058 40.289 ;
     RECT  27.36 38.669 27.378 40.297 ;
     RECT  58.14 40.109 65.79 40.361 ;
     RECT  1.692 39.047 6.066 40.397 ;
     RECT  26.748 40.297 27.378 40.397 ;
     RECT  2.268 40.397 6.066 40.441 ;
     RECT  6.804 39.991 24.297 40.441 ;
     RECT  66.744 40.171 72.378 40.469 ;
     RECT  42.696 39.019 43.758 40.567 ;
     RECT  71.856 40.469 72.378 40.589 ;
     RECT  66.744 40.469 70.83 40.595 ;
     RECT  66.744 40.595 70.722 40.603 ;
     RECT  42.696 40.567 43.974 40.639 ;
     RECT  42.696 40.639 44.01 40.739 ;
     RECT  58.176 40.361 65.79 40.829 ;
     RECT  42.696 40.739 43.938 40.877 ;
     RECT  42.696 40.877 43.758 40.973 ;
     RECT  64.26 40.829 65.79 40.981 ;
     RECT  66.672 40.603 70.722 40.981 ;
     RECT  43.596 40.973 43.758 41.021 ;
     RECT  36.072 38.201 37.566 41.035 ;
     RECT  38.376 38.579 38.394 41.035 ;
     RECT  2.268 40.441 24.297 41.099 ;
     RECT  36.072 41.035 38.394 41.099 ;
     RECT  0.324 41.035 0.342 41.131 ;
     RECT  54.468 39.857 54.81 41.243 ;
     RECT  16.416 41.099 22.518 41.279 ;
     RECT  16.416 41.279 22.41 41.369 ;
     RECT  16.416 41.369 21.654 41.405 ;
     RECT  16.416 41.405 19.35 41.411 ;
     RECT  2.268 41.099 15.678 41.419 ;
     RECT  72.072 40.589 72.378 41.419 ;
     RECT  73.332 41.131 73.35 41.449 ;
     RECT  64.26 40.981 70.722 41.485 ;
     RECT  58.176 40.829 63.414 41.501 ;
     RECT  20.16 41.405 21.654 41.549 ;
     RECT  64.26 41.485 70.758 41.549 ;
     RECT  16.416 41.411 17.154 41.639 ;
     RECT  20.16 41.549 21.546 41.639 ;
     RECT  16.992 41.639 17.01 41.675 ;
     RECT  20.52 41.639 21.546 41.675 ;
     RECT  64.404 41.549 70.758 41.683 ;
     RECT  64.404 41.683 70.938 41.711 ;
     RECT  1.944 41.419 15.678 41.747 ;
     RECT  0.18 41.131 0.342 41.755 ;
     RECT  1.944 41.747 14.13 41.783 ;
     RECT  0.144 41.755 0.342 41.803 ;
     RECT  15.228 41.747 15.678 41.819 ;
     RECT  72.072 41.419 72.414 41.819 ;
     RECT  72.072 41.819 72.378 41.899 ;
     RECT  11.664 41.783 14.13 41.909 ;
     RECT  58.788 41.501 63.414 41.909 ;
     RECT  0.144 41.803 0.414 41.933 ;
     RECT  11.664 41.909 14.094 41.945 ;
     RECT  21.276 41.675 21.546 41.945 ;
     RECT  15.336 41.819 15.678 41.953 ;
     RECT  0.396 41.933 0.414 41.981 ;
     RECT  71.784 41.899 72.378 41.995 ;
     RECT  15.336 41.953 15.714 42.053 ;
     RECT  54.468 41.243 54.738 42.061 ;
     RECT  60.192 41.909 63.414 42.061 ;
     RECT  15.336 42.053 15.678 42.089 ;
     RECT  58.788 41.909 58.806 42.089 ;
     RECT  73.296 41.449 73.35 42.125 ;
     RECT  1.944 41.783 10.926 42.179 ;
     RECT  13.215 41.945 14.094 42.179 ;
     RECT  54.468 42.061 54.81 42.179 ;
     RECT  60.192 42.061 63.558 42.179 ;
     RECT  73.332 42.125 73.35 42.179 ;
     RECT  71.748 41.995 72.378 42.323 ;
     RECT  71.784 42.323 72.378 42.359 ;
     RECT  64.404 41.711 64.638 42.449 ;
     RECT  1.944 42.179 10.674 42.557 ;
     RECT  11.664 41.945 12.474 42.601 ;
     RECT  39.168 40.289 40.914 42.719 ;
     RECT  65.592 41.711 70.938 42.719 ;
     RECT  38.376 41.099 38.394 42.727 ;
     RECT  54.468 42.179 54.486 42.727 ;
     RECT  55.764 39.917 56.697 42.727 ;
     RECT  60.192 42.179 63.27 42.749 ;
     RECT  72.144 42.359 72.378 42.749 ;
     RECT  54.396 42.727 54.486 42.755 ;
     RECT  43.74 41.021 43.758 42.763 ;
     RECT  43.74 42.763 43.866 42.791 ;
     RECT  11.412 42.601 12.474 42.835 ;
     RECT  13.215 42.179 13.986 42.835 ;
     RECT  39.564 42.719 40.914 42.989 ;
     RECT  42.696 40.973 42.714 42.989 ;
     RECT  72.36 42.749 72.378 42.989 ;
     RECT  65.7 42.719 70.938 43.061 ;
     RECT  2.268 42.557 10.674 43.069 ;
     RECT  11.412 42.835 13.986 43.069 ;
     RECT  65.736 43.061 70.938 43.097 ;
     RECT  2.268 43.069 13.986 43.099 ;
     RECT  15.336 42.089 15.606 43.099 ;
     RECT  34.164 39.245 35.097 43.105 ;
     RECT  34.056 43.105 35.097 43.231 ;
     RECT  36.072 41.099 37.566 43.259 ;
     RECT  43.776 42.791 43.866 43.259 ;
     RECT  34.056 43.231 35.19 43.291 ;
     RECT  36.072 43.259 37.026 43.291 ;
     RECT  2.268 43.099 15.606 43.295 ;
     RECT  31.464 38.003 31.482 43.303 ;
     RECT  32.76 38.309 32.778 43.303 ;
     RECT  31.464 43.303 32.778 43.331 ;
     RECT  65.736 43.097 70.83 43.439 ;
     RECT  34.056 43.291 37.026 43.529 ;
     RECT  66.744 43.439 70.83 43.529 ;
     RECT  0.468 43.411 0.486 43.609 ;
     RECT  2.304 43.295 15.606 43.709 ;
     RECT  0.468 43.609 0.558 43.723 ;
     RECT  2.304 43.709 6.354 43.835 ;
     RECT  38.376 42.727 38.79 43.843 ;
     RECT  39.564 42.989 40.497 43.843 ;
     RECT  0.324 43.723 0.558 44.045 ;
     RECT  7.236 43.709 15.606 44.069 ;
     RECT  0.324 44.045 0.522 44.113 ;
     RECT  0.18 44.113 0.522 44.141 ;
     RECT  2.304 43.835 4.662 44.185 ;
     RECT  14.868 44.069 15.606 44.221 ;
     RECT  67.104 43.529 70.83 44.221 ;
     RECT  67.104 44.221 71.082 44.311 ;
     RECT  2.268 44.185 4.662 44.333 ;
     RECT  0.18 44.141 0.486 44.383 ;
     RECT  0.144 44.383 0.486 44.419 ;
     RECT  66.888 44.311 71.082 44.419 ;
     RECT  0.108 44.419 0.486 44.429 ;
     RECT  2.304 44.333 4.662 44.653 ;
     RECT  5.472 43.835 6.354 44.653 ;
     RECT  66.852 44.419 71.118 44.683 ;
     RECT  2.304 44.653 6.354 44.689 ;
     RECT  7.236 44.069 13.986 44.689 ;
     RECT  66.672 44.683 71.118 44.761 ;
     RECT  22.392 41.369 22.41 44.789 ;
     RECT  66.672 44.761 71.154 44.851 ;
     RECT  34.056 43.529 36.99 44.879 ;
     RECT  66.672 44.851 71.838 44.923 ;
     RECT  14.868 44.221 15.75 44.959 ;
     RECT  38.376 43.843 40.497 44.995 ;
     RECT  36.072 44.879 36.99 45.031 ;
     RECT  61.815 42.749 63.27 45.031 ;
     RECT  64.62 42.449 64.638 45.031 ;
     RECT  58.752 45.031 59.202 45.115 ;
     RECT  2.304 44.689 13.986 45.121 ;
     RECT  14.868 44.959 15.822 45.149 ;
     RECT  58.248 45.115 59.202 45.149 ;
     RECT  60.192 42.749 60.93 45.157 ;
     RECT  61.74 45.031 63.45 45.157 ;
     RECT  21.528 41.945 21.546 45.185 ;
     RECT  65.736 43.439 65.754 45.211 ;
     RECT  66.672 44.923 72.414 45.211 ;
     RECT  34.056 44.879 35.19 45.293 ;
     RECT  36.072 45.031 37.422 45.301 ;
     RECT  60.192 45.157 63.45 45.301 ;
     RECT  64.368 45.031 64.638 45.301 ;
     RECT  2.304 45.121 14.094 45.355 ;
     RECT  51.015 39.479 51.297 45.403 ;
     RECT  36.072 45.301 37.566 45.419 ;
     RECT  36.072 45.419 37.386 45.455 ;
     RECT  2.268 45.355 14.094 45.547 ;
     RECT  65.736 45.211 72.414 45.547 ;
     RECT  1.728 45.547 14.094 45.571 ;
     RECT  14.868 45.149 14.958 45.571 ;
     RECT  50.904 45.403 51.534 45.599 ;
     RECT  60.192 45.301 64.638 45.643 ;
     RECT  59.76 45.643 64.638 45.689 ;
     RECT  54.396 42.755 54.414 45.797 ;
     RECT  49.32 45.733 49.338 45.805 ;
     RECT  1.728 45.571 14.958 45.931 ;
     RECT  15.732 45.149 15.822 45.931 ;
     RECT  64.512 45.689 64.638 45.931 ;
     RECT  65.592 45.547 72.414 45.931 ;
     RECT  49.32 45.805 49.554 45.959 ;
     RECT  58.248 45.149 58.806 45.959 ;
     RECT  64.512 45.931 72.414 45.959 ;
     RECT  50.904 45.599 51.297 45.967 ;
     RECT  46.764 45.157 46.782 45.995 ;
     RECT  49.32 45.959 49.338 45.995 ;
     RECT  52.38 45.841 52.398 46.031 ;
     RECT  0.108 44.429 0.198 46.039 ;
     RECT  50.724 45.967 51.297 46.139 ;
     RECT  42.588 43.105 42.606 46.171 ;
     RECT  43.776 43.259 43.794 46.171 ;
     RECT  0.108 46.039 0.558 46.253 ;
     RECT  64.62 45.959 72.414 46.253 ;
     RECT  25.704 38.765 25.722 46.265 ;
     RECT  58.716 45.959 58.806 46.309 ;
     RECT  59.76 45.689 59.994 46.309 ;
     RECT  55.692 42.727 56.697 46.337 ;
     RECT  55.728 46.337 56.697 46.373 ;
     RECT  58.716 46.309 59.994 46.373 ;
     RECT  41.868 46.171 42.606 46.381 ;
     RECT  43.344 46.171 43.794 46.381 ;
     RECT  23.436 41.099 24.297 46.409 ;
     RECT  61.056 45.689 63.63 46.471 ;
     RECT  54.72 45.841 54.81 46.499 ;
     RECT  64.62 46.253 72.378 46.499 ;
     RECT  61.056 46.471 63.882 46.501 ;
     RECT  60.876 46.501 63.882 46.507 ;
     RECT  58.716 46.373 59.526 46.535 ;
     RECT  1.728 45.931 16.218 46.651 ;
     RECT  54.792 46.499 54.81 46.679 ;
     RECT  41.868 46.381 43.794 46.685 ;
     RECT  58.716 46.535 59.31 46.685 ;
     RECT  41.868 46.685 42.678 46.733 ;
     RECT  29.415 38.003 30.078 46.741 ;
     RECT  34.056 45.293 35.097 46.741 ;
     RECT  60.264 46.507 63.882 46.747 ;
     RECT  1.152 46.651 16.218 46.769 ;
     RECT  38.34 44.995 40.497 46.777 ;
     RECT  64.98 46.499 72.378 46.829 ;
     RECT  33.84 46.741 35.097 46.849 ;
     RECT  36.072 45.455 36.99 46.849 ;
     RECT  38.304 46.777 40.497 46.849 ;
     RECT  29.415 46.741 30.114 46.877 ;
     RECT  20.376 44.311 20.394 46.885 ;
     RECT  48.564 46.741 48.582 46.885 ;
     RECT  58.716 46.685 59.022 46.886 ;
     RECT  33.768 46.849 35.097 46.891 ;
     RECT  36.072 46.849 40.497 46.987 ;
     RECT  1.152 46.769 14.13 47.039 ;
     RECT  66.456 46.829 72.378 47.039 ;
     RECT  20.16 46.885 20.394 47.047 ;
     RECT  35.892 46.987 40.497 47.075 ;
     RECT  66.528 47.039 72.378 47.075 ;
     RECT  48.348 46.885 48.582 47.083 ;
     RECT  45.615 38.039 45.897 47.119 ;
     RECT  55.62 47.083 55.638 47.119 ;
     RECT  31.464 43.331 32.166 47.131 ;
     RECT  20.16 47.047 20.466 47.147 ;
     RECT  0.108 46.253 0.342 47.155 ;
     RECT  1.152 47.039 13.914 47.155 ;
     RECT  17.208 47.047 17.226 47.155 ;
     RECT  31.464 47.131 32.238 47.191 ;
     RECT  33.084 46.891 35.097 47.191 ;
     RECT  35.892 47.075 36.99 47.191 ;
     RECT  43.776 46.685 43.794 47.191 ;
     RECT  60.264 46.747 64.206 47.275 ;
     RECT  64.98 46.829 65.646 47.275 ;
     RECT  43.776 47.191 44.226 47.309 ;
     RECT  46.944 47.011 47.178 47.309 ;
     RECT  66.564 47.075 72.378 47.309 ;
     RECT  43.776 47.309 44.082 47.315 ;
     RECT  17.136 47.155 17.226 47.317 ;
     RECT  17.964 41.411 19.35 47.317 ;
     RECT  24.015 46.409 24.297 47.317 ;
     RECT  38.232 47.075 40.497 47.317 ;
     RECT  17.136 47.317 19.35 47.353 ;
     RECT  20.16 47.147 20.394 47.353 ;
     RECT  60.264 47.275 65.646 47.353 ;
     RECT  38.232 47.317 40.878 47.389 ;
     RECT  51.015 46.139 51.297 47.389 ;
     RECT  73.332 44.995 73.35 47.405 ;
     RECT  29.415 46.877 29.754 47.419 ;
     RECT  27.36 40.397 27.378 47.461 ;
     RECT  42.588 46.733 42.678 47.461 ;
     RECT  43.776 47.315 43.794 47.461 ;
     RECT  45.144 47.119 45.897 47.461 ;
     RECT  49.5 46.813 49.518 47.461 ;
     RECT  14.868 46.769 16.218 47.551 ;
     RECT  17.136 47.353 20.394 47.551 ;
     RECT  31.464 47.191 36.99 47.579 ;
     RECT  47.988 47.083 48.582 47.579 ;
     RECT  49.5 47.461 49.698 47.579 ;
     RECT  59.868 47.353 65.646 47.579 ;
     RECT  51.015 47.389 51.462 47.587 ;
     RECT  53.424 47.389 53.442 47.587 ;
     RECT  38.232 47.389 41.13 47.6 ;
     RECT  47.988 47.579 48.366 47.615 ;
     RECT  49.5 47.579 49.518 47.615 ;
     RECT  55.44 47.119 55.638 47.615 ;
     RECT  66.636 47.309 72.378 47.615 ;
     RECT  23.328 47.317 24.297 47.623 ;
     RECT  26.784 47.461 27.378 47.623 ;
     RECT  46.944 47.309 47.106 47.623 ;
     RECT  58.716 46.886 58.986 47.623 ;
     RECT  59.868 47.579 60.642 47.623 ;
     RECT  31.464 47.579 35.154 47.651 ;
     RECT  25.92 46.921 25.938 47.659 ;
     RECT  29.088 47.419 29.754 47.659 ;
     RECT  53.208 47.587 53.442 47.659 ;
     RECT  29.088 47.659 30.33 47.695 ;
     RECT  53.208 47.659 53.514 47.695 ;
     RECT  25.74 47.659 25.938 47.731 ;
     RECT  26.748 47.623 27.378 47.731 ;
     RECT  42.588 47.461 43.794 47.731 ;
     RECT  46.764 47.623 47.106 47.731 ;
     RECT  50.724 47.587 51.462 47.731 ;
     RECT  0.108 47.155 13.914 47.789 ;
     RECT  1.152 47.789 13.914 47.821 ;
     RECT  14.868 47.551 20.394 47.821 ;
     RECT  21.852 47.317 21.87 47.821 ;
     RECT  36.072 47.579 36.99 47.857 ;
     RECT  38.232 47.6 41.418 47.857 ;
     RECT  53.208 47.695 54.162 47.885 ;
     RECT  58.716 47.623 60.642 47.885 ;
     RECT  29.088 47.695 30.726 47.929 ;
     RECT  31.464 47.651 35.097 47.929 ;
     RECT  42.408 47.731 43.794 47.929 ;
     RECT  45 47.461 45.897 47.929 ;
     RECT  46.692 47.731 47.106 47.929 ;
     RECT  25.128 47.731 25.938 47.965 ;
     RECT  54.144 47.885 54.162 47.965 ;
     RECT  36.072 47.857 41.418 48.001 ;
     RECT  50.724 47.731 51.642 48.001 ;
     RECT  45 47.929 47.106 48.029 ;
     RECT  56.415 46.373 56.697 48.091 ;
     RECT  61.596 47.579 65.646 48.091 ;
     RECT  22.824 47.623 24.297 48.119 ;
     RECT  36.072 48.001 41.562 48.119 ;
     RECT  50.724 48.001 51.822 48.119 ;
     RECT  54.144 47.965 55.098 48.119 ;
     RECT  21.852 47.821 22.05 48.155 ;
     RECT  22.824 48.119 23.166 48.155 ;
     RECT  36.072 48.119 41.418 48.155 ;
     RECT  50.724 48.119 51.354 48.155 ;
     RECT  54.144 48.119 54.594 48.155 ;
     RECT  1.152 47.821 20.394 48.187 ;
     RECT  45 48.029 47.07 48.199 ;
     RECT  29.088 47.929 35.097 48.263 ;
     RECT  0.108 47.789 0.342 48.269 ;
     RECT  24.015 48.119 24.297 48.271 ;
     RECT  25.056 47.965 25.938 48.271 ;
     RECT  26.676 47.731 27.378 48.271 ;
     RECT  42.372 47.929 43.794 48.271 ;
     RECT  44.532 48.199 47.07 48.271 ;
     RECT  61.596 48.091 65.754 48.361 ;
     RECT  66.78 47.615 72.378 48.361 ;
     RECT  0.324 48.269 0.342 48.365 ;
     RECT  56.124 48.091 56.697 48.379 ;
     RECT  42.372 48.271 47.07 48.389 ;
     RECT  24.015 48.271 27.378 48.425 ;
     RECT  29.088 48.263 30.006 48.425 ;
     RECT  45.288 48.389 47.07 48.425 ;
     RECT  50.724 48.155 51.297 48.425 ;
     RECT  56.088 48.379 56.697 48.425 ;
     RECT  22.824 48.155 22.95 48.433 ;
     RECT  56.268 48.425 56.697 48.461 ;
     RECT  1.152 48.187 20.466 48.469 ;
     RECT  30.744 48.263 35.097 48.475 ;
     RECT  30.744 48.475 35.118 48.533 ;
     RECT  1.152 48.469 20.934 48.541 ;
     RECT  24.015 48.425 25.218 48.653 ;
     RECT  22.068 48.433 22.95 48.659 ;
     RECT  29.415 48.425 30.006 48.659 ;
     RECT  42.372 48.389 44.55 48.659 ;
     RECT  58.716 47.885 60.57 48.659 ;
     RECT  61.596 48.361 72.378 48.667 ;
     RECT  29.415 48.659 29.754 48.695 ;
     RECT  30.78 48.533 35.118 48.695 ;
     RECT  41.256 48.155 41.418 48.695 ;
     RECT  42.372 48.659 44.442 48.695 ;
     RECT  1.152 48.541 21.006 48.703 ;
     RECT  58.788 48.659 60.57 48.703 ;
     RECT  45.36 48.425 47.07 48.767 ;
     RECT  45.615 48.767 47.07 48.775 ;
     RECT  33.948 48.695 35.118 48.811 ;
     RECT  42.372 48.695 43.902 48.811 ;
     RECT  22.068 48.659 22.914 48.965 ;
     RECT  36.072 48.155 40.497 48.965 ;
     RECT  45.615 48.775 47.142 48.965 ;
     RECT  30.816 48.695 33.21 48.989 ;
     RECT  22.068 48.965 22.878 49.001 ;
     RECT  24.015 48.653 25.182 49.001 ;
     RECT  33.948 48.811 35.19 49.001 ;
     RECT  38.376 48.965 40.497 49.001 ;
     RECT  42.156 48.811 43.902 49.001 ;
     RECT  45.615 48.965 46.602 49.001 ;
     RECT  54.18 48.155 54.594 49.001 ;
     RECT  22.068 49.001 22.338 49.009 ;
     RECT  73.332 48.973 73.35 49.037 ;
     RECT  1.152 48.703 21.078 49.045 ;
     RECT  21.996 49.009 22.338 49.045 ;
     RECT  24.015 49.001 24.297 49.045 ;
     RECT  34.38 49.001 35.19 49.081 ;
     RECT  38.556 49.001 40.497 49.081 ;
     RECT  41.256 48.695 41.346 49.081 ;
     RECT  58.788 48.703 60.642 49.081 ;
     RECT  61.56 48.667 72.378 49.081 ;
     RECT  29.415 48.695 29.697 49.171 ;
     RECT  58.788 49.081 72.378 49.171 ;
     RECT  30.816 48.989 32.31 49.199 ;
     RECT  42.156 49.001 42.966 49.199 ;
     RECT  58.788 49.171 72.414 49.199 ;
     RECT  29.16 49.171 29.697 49.229 ;
     RECT  1.152 49.045 22.338 49.235 ;
     RECT  38.556 49.081 41.346 49.235 ;
     RECT  54.792 49.081 54.81 49.271 ;
     RECT  0.324 49.099 0.342 49.291 ;
     RECT  23.76 49.045 24.297 49.315 ;
     RECT  26.784 48.425 27.378 49.315 ;
     RECT  43.776 49.001 43.902 49.379 ;
     RECT  58.788 49.199 62.91 49.379 ;
     RECT  23.688 49.315 24.297 49.441 ;
     RECT  34.38 49.081 35.262 49.441 ;
     RECT  36.072 48.965 37.566 49.441 ;
     RECT  1.404 49.235 9.774 49.469 ;
     RECT  10.8 49.235 22.338 49.469 ;
     RECT  26.712 49.315 27.378 49.469 ;
     RECT  30.816 49.199 32.238 49.469 ;
     RECT  33.12 48.989 33.21 49.469 ;
     RECT  43.776 49.379 43.83 49.469 ;
     RECT  29.232 49.229 29.697 49.505 ;
     RECT  30.816 49.469 30.87 49.513 ;
     RECT  31.68 49.469 31.77 49.541 ;
     RECT  58.788 49.379 59.49 49.541 ;
     RECT  31.752 49.541 31.77 49.565 ;
     RECT  34.38 49.441 37.566 49.577 ;
     RECT  43.812 49.469 43.83 49.577 ;
     RECT  38.556 49.235 41.022 49.739 ;
     RECT  42.408 49.199 42.966 49.739 ;
     RECT  10.8 49.469 21.87 49.757 ;
     RECT  34.776 49.577 37.566 49.775 ;
     RECT  25.236 49.711 25.254 49.783 ;
     RECT  66.132 49.199 72.414 49.805 ;
     RECT  38.556 49.739 40.497 49.811 ;
     RECT  66.132 49.805 72.378 49.811 ;
     RECT  22.716 49.747 22.878 49.855 ;
     RECT  23.616 49.441 24.297 49.855 ;
     RECT  18.216 49.757 21.87 49.883 ;
     RECT  30.78 49.513 30.87 49.883 ;
     RECT  42.408 49.739 42.498 49.883 ;
     RECT  36.972 49.775 37.566 49.891 ;
     RECT  38.556 49.811 38.862 49.891 ;
     RECT  36.972 49.891 38.862 49.919 ;
     RECT  63.72 49.199 65.394 49.981 ;
     RECT  34.776 49.775 36.09 50.009 ;
     RECT  42.408 49.883 42.426 50.009 ;
     RECT  63.72 49.981 65.718 50.009 ;
     RECT  10.8 49.757 17.442 50.045 ;
     RECT  34.776 50.009 35.622 50.045 ;
     RECT  14.76 50.045 17.442 50.081 ;
     RECT  34.776 50.045 35.442 50.081 ;
     RECT  10.8 50.045 13.806 50.093 ;
     RECT  14.832 50.081 15.102 50.117 ;
     RECT  34.776 50.081 35.097 50.117 ;
     RECT  37.656 49.919 38.862 50.117 ;
     RECT  1.404 49.469 8.982 50.153 ;
     RECT  30.852 49.883 30.87 50.153 ;
     RECT  39.708 49.811 40.497 50.153 ;
     RECT  60.3 49.379 62.91 50.155 ;
     RECT  25.2 49.783 25.362 50.161 ;
     RECT  22.716 49.855 24.297 50.203 ;
     RECT  18.615 49.883 21.87 50.251 ;
     RECT  22.644 50.203 24.297 50.251 ;
     RECT  25.128 50.161 25.362 50.279 ;
     RECT  38.088 50.117 38.862 50.279 ;
     RECT  25.128 50.279 25.146 50.287 ;
     RECT  58.716 49.621 58.734 50.287 ;
     RECT  59.472 49.541 59.49 50.287 ;
     RECT  2.268 50.153 8.982 50.315 ;
     RECT  18.615 50.251 24.297 50.315 ;
     RECT  25.056 50.287 25.146 50.315 ;
     RECT  0.108 49.291 0.342 50.381 ;
     RECT  25.056 50.315 25.074 50.387 ;
     RECT  58.716 50.287 59.49 50.395 ;
     RECT  60.3 50.155 63.486 50.395 ;
     RECT  14.832 50.117 14.85 50.423 ;
     RECT  2.304 50.315 8.982 50.431 ;
     RECT  9.756 49.469 9.774 50.431 ;
     RECT  21.672 50.315 24.297 50.431 ;
     RECT  26.748 49.469 27.378 50.431 ;
     RECT  2.304 50.431 9.774 50.521 ;
     RECT  18.615 50.315 20.538 50.549 ;
     RECT  21.672 50.431 24.714 50.549 ;
     RECT  38.088 50.279 38.61 50.549 ;
     RECT  58.716 50.395 63.486 50.549 ;
     RECT  64.368 50.009 65.718 50.557 ;
     RECT  18.615 50.549 20.43 50.585 ;
     RECT  54.792 50.557 54.81 50.593 ;
     RECT  58.716 50.549 59.958 50.593 ;
     RECT  21.672 50.549 21.69 50.621 ;
     RECT  58.68 50.593 59.958 50.621 ;
     RECT  54.72 50.593 54.81 50.629 ;
     RECT  64.368 50.557 65.826 50.629 ;
     RECT  66.564 49.811 72.378 50.629 ;
     RECT  2.304 50.521 10.026 50.657 ;
     RECT  18.615 50.585 20.286 50.657 ;
     RECT  26.712 50.431 27.378 50.657 ;
     RECT  38.592 50.549 38.61 50.657 ;
     RECT  18.615 50.657 20.034 50.669 ;
     RECT  10.8 50.093 13.497 50.693 ;
     RECT  54.72 50.629 54.846 50.693 ;
     RECT  58.68 50.621 59.418 50.701 ;
     RECT  22.464 50.549 24.714 50.717 ;
     RECT  58.644 50.701 59.418 50.717 ;
     RECT  9.54 50.657 10.026 50.729 ;
     RECT  10.8 50.693 11.718 50.729 ;
     RECT  22.824 50.717 24.714 50.729 ;
     RECT  54.828 50.693 54.846 50.729 ;
     RECT  58.644 50.717 58.986 50.729 ;
     RECT  15.876 50.081 17.442 50.791 ;
     RECT  2.304 50.657 8.658 50.819 ;
     RECT  22.824 50.729 24.606 50.819 ;
     RECT  2.304 50.819 5.418 50.855 ;
     RECT  22.824 50.819 24.297 50.855 ;
     RECT  58.644 50.729 58.806 50.855 ;
     RECT  6.192 50.819 8.658 50.861 ;
     RECT  9.72 50.729 10.026 50.935 ;
     RECT  23.256 50.855 24.297 50.963 ;
     RECT  12.492 50.693 13.497 50.971 ;
     RECT  6.192 50.861 8.586 50.999 ;
     RECT  9.72 50.935 10.35 50.999 ;
     RECT  60.84 50.549 63.486 51.061 ;
     RECT  2.34 50.855 5.418 51.089 ;
     RECT  6.192 50.999 8.154 51.089 ;
     RECT  10.008 50.999 10.35 51.089 ;
     RECT  11.196 50.729 11.718 51.089 ;
     RECT  15.876 50.791 17.874 51.089 ;
     RECT  23.688 50.963 24.297 51.089 ;
     RECT  64.368 50.629 72.378 51.089 ;
     RECT  2.34 51.089 4.518 51.125 ;
     RECT  10.008 51.089 10.026 51.125 ;
     RECT  11.196 51.089 11.502 51.125 ;
     RECT  12.492 50.971 14.706 51.125 ;
     RECT  6.192 51.089 8.097 51.197 ;
     RECT  58.716 50.855 58.806 51.197 ;
     RECT  60.84 51.061 63.558 51.197 ;
     RECT  65.196 51.089 72.378 51.197 ;
     RECT  64.368 51.089 64.386 51.205 ;
     RECT  16.74 51.089 17.874 51.233 ;
     RECT  64.116 51.205 64.386 51.245 ;
     RECT  58.788 51.197 58.806 51.269 ;
     RECT  60.84 51.197 63.09 51.269 ;
     RECT  60.84 51.269 62.802 51.307 ;
     RECT  6.192 51.197 6.966 51.359 ;
     RECT  11.196 51.125 11.43 51.359 ;
     RECT  16.812 51.233 16.974 51.359 ;
     RECT  60.408 51.307 62.802 51.359 ;
     RECT  64.224 51.245 64.242 51.359 ;
     RECT  11.196 51.359 11.214 51.395 ;
     RECT  12.492 51.125 13.497 51.395 ;
     RECT  16.812 51.359 16.83 51.395 ;
     RECT  60.408 51.359 60.426 51.403 ;
     RECT  2.376 51.125 4.518 51.431 ;
     RECT  60.228 51.403 60.426 51.44 ;
     RECT  6.948 51.359 6.966 51.629 ;
     RECT  12.564 51.395 13.497 51.629 ;
     RECT  14.832 51.511 14.85 51.629 ;
     RECT  60.408 51.44 60.426 51.629 ;
     RECT  65.556 51.197 72.378 51.629 ;
     RECT  2.376 51.431 4.446 51.665 ;
     RECT  66.744 51.629 72.378 51.737 ;
     RECT  61.2 51.359 62.802 51.773 ;
     RECT  61.2 51.773 62.73 51.809 ;
     RECT  18.615 50.669 19.35 51.883 ;
     RECT  2.415 51.665 4.446 51.899 ;
     RECT  5.4 51.089 5.418 51.899 ;
     RECT  61.2 51.809 62.55 51.899 ;
     RECT  0.108 50.381 0.126 51.935 ;
     RECT  2.415 51.899 3.654 52.169 ;
     RECT  4.428 51.899 4.446 52.169 ;
     RECT  1.404 50.153 1.422 52.205 ;
     RECT  18.615 51.883 19.494 52.321 ;
     RECT  6.192 51.359 6.21 52.439 ;
     RECT  18.615 52.321 19.854 52.439 ;
     RECT  66.96 51.737 72.378 52.439 ;
     RECT  61.452 51.899 62.55 52.619 ;
     RECT  2.415 52.169 3.546 52.709 ;
     RECT  66.96 52.439 71.766 52.781 ;
     RECT  66.96 52.781 71.514 52.889 ;
     RECT  16.56 53.035 16.578 53.221 ;
     RECT  2.415 52.709 3.186 53.249 ;
     RECT  16.56 53.221 16.974 53.261 ;
     RECT  2.415 53.249 2.697 53.365 ;
     RECT  68.4 52.889 71.514 53.429 ;
     RECT  2.304 53.365 2.697 53.453 ;
     RECT  16.56 53.261 16.866 53.519 ;
     RECT  16.668 53.519 16.866 53.789 ;
     RECT  68.4 53.429 71.226 53.789 ;
     RECT  69.66 53.789 71.226 54.131 ;
     RECT  69.66 54.131 71.19 54.329 ;
     RECT  68.4 53.789 68.778 54.365 ;
     RECT  69.66 54.329 71.01 54.571 ;
     RECT  68.4 54.365 68.562 54.599 ;
     RECT  69.48 54.571 71.01 54.599 ;
     RECT  68.4 54.599 68.418 54.671 ;
     RECT  69.48 54.599 70.794 54.671 ;
     RECT  22.428 54.091 22.446 54.701 ;
     RECT  66.96 52.889 67.497 54.869 ;
     RECT  69.66 54.671 70.794 54.869 ;
     RECT  69.732 54.869 70.794 55.139 ;
     RECT  61.815 52.619 62.55 55.409 ;
     RECT  70.2 55.139 70.578 55.409 ;
     RECT  53.748 55.912 53.766 55.949 ;
     RECT  53.424 56.011 53.442 56.057 ;
     RECT  18.615 52.439 19.35 58.699 ;
     RECT  18.615 58.699 19.566 59.227 ;
     RECT  18.615 59.227 20.106 59.459 ;
     RECT  18.615 59.459 19.422 59.597 ;
     RECT  18.615 59.597 19.35 59.603 ;
     RECT  46.944 59.851 46.962 60.269 ;
     RECT  46.62 60.331 46.638 60.377 ;
     RECT  40.215 50.153 40.497 64.411 ;
     RECT  40.215 64.411 41.022 64.589 ;
     RECT  40.215 64.589 40.497 64.651 ;
     RECT  39.888 64.651 40.497 64.769 ;
     RECT  34.815 50.117 35.097 68.971 ;
     RECT  33.12 69.019 33.138 69.025 ;
     RECT  33.12 69.025 33.21 69.151 ;
     RECT  29.415 49.505 29.697 69.163 ;
     RECT  33.048 69.151 33.21 69.179 ;
     RECT  34.2 68.971 35.097 69.179 ;
     RECT  33.048 69.179 33.066 69.197 ;
     RECT  29.304 69.163 29.697 69.215 ;
     RECT  27.36 50.657 27.378 69.989 ;
     RECT  26.424 69.979 26.442 70.141 ;
     RECT  26.424 70.141 26.622 70.501 ;
     RECT  26.388 70.501 26.622 70.537 ;
     RECT  26.28 70.537 26.622 70.799 ;
     RECT  2.415 53.453 2.697 71.027 ;
     RECT  7.815 51.197 8.097 71.027 ;
     RECT  13.215 51.629 13.497 71.027 ;
     RECT  18.615 59.603 18.897 71.027 ;
     RECT  24.015 51.089 24.297 71.027 ;
     RECT  29.415 69.215 29.697 71.027 ;
     RECT  34.815 69.179 35.097 71.027 ;
     RECT  40.215 64.769 40.497 71.027 ;
     RECT  45.615 49.001 45.897 71.027 ;
     RECT  51.015 48.425 51.297 71.027 ;
     RECT  56.415 48.461 56.697 71.027 ;
     RECT  61.815 55.409 62.097 71.027 ;
     RECT  67.215 54.869 67.497 71.027 ;
     RECT  26.28 70.799 26.298 71.069 ;
     RECT  2.415 71.027 2.505 71.297 ;
     RECT  7.815 71.027 7.905 71.297 ;
     RECT  13.215 71.027 13.305 71.297 ;
     RECT  18.615 71.027 18.705 71.297 ;
     RECT  24.015 71.027 24.105 71.297 ;
     RECT  29.415 71.027 29.505 71.297 ;
     RECT  34.815 71.027 34.905 71.297 ;
     RECT  40.215 71.027 40.305 71.297 ;
     RECT  45.615 71.027 45.705 71.297 ;
     RECT  51.015 71.027 51.105 71.297 ;
     RECT  56.415 71.027 56.505 71.297 ;
     RECT  61.815 71.027 61.905 71.297 ;
     RECT  67.215 71.027 67.305 71.297 ;
     RECT  25.992 71.185 26.01 72.283 ;
     RECT  25.992 72.283 26.478 72.413 ;
    LAYER M4 ;
     RECT  0.06 15.888 0.133 50.376 ;
     RECT  0.133 15.888 0.569 50.472 ;
     RECT  0.569 16.176 2.408 50.472 ;
     RECT  2.408 2.148 2.512 71.292 ;
     RECT  2.512 2.418 2.704 71.022 ;
     RECT  2.704 16.656 2.837 45.24 ;
     RECT  2.704 46.32 2.909 50.376 ;
     RECT  2.837 16.848 2.945 45.24 ;
     RECT  2.909 46.32 3.305 48.744 ;
     RECT  2.945 27.312 3.377 45.24 ;
     RECT  3.377 27.312 3.413 34.92 ;
     RECT  2.945 16.848 3.521 26.28 ;
     RECT  2.909 50.16 3.733 50.376 ;
     RECT  3.733 50.16 3.805 50.472 ;
     RECT  3.413 30.576 3.989 34.92 ;
     RECT  3.521 18.144 4.097 26.28 ;
     RECT  4.097 19.248 4.129 26.28 ;
     RECT  3.413 27.312 4.129 29.544 ;
     RECT  3.305 46.32 4.169 48.648 ;
     RECT  3.521 16.848 4.309 17.064 ;
     RECT  4.309 16.464 4.357 17.064 ;
     RECT  4.169 46.704 4.417 48.648 ;
     RECT  4.129 19.248 4.421 29.544 ;
     RECT  3.805 50.16 4.421 50.712 ;
     RECT  4.357 16.416 4.444 17.064 ;
     RECT  4.417 46.704 4.453 48.84 ;
     RECT  4.444 16.464 4.525 17.064 ;
     RECT  3.989 30.816 4.536 34.92 ;
     RECT  3.377 36 4.536 45.24 ;
     RECT  4.536 30.816 4.565 45.24 ;
     RECT  4.565 30.816 4.601 43.368 ;
     RECT  4.601 30.816 4.637 41.4 ;
     RECT  4.421 19.392 4.673 19.416 ;
     RECT  4.565 44.688 4.673 45.24 ;
     RECT  4.637 30.816 4.745 40.824 ;
     RECT  4.673 44.976 4.777 45.24 ;
     RECT  4.601 42.432 4.889 43.368 ;
     RECT  4.745 40.8 4.997 40.824 ;
     RECT  4.777 44.976 5.027 45.576 ;
     RECT  4.525 16.464 5.065 17.16 ;
     RECT  4.097 18.144 5.065 18.216 ;
     RECT  4.745 30.816 5.177 39.432 ;
     RECT  5.027 44.976 5.177 45.048 ;
     RECT  4.453 46.704 5.177 48.936 ;
     RECT  5.177 30.816 5.249 38.76 ;
     RECT  5.177 45.024 5.249 45.048 ;
     RECT  4.421 20.88 5.285 29.544 ;
     RECT  5.177 46.752 5.569 48.936 ;
     RECT  5.285 20.88 5.609 23.304 ;
     RECT  5.285 24.336 5.677 29.544 ;
     RECT  5.249 30.816 5.677 34.344 ;
     RECT  5.677 41.184 5.749 41.208 ;
     RECT  4.421 50.688 5.789 50.712 ;
     RECT  5.749 41.184 5.929 41.256 ;
     RECT  4.889 42.432 5.929 43.32 ;
     RECT  5.677 24.336 5.969 34.344 ;
     RECT  5.929 41.184 6.005 43.32 ;
     RECT  5.969 31.824 6.035 34.344 ;
     RECT  5.065 16.464 6.037 18.216 ;
     RECT  6.035 33.504 6.076 34.104 ;
     RECT  6.005 43.296 6.077 43.32 ;
     RECT  5.569 46.752 6.181 49.176 ;
     RECT  5.969 24.336 6.329 30.216 ;
     RECT  6.037 15.984 6.361 18.216 ;
     RECT  6.076 34.08 6.365 34.104 ;
     RECT  5.249 35.712 6.397 38.76 ;
     RECT  6.181 46.56 6.685 49.176 ;
     RECT  6.397 35.472 6.829 38.76 ;
     RECT  6.829 35.28 6.833 38.76 ;
     RECT  6.685 46.08 6.973 49.176 ;
     RECT  6.035 31.824 7.052 32.28 ;
     RECT  6.833 38.736 7.052 38.76 ;
     RECT  7.052 31.824 7.093 32.568 ;
     RECT  6.005 41.232 7.093 41.496 ;
     RECT  6.329 24.384 7.34 30.216 ;
     RECT  7.093 31.2 7.34 32.568 ;
     RECT  7.093 40.8 7.369 41.496 ;
     RECT  6.361 15.984 7.405 18.408 ;
     RECT  5.609 20.88 7.429 23.112 ;
     RECT  7.052 38.736 7.436 39.096 ;
     RECT  7.369 40.464 7.436 41.784 ;
     RECT  7.388 44.976 7.477 45 ;
     RECT  7.429 20.88 7.525 23.352 ;
     RECT  7.34 24.384 7.525 32.568 ;
     RECT  7.477 44.736 7.621 45 ;
     RECT  6.973 46.08 7.621 49.56 ;
     RECT  7.405 15.984 7.808 18.792 ;
     RECT  7.525 20.88 7.808 32.568 ;
     RECT  7.369 33.6 7.808 33.624 ;
     RECT  6.833 35.28 7.808 37.656 ;
     RECT  7.436 38.736 7.808 41.784 ;
     RECT  7.477 43.536 7.808 43.56 ;
     RECT  7.621 44.736 7.808 49.608 ;
     RECT  7.808 2.148 7.912 71.292 ;
     RECT  7.912 2.418 8.104 71.022 ;
     RECT  8.104 39.264 8.129 39.336 ;
     RECT  8.104 34.752 8.381 37.464 ;
     RECT  8.104 17.088 8.417 18.216 ;
     RECT  8.104 40.944 8.531 42.168 ;
     RECT  8.104 45.792 8.633 46.104 ;
     RECT  8.381 34.752 8.705 35.496 ;
     RECT  8.104 43.536 8.705 44.76 ;
     RECT  8.104 47.568 8.777 50.856 ;
     RECT  8.104 24.48 8.849 28.392 ;
     RECT  8.531 40.944 8.849 41.784 ;
     RECT  8.104 30.288 9.101 31.896 ;
     RECT  8.705 43.536 9.277 43.944 ;
     RECT  8.849 24.48 9.317 26.568 ;
     RECT  8.705 35.472 9.457 35.496 ;
     RECT  8.381 36.768 9.457 37.464 ;
     RECT  8.777 47.568 9.529 48.456 ;
     RECT  8.849 27.696 9.541 28.392 ;
     RECT  8.417 17.472 9.587 18.216 ;
     RECT  9.541 27.696 9.685 29.112 ;
     RECT  8.104 33.6 9.713 33.624 ;
     RECT  8.633 46.08 9.745 46.104 ;
     RECT  8.777 49.968 9.749 50.856 ;
     RECT  9.457 35.472 9.817 37.464 ;
     RECT  9.685 27.696 9.821 29.928 ;
     RECT  9.817 35.472 9.893 37.512 ;
     RECT  9.893 35.472 9.929 35.976 ;
     RECT  9.101 30.96 9.961 31.896 ;
     RECT  8.849 40.944 9.961 41.496 ;
     RECT  9.277 43.152 9.961 43.944 ;
     RECT  8.104 20.88 9.971 23.352 ;
     RECT  8.129 39.264 9.997 39.288 ;
     RECT  9.821 27.696 10.073 29.496 ;
     RECT  9.317 24.48 10.141 26.328 ;
     RECT  9.961 40.944 10.165 43.944 ;
     RECT  10.165 40.8 10.213 43.944 ;
     RECT  9.745 45.12 10.213 46.104 ;
     RECT  10.213 40.8 10.252 46.104 ;
     RECT  10.252 40.944 10.253 46.104 ;
     RECT  10.253 41.232 10.261 46.104 ;
     RECT  9.529 47.28 10.261 48.456 ;
     RECT  10.141 23.952 10.357 26.328 ;
     RECT  10.073 27.696 10.357 29.064 ;
     RECT  9.961 30.96 10.681 32.184 ;
     RECT  10.261 41.232 10.787 48.456 ;
     RECT  10.787 43.104 10.829 48.456 ;
     RECT  10.357 23.952 10.835 29.064 ;
     RECT  9.587 17.472 10.865 17.784 ;
     RECT  10.787 41.232 10.865 41.976 ;
     RECT  9.929 35.952 10.901 35.976 ;
     RECT  9.971 20.88 10.969 22.488 ;
     RECT  10.835 23.952 10.969 28.968 ;
     RECT  10.969 20.88 11.053 28.968 ;
     RECT  11.053 20.88 11.081 22.488 ;
     RECT  9.997 39.264 11.113 39.672 ;
     RECT  10.681 30.768 11.149 32.184 ;
     RECT  11.149 30.192 11.173 32.184 ;
     RECT  11.041 33.264 11.173 34.248 ;
     RECT  11.173 30.192 11.297 34.248 ;
     RECT  11.113 39.264 11.473 39.864 ;
     RECT  10.177 50.976 11.513 51 ;
     RECT  10.829 44.352 11.581 48.456 ;
     RECT  9.749 49.968 11.617 49.992 ;
     RECT  10.829 43.104 11.797 43.272 ;
     RECT  11.581 44.352 11.801 48.552 ;
     RECT  11.473 39.264 11.941 40.728 ;
     RECT  11.941 38.736 11.948 40.728 ;
     RECT  10.865 41.952 11.948 41.976 ;
     RECT  11.053 24.336 12.035 28.968 ;
     RECT  12.035 24.432 12.049 28.968 ;
     RECT  11.297 30.192 12.049 32.472 ;
     RECT  11.077 35.856 12.085 35.88 ;
     RECT  11.617 49.584 12.121 49.992 ;
     RECT  12.085 35.28 12.153 35.88 ;
     RECT  12.049 24.432 12.161 32.472 ;
     RECT  12.153 35.28 12.172 35.304 ;
     RECT  11.948 38.736 12.233 41.976 ;
     RECT  9.893 37.008 12.337 37.512 ;
     RECT  12.233 38.736 12.337 40.728 ;
     RECT  11.797 43.104 12.913 43.32 ;
     RECT  11.801 44.352 12.913 48.168 ;
     RECT  12.161 24.432 13.201 32.328 ;
     RECT  12.913 43.104 13.201 48.168 ;
     RECT  12.121 49.488 13.201 49.992 ;
     RECT  8.104 15.984 13.208 16.008 ;
     RECT  10.865 17.472 13.208 17.688 ;
     RECT  11.081 20.88 13.208 21.72 ;
     RECT  13.201 23.904 13.208 32.328 ;
     RECT  11.297 34.224 13.208 34.248 ;
     RECT  12.337 37.008 13.208 40.728 ;
     RECT  13.201 43.104 13.208 50.856 ;
     RECT  12.229 59.568 13.208 59.592 ;
     RECT  10.789 70.56 13.208 70.584 ;
     RECT  13.208 2.148 13.312 71.292 ;
     RECT  13.312 2.418 13.504 71.022 ;
     RECT  13.504 25.68 13.601 30.696 ;
     RECT  13.601 25.68 13.619 29.016 ;
     RECT  13.601 30.24 13.619 30.696 ;
     RECT  13.619 30.672 13.853 30.696 ;
     RECT  13.504 31.776 13.997 32.328 ;
     RECT  13.504 41.184 14.105 42.12 ;
     RECT  13.504 46.08 14.141 50.856 ;
     RECT  13.504 43.104 14.285 43.944 ;
     RECT  14.141 47.664 14.291 50.856 ;
     RECT  13.504 23.904 14.393 24.648 ;
     RECT  13.504 36.48 14.429 39.864 ;
     RECT  14.429 39.264 14.492 39.864 ;
     RECT  14.105 41.184 14.492 41.496 ;
     RECT  14.429 36.48 14.537 37.464 ;
     RECT  14.492 39.264 14.579 41.496 ;
     RECT  13.504 33.6 14.629 33.624 ;
     RECT  14.141 46.08 14.645 46.104 ;
     RECT  14.393 23.952 14.677 24.648 ;
     RECT  13.619 25.68 14.677 28.584 ;
     RECT  14.285 43.104 14.681 43.368 ;
     RECT  14.629 33.6 14.717 34.344 ;
     RECT  13.504 35.328 14.933 35.352 ;
     RECT  13.997 31.776 15.109 31.944 ;
     RECT  15.109 31.152 15.155 31.944 ;
     RECT  15.155 31.152 15.196 31.416 ;
     RECT  14.677 23.952 15.437 28.584 ;
     RECT  14.579 41.184 15.469 41.496 ;
     RECT  15.196 31.392 15.509 31.416 ;
     RECT  14.291 47.664 15.581 50.76 ;
     RECT  14.717 33.6 15.725 33.624 ;
     RECT  14.537 36.864 15.788 37.464 ;
     RECT  14.579 39.264 15.788 39.864 ;
     RECT  15.581 50.064 15.865 50.76 ;
     RECT  15.788 36.864 15.875 37.896 ;
     RECT  15.788 38.928 16.021 39.864 ;
     RECT  14.681 43.344 16.067 43.368 ;
     RECT  15.469 41.184 16.181 41.64 ;
     RECT  16.021 38.496 16.22 39.864 ;
     RECT  16.181 40.992 16.22 41.64 ;
     RECT  16.22 38.496 16.481 41.64 ;
     RECT  16.117 53.232 16.549 53.256 ;
     RECT  15.865 50.064 16.595 51 ;
     RECT  15.437 24.48 16.621 28.584 ;
     RECT  16.549 53.04 16.633 53.256 ;
     RECT  15.581 47.664 16.657 49.032 ;
     RECT  16.595 50.064 16.657 50.088 ;
     RECT  16.633 53.232 16.657 53.256 ;
     RECT  15.829 35.856 16.697 35.88 ;
     RECT  16.621 24.288 16.739 28.584 ;
     RECT  16.481 39.6 16.787 41.64 ;
     RECT  16.657 53.232 16.985 53.592 ;
     RECT  16.787 40.896 17.021 41.64 ;
     RECT  16.739 24.48 17.077 28.584 ;
     RECT  16.837 30.24 17.077 30.264 ;
     RECT  17.077 24.48 17.123 30.264 ;
     RECT  16.787 39.6 17.953 39.912 ;
     RECT  17.021 40.896 17.953 41.4 ;
     RECT  16.481 38.496 18.325 38.52 ;
     RECT  17.953 39.6 18.325 41.4 ;
     RECT  18.325 38.496 18.457 41.4 ;
     RECT  13.504 15.984 18.608 16.008 ;
     RECT  13.504 17.472 18.608 17.784 ;
     RECT  13.504 20.88 18.608 21.72 ;
     RECT  17.123 24.48 18.608 29.544 ;
     RECT  15.875 36.864 18.608 37.464 ;
     RECT  18.457 38.496 18.608 41.496 ;
     RECT  16.657 47.664 18.608 50.088 ;
     RECT  16.985 53.568 18.608 53.592 ;
     RECT  13.504 59.568 18.608 59.592 ;
     RECT  13.504 70.56 18.608 70.584 ;
     RECT  18.608 2.148 18.712 71.292 ;
     RECT  18.712 2.418 18.904 71.022 ;
     RECT  18.904 20.88 18.965 21.72 ;
     RECT  18.904 36.864 19.001 40.824 ;
     RECT  18.904 17.616 19.043 18.456 ;
     RECT  18.904 24.24 19.073 30.168 ;
     RECT  18.965 21.072 19.117 21.72 ;
     RECT  19.073 26.256 19.325 30.168 ;
     RECT  19.001 36.96 19.433 40.824 ;
     RECT  18.904 58.704 19.433 59.592 ;
     RECT  19.433 39.84 19.505 40.824 ;
     RECT  18.904 51.888 19.505 52.392 ;
     RECT  19.505 52.368 19.571 52.392 ;
     RECT  18.904 53.568 19.571 54.12 ;
     RECT  19.433 58.704 19.577 59.256 ;
     RECT  18.904 47.664 20.005 50.424 ;
     RECT  19.325 26.256 20.077 29.112 ;
     RECT  19.577 59.232 20.117 59.256 ;
     RECT  19.117 21.696 20.369 21.72 ;
     RECT  19.073 24.24 20.437 24.984 ;
     RECT  20.077 26.208 20.485 29.112 ;
     RECT  19.909 30.336 20.485 30.36 ;
     RECT  20.485 26.208 20.509 30.36 ;
     RECT  20.437 21.648 20.521 21.672 ;
     RECT  20.509 26.208 20.531 30.456 ;
     RECT  20.437 24.24 20.54 25.224 ;
     RECT  20.531 26.208 20.54 28.584 ;
     RECT  19.505 39.84 20.585 40.056 ;
     RECT  20.005 41.04 20.585 41.064 ;
     RECT  20.54 24.24 20.627 28.584 ;
     RECT  19.043 17.76 21.125 18.456 ;
     RECT  19.433 36.96 21.445 38.52 ;
     RECT  21.121 35.76 21.593 35.784 ;
     RECT  20.531 29.616 21.697 30.456 ;
     RECT  20.005 47.664 21.881 50.664 ;
     RECT  21.697 29.616 22.057 30.552 ;
     RECT  18.904 15.984 22.133 16.008 ;
     RECT  22.057 29.616 22.165 30.984 ;
     RECT  21.445 36.864 22.313 38.52 ;
     RECT  21.881 47.664 22.313 49.08 ;
     RECT  20.627 26.208 22.417 28.584 ;
     RECT  22.165 29.616 22.417 31.8 ;
     RECT  19.571 54.096 22.417 54.12 ;
     RECT  21.881 50.064 22.453 50.664 ;
     RECT  18.904 70.56 22.453 70.584 ;
     RECT  22.417 54.096 22.457 54.696 ;
     RECT  22.457 54.288 22.501 54.696 ;
     RECT  22.501 54.288 22.547 54.312 ;
     RECT  20.585 39.84 22.705 39.864 ;
     RECT  22.417 26.208 22.961 31.8 ;
     RECT  22.961 31.104 23.173 31.8 ;
     RECT  20.627 24.24 23.353 25.224 ;
     RECT  22.961 26.208 23.353 29.64 ;
     RECT  22.313 47.664 23.605 48.792 ;
     RECT  22.453 50.064 23.605 50.712 ;
     RECT  22.309 16.272 23.965 16.296 ;
     RECT  23.353 24.24 23.965 29.64 ;
     RECT  23.173 31.104 23.965 31.944 ;
     RECT  23.965 16.272 24.008 16.824 ;
     RECT  21.125 18.144 24.008 18.456 ;
     RECT  20.581 22.848 24.008 22.872 ;
     RECT  23.965 24.24 24.008 31.944 ;
     RECT  24.001 34.368 24.008 34.392 ;
     RECT  22.313 36.864 24.008 38.184 ;
     RECT  22.705 39.84 24.008 40.344 ;
     RECT  23.605 47.664 24.008 50.712 ;
     RECT  22.453 69.984 24.008 70.584 ;
     RECT  24.008 2.148 24.112 71.292 ;
     RECT  24.112 2.418 24.304 71.022 ;
     RECT  24.304 24.24 24.515 32.472 ;
     RECT  24.304 50.064 24.725 50.712 ;
     RECT  24.304 39.84 24.947 40.344 ;
     RECT  24.304 36.48 25.013 38.76 ;
     RECT  24.515 26.4 25.085 32.472 ;
     RECT  25.085 32.448 25.297 32.472 ;
     RECT  25.297 32.448 25.669 33 ;
     RECT  24.304 34.368 25.717 35.064 ;
     RECT  25.013 36.48 25.717 38.184 ;
     RECT  25.717 34.368 25.763 38.184 ;
     RECT  24.304 47.664 25.769 48.792 ;
     RECT  25.769 48.144 25.805 48.792 ;
     RECT  25.669 32.448 25.877 33.048 ;
     RECT  25.763 34.368 25.877 35.88 ;
     RECT  25.085 26.4 25.955 31.32 ;
     RECT  25.805 48.384 26.093 48.792 ;
     RECT  25.877 32.448 26.201 33 ;
     RECT  25.877 34.752 26.201 35.88 ;
     RECT  24.304 69.984 26.245 70.584 ;
     RECT  26.245 69.168 26.377 70.584 ;
     RECT  25.981 72.384 26.389 72.408 ;
     RECT  26.377 69.168 26.453 70.68 ;
     RECT  26.453 70.656 26.461 70.68 ;
     RECT  26.389 72.288 26.489 72.408 ;
     RECT  26.489 72.384 26.524 72.408 ;
     RECT  25.763 37.008 26.773 38.184 ;
     RECT  26.093 48.768 26.773 48.792 ;
     RECT  25.955 26.4 26.813 30.744 ;
     RECT  26.773 48.768 27.029 48.936 ;
     RECT  26.201 35.568 27.313 35.88 ;
     RECT  26.773 36.864 27.313 38.184 ;
     RECT  26.201 32.976 27.347 33 ;
     RECT  27.313 35.568 27.497 38.184 ;
     RECT  27.497 35.568 27.877 37.56 ;
     RECT  27.877 34.752 28.109 37.56 ;
     RECT  28.109 34.752 28.361 37.464 ;
     RECT  26.813 26.4 28.441 30.408 ;
     RECT  28.441 29.856 28.465 30.408 ;
     RECT  28.357 31.68 28.465 31.704 ;
     RECT  27.029 48.768 29.149 48.792 ;
     RECT  24.725 50.064 29.149 50.088 ;
     RECT  24.304 16.272 29.408 16.296 ;
     RECT  24.304 18.144 29.408 18.456 ;
     RECT  24.304 22.848 29.408 22.872 ;
     RECT  24.515 24.24 29.408 25.224 ;
     RECT  28.441 26.4 29.408 28.584 ;
     RECT  28.465 29.856 29.408 31.704 ;
     RECT  29.365 33.552 29.408 33.576 ;
     RECT  28.361 34.752 29.408 34.776 ;
     RECT  28.361 35.76 29.408 37.464 ;
     RECT  24.947 39.84 29.408 39.864 ;
     RECT  29.077 47.424 29.408 47.448 ;
     RECT  29.149 48.768 29.408 50.088 ;
     RECT  26.453 69.168 29.408 69.192 ;
     RECT  29.408 2.148 29.512 71.292 ;
     RECT  29.512 2.418 29.704 71.022 ;
     RECT  29.704 47.424 29.765 48.792 ;
     RECT  29.704 36.864 30.769 37.464 ;
     RECT  29.765 47.904 30.769 48.792 ;
     RECT  29.704 50.064 30.769 50.088 ;
     RECT  29.704 29.856 30.773 31.944 ;
     RECT  29.704 26.4 30.805 28.776 ;
     RECT  30.773 31.872 30.805 31.944 ;
     RECT  29.704 33.552 30.805 33.576 ;
     RECT  30.769 36.624 30.805 37.464 ;
     RECT  30.805 26.304 30.841 28.776 ;
     RECT  29.704 18.144 30.845 18.456 ;
     RECT  30.773 29.856 30.881 30.84 ;
     RECT  30.881 30.096 30.917 30.84 ;
     RECT  30.805 31.872 30.917 33.576 ;
     RECT  30.841 26.208 31.025 28.776 ;
     RECT  30.917 32.736 31.385 33.576 ;
     RECT  31.561 34.08 31.633 34.104 ;
     RECT  30.769 47.904 31.781 50.088 ;
     RECT  31.781 47.904 32.069 48.792 ;
     RECT  31.025 26.304 32.149 28.776 ;
     RECT  32.149 26.304 32.197 29.208 ;
     RECT  30.917 30.384 32.197 30.84 ;
     RECT  31.385 32.736 32.245 32.904 ;
     RECT  32.069 48.144 32.249 48.792 ;
     RECT  30.805 36.528 32.389 37.464 ;
     RECT  32.245 32.544 32.435 32.904 ;
     RECT  29.704 24.24 32.461 25.224 ;
     RECT  32.197 26.304 32.461 30.84 ;
     RECT  32.389 35.904 32.473 37.464 ;
     RECT  32.461 24.24 32.485 30.84 ;
     RECT  31.633 34.08 32.537 34.152 ;
     RECT  32.485 23.856 32.573 30.84 ;
     RECT  32.573 24.24 32.609 30.84 ;
     RECT  32.249 48.336 32.893 48.792 ;
     RECT  32.609 24.48 32.929 30.84 ;
     RECT  32.435 32.544 32.929 32.76 ;
     RECT  32.893 48.336 33.005 48.984 ;
     RECT  32.929 24.48 33.059 32.76 ;
     RECT  29.704 69.168 33.068 69.192 ;
     RECT  32.209 47.136 33.073 47.16 ;
     RECT  33.068 69.024 33.077 69.192 ;
     RECT  32.473 36.624 33.109 37.464 ;
     RECT  33.077 69.024 33.155 69.048 ;
     RECT  33.059 24.48 33.257 31.32 ;
     RECT  33.109 36.624 33.577 37.608 ;
     RECT  33.059 32.736 33.689 32.76 ;
     RECT  33.073 46.896 33.725 47.16 ;
     RECT  29.704 39.84 33.973 39.864 ;
     RECT  33.577 36.624 34.297 37.944 ;
     RECT  33.973 39.216 34.297 39.864 ;
     RECT  29.704 22.848 34.693 22.872 ;
     RECT  33.005 48.768 34.765 48.984 ;
     RECT  31.781 50.064 34.765 50.088 ;
     RECT  29.704 16.272 34.808 16.296 ;
     RECT  30.845 18.144 34.808 18.168 ;
     RECT  34.693 22.752 34.808 22.872 ;
     RECT  33.257 24.96 34.808 31.32 ;
     RECT  32.537 34.08 34.808 34.104 ;
     RECT  34.297 36.624 34.808 39.864 ;
     RECT  34.621 43.296 34.808 43.32 ;
     RECT  33.725 46.896 34.808 46.92 ;
     RECT  34.765 48.768 34.808 50.088 ;
     RECT  34.213 64.656 34.808 64.68 ;
     RECT  34.189 68.976 34.808 69 ;
     RECT  34.808 2.148 34.912 71.292 ;
     RECT  34.912 2.418 35.104 71.022 ;
     RECT  35.104 48.48 35.129 50.088 ;
     RECT  35.104 39.216 35.219 39.864 ;
     RECT  35.104 43.248 35.219 43.608 ;
     RECT  35.104 46.896 35.219 47.016 ;
     RECT  35.104 24.96 35.315 31.368 ;
     RECT  35.104 22.656 35.525 22.776 ;
     RECT  35.219 43.296 35.561 43.608 ;
     RECT  35.104 18.144 35.633 18.168 ;
     RECT  35.104 33.6 35.891 34.584 ;
     RECT  35.219 46.992 35.921 47.016 ;
     RECT  35.891 34.08 36.313 34.584 ;
     RECT  36.313 34.08 36.371 34.824 ;
     RECT  35.315 24.96 36.385 28.584 ;
     RECT  35.315 29.616 36.385 31.368 ;
     RECT  36.371 34.8 36.396 34.824 ;
     RECT  36.396 34.8 36.397 34.872 ;
     RECT  35.561 43.584 36.668 43.608 ;
     RECT  35.104 41.088 36.709 41.112 ;
     RECT  35.525 22.656 36.755 22.68 ;
     RECT  36.668 43.584 36.755 44.04 ;
     RECT  35.104 45.12 36.755 45.144 ;
     RECT  36.325 32.448 36.817 32.472 ;
     RECT  35.129 48.768 36.965 50.088 ;
     RECT  36.385 23.76 37.033 31.368 ;
     RECT  36.817 32.448 37.033 32.568 ;
     RECT  36.709 41.088 37.324 41.592 ;
     RECT  37.033 23.76 37.361 32.568 ;
     RECT  36.965 48.768 37.393 49.032 ;
     RECT  37.324 41.04 37.397 41.592 ;
     RECT  36.397 34.848 37.429 34.872 ;
     RECT  35.104 35.904 37.429 37.944 ;
     RECT  37.393 48.624 37.433 49.032 ;
     RECT  35.104 16.272 37.573 16.296 ;
     RECT  36.745 46.752 37.609 46.776 ;
     RECT  37.361 31.344 37.619 32.568 ;
     RECT  36.709 21.648 37.757 21.672 ;
     RECT  37.361 23.76 38.147 30.12 ;
     RECT  37.573 16.272 38.189 17.112 ;
     RECT  37.429 34.848 38.197 37.944 ;
     RECT  38.149 21.792 38.243 21.816 ;
     RECT  38.197 34.176 38.243 37.944 ;
     RECT  37.609 46.752 38.243 47.064 ;
     RECT  38.147 23.76 38.284 23.784 ;
     RECT  37.397 41.04 38.332 41.064 ;
     RECT  38.197 45.552 38.513 45.576 ;
     RECT  37.433 48.624 38.617 48.984 ;
     RECT  36.965 50.064 38.617 50.088 ;
     RECT  37.619 31.728 38.657 32.568 ;
     RECT  38.657 31.728 38.693 31.8 ;
     RECT  38.243 47.04 38.729 47.064 ;
     RECT  38.147 24.96 38.761 30.12 ;
     RECT  38.243 35.904 38.761 37.944 ;
     RECT  38.617 48.624 38.761 50.088 ;
     RECT  38.761 24.96 38.873 30.36 ;
     RECT  38.873 30.096 38.945 30.36 ;
     RECT  38.761 48.432 38.945 50.088 ;
     RECT  38.873 24.96 38.981 29.016 ;
     RECT  38.945 30.096 38.981 30.12 ;
     RECT  38.243 34.176 39.161 34.2 ;
     RECT  38.693 31.776 39.661 31.8 ;
     RECT  38.945 48.432 39.841 48.984 ;
     RECT  38.189 17.088 40.208 17.112 ;
     RECT  38.981 24.96 40.208 28.584 ;
     RECT  39.661 31.488 40.208 31.8 ;
     RECT  40.057 34.368 40.208 34.392 ;
     RECT  38.761 35.904 40.208 38.136 ;
     RECT  35.219 39.84 40.208 39.864 ;
     RECT  36.755 43.584 40.208 43.608 ;
     RECT  39.841 47.616 40.208 48.984 ;
     RECT  38.945 50.064 40.208 50.088 ;
     RECT  35.104 64.656 40.208 64.68 ;
     RECT  40.208 2.148 40.312 71.292 ;
     RECT  40.312 2.418 40.504 71.022 ;
     RECT  40.504 64.416 41.033 64.44 ;
     RECT  40.504 32.976 41.075 37.944 ;
     RECT  41.075 33.504 41.177 33.528 ;
     RECT  40.504 24.048 41.429 25.128 ;
     RECT  40.504 46.704 41.429 48.792 ;
     RECT  40.504 26.208 41.537 31.512 ;
     RECT  41.075 35.28 41.825 37.944 ;
     RECT  41.429 46.704 41.857 46.728 ;
     RECT  41.825 35.328 41.893 37.944 ;
     RECT  41.857 46.176 41.897 46.728 ;
     RECT  41.429 24.192 42.073 25.128 ;
     RECT  41.537 26.208 42.073 30.84 ;
     RECT  41.897 46.176 42.221 46.248 ;
     RECT  42.073 24.192 42.329 30.84 ;
     RECT  42.649 34.32 42.757 34.344 ;
     RECT  41.429 48.432 42.793 48.792 ;
     RECT  42.329 24.192 42.829 30.12 ;
     RECT  42.757 33.36 42.869 34.344 ;
     RECT  41.893 35.328 42.869 38.184 ;
     RECT  42.757 31.92 43.045 31.944 ;
     RECT  42.869 33.504 43.091 34.344 ;
     RECT  43.045 31.872 43.189 31.944 ;
     RECT  43.091 33.744 43.189 34.344 ;
     RECT  42.869 35.328 43.189 37.944 ;
     RECT  43.189 33.744 43.235 37.944 ;
     RECT  42.221 46.176 43.292 46.2 ;
     RECT  43.292 46.176 43.333 46.68 ;
     RECT  43.333 46.176 43.379 47.304 ;
     RECT  40.504 39.84 43.381 39.864 ;
     RECT  43.009 40.848 43.381 40.872 ;
     RECT  42.829 24.048 43.409 30.12 ;
     RECT  43.379 46.176 43.427 46.2 ;
     RECT  43.379 47.28 43.429 47.304 ;
     RECT  42.793 48.432 43.429 49.032 ;
     RECT  43.429 47.28 43.475 49.032 ;
     RECT  43.475 47.28 43.516 48.792 ;
     RECT  43.381 39.84 43.541 40.872 ;
     RECT  43.541 39.84 43.625 41.016 ;
     RECT  40.504 43.584 43.907 43.608 ;
     RECT  43.235 35.088 43.913 37.944 ;
     RECT  43.625 39.84 43.913 40.872 ;
     RECT  43.913 40.848 43.949 40.872 ;
     RECT  43.189 31.488 44.089 31.944 ;
     RECT  43.516 47.28 44.093 47.304 ;
     RECT  43.409 24.096 44.197 30.12 ;
     RECT  44.089 31.392 44.197 31.944 ;
     RECT  44.197 24.096 44.243 31.944 ;
     RECT  44.243 24.096 44.489 31.8 ;
     RECT  44.489 24.096 44.524 28.728 ;
     RECT  43.913 35.904 44.633 37.944 ;
     RECT  44.524 24.096 45.608 25.08 ;
     RECT  44.524 26.304 45.608 28.728 ;
     RECT  44.489 30.096 45.608 31.8 ;
     RECT  43.235 33.744 45.608 34.056 ;
     RECT  44.633 35.904 45.608 36.888 ;
     RECT  44.633 37.92 45.608 37.944 ;
     RECT  43.913 39.84 45.608 39.864 ;
     RECT  43.861 45.264 45.608 45.288 ;
     RECT  43.516 48.672 45.608 48.792 ;
     RECT  40.504 50.064 45.608 50.088 ;
     RECT  40.504 60.336 45.608 60.36 ;
     RECT  45.608 2.148 45.712 71.292 ;
     RECT  45.712 2.418 45.904 71.022 ;
     RECT  45.904 26.4 46.081 31.896 ;
     RECT  46.081 26.4 46.361 28.728 ;
     RECT  45.904 60.336 46.649 60.36 ;
     RECT  45.904 48 46.721 48.792 ;
     RECT  45.904 24 46.865 25.368 ;
     RECT  46.081 29.904 46.969 31.896 ;
     RECT  46.865 24 46.973 24.984 ;
     RECT  46.933 59.856 47.017 59.88 ;
     RECT  46.973 24.144 47.045 24.984 ;
     RECT  46.969 29.904 47.401 32.472 ;
     RECT  46.361 26.4 47.509 28.584 ;
     RECT  47.401 29.904 47.509 33.528 ;
     RECT  47.509 26.4 47.693 33.528 ;
     RECT  47.693 26.4 47.729 33.432 ;
     RECT  47.729 30.624 47.765 33.432 ;
     RECT  47.765 30.624 48.017 32.472 ;
     RECT  47.729 26.4 48.805 28.968 ;
     RECT  48.805 26.4 49.097 29.736 ;
     RECT  49.097 29.712 49.205 29.736 ;
     RECT  49.669 33.84 49.885 33.864 ;
     RECT  48.017 30.816 49.961 32.472 ;
     RECT  45.904 35.952 50.005 36.888 ;
     RECT  50.005 35.664 50.677 36.888 ;
     RECT  47.045 24.96 50.713 24.984 ;
     RECT  50.677 35.424 50.713 36.888 ;
     RECT  45.904 37.92 50.713 37.944 ;
     RECT  45.904 45.408 50.869 45.432 ;
     RECT  49.885 33.552 50.893 33.864 ;
     RECT  50.869 45.168 50.893 45.432 ;
     RECT  50.713 24.432 51.008 24.984 ;
     RECT  49.097 26.4 51.008 28.584 ;
     RECT  50.353 29.808 51.008 29.832 ;
     RECT  49.961 30.96 51.008 32.472 ;
     RECT  50.893 33.552 51.008 33.912 ;
     RECT  50.713 35.424 51.008 37.944 ;
     RECT  45.904 39.84 51.008 39.864 ;
     RECT  50.893 45.168 51.008 45.576 ;
     RECT  46.721 48.768 51.008 48.792 ;
     RECT  45.904 50.064 51.008 50.088 ;
     RECT  46.933 56.016 51.008 56.04 ;
     RECT  51.008 2.148 51.112 71.292 ;
     RECT  51.112 2.418 51.304 71.022 ;
     RECT  51.304 35.424 51.401 36.888 ;
     RECT  51.304 30.96 51.509 31.752 ;
     RECT  51.304 45.408 51.545 45.576 ;
     RECT  51.304 33.552 52.585 33.576 ;
     RECT  52.585 33.552 52.913 34.152 ;
     RECT  51.304 37.92 52.94 37.944 ;
     RECT  51.401 36.432 52.981 36.888 ;
     RECT  52.94 37.92 52.981 38.664 ;
     RECT  51.401 35.424 53.027 35.448 ;
     RECT  52.981 36.432 53.161 38.664 ;
     RECT  51.304 39.84 53.161 39.864 ;
     RECT  52.913 33.552 53.315 33.576 ;
     RECT  51.304 56.016 53.453 56.04 ;
     RECT  53.737 55.92 53.821 55.944 ;
     RECT  53.161 36.432 54.353 39.864 ;
     RECT  51.304 26.4 54.709 28.584 ;
     RECT  51.509 31.728 54.709 31.752 ;
     RECT  54.353 36.432 54.709 36.888 ;
     RECT  54.353 37.872 54.749 39.864 ;
     RECT  54.709 34.128 54.965 34.152 ;
     RECT  54.709 26.304 55.573 28.584 ;
     RECT  51.304 29.808 55.573 29.832 ;
     RECT  54.709 36.336 55.573 36.888 ;
     RECT  54.749 37.872 55.573 39.768 ;
     RECT  55.573 26.304 55.609 29.832 ;
     RECT  55.573 36.336 55.765 39.768 ;
     RECT  51.304 48.768 56.077 48.792 ;
     RECT  55.609 26.304 56.365 30.072 ;
     RECT  51.304 24.96 56.408 24.984 ;
     RECT  56.365 26.304 56.408 30.12 ;
     RECT  54.709 31.728 56.408 32.328 ;
     RECT  55.532 34.32 56.408 35.304 ;
     RECT  55.765 36.336 56.408 39.912 ;
     RECT  51.545 45.408 56.408 45.432 ;
     RECT  56.077 48.384 56.408 48.792 ;
     RECT  51.304 50.064 56.408 50.088 ;
     RECT  53.749 51.408 56.408 51.432 ;
     RECT  56.408 2.148 56.512 71.292 ;
     RECT  56.512 2.418 56.704 71.022 ;
     RECT  56.704 36.336 56.801 40.056 ;
     RECT  56.704 34.176 56.873 34.2 ;
     RECT  56.704 26.4 57.913 28.584 ;
     RECT  56.801 36.432 57.949 40.056 ;
     RECT  57.913 26.4 58.021 29.016 ;
     RECT  56.704 30.048 58.021 30.216 ;
     RECT  56.704 24.96 58.057 24.984 ;
     RECT  57.949 36.432 58.213 40.104 ;
     RECT  56.704 45.408 58.213 45.432 ;
     RECT  58.165 41.472 58.259 41.496 ;
     RECT  58.213 45.12 58.3 45.432 ;
     RECT  58.021 26.4 58.313 30.216 ;
     RECT  58.057 24.96 58.417 25.08 ;
     RECT  58.313 26.4 58.417 29.304 ;
     RECT  58.213 36.432 58.417 40.44 ;
     RECT  56.704 50.064 58.669 50.088 ;
     RECT  56.704 51.408 58.669 51.432 ;
     RECT  58.417 24.48 58.693 29.304 ;
     RECT  58.3 45.408 58.705 45.432 ;
     RECT  56.704 48.768 58.705 48.792 ;
     RECT  58.693 23.808 58.739 29.304 ;
     RECT  58.739 23.808 58.741 23.832 ;
     RECT  58.705 33.648 58.741 33.672 ;
     RECT  58.705 45.408 58.741 45.576 ;
     RECT  58.741 45.408 58.745 46.536 ;
     RECT  58.741 33.648 58.849 33.912 ;
     RECT  58.739 24.96 58.853 29.304 ;
     RECT  58.849 33.648 58.889 34.344 ;
     RECT  58.741 30.624 58.925 30.648 ;
     RECT  56.704 31.728 58.988 32.328 ;
     RECT  58.988 31.728 59.075 32.76 ;
     RECT  58.853 24.96 59.141 28.584 ;
     RECT  58.705 47.952 59.245 48.792 ;
     RECT  58.889 33.888 59.281 34.344 ;
     RECT  58.849 35.328 59.281 35.352 ;
     RECT  58.745 45.552 59.281 46.536 ;
     RECT  58.669 50.064 59.429 51.432 ;
     RECT  59.281 45.552 59.845 46.68 ;
     RECT  58.417 36.432 59.897 41.016 ;
     RECT  59.245 47.856 60.257 48.792 ;
     RECT  59.429 51.408 60.257 51.432 ;
     RECT  59.141 26.16 60.284 28.584 ;
     RECT  58.741 23.664 60.365 23.832 ;
     RECT  59.429 50.064 60.397 50.424 ;
     RECT  60.257 48.768 60.421 48.792 ;
     RECT  60.365 23.808 60.437 23.832 ;
     RECT  59.845 45.552 60.469 46.776 ;
     RECT  59.141 24.96 60.541 25.08 ;
     RECT  60.284 26.16 60.541 28.872 ;
     RECT  59.075 31.728 60.541 31.848 ;
     RECT  59.281 33.888 60.545 35.352 ;
     RECT  60.421 48.768 60.613 49.032 ;
     RECT  60.397 50.064 60.613 51.336 ;
     RECT  60.613 48.768 60.617 51.336 ;
     RECT  59.897 36.432 60.649 37.944 ;
     RECT  60.649 35.904 60.733 37.944 ;
     RECT  60.545 33.888 60.865 34.728 ;
     RECT  60.865 33.84 60.973 34.728 ;
     RECT  60.973 33.696 61.009 34.728 ;
     RECT  60.001 30.336 61.052 30.36 ;
     RECT  60.541 31.344 61.052 31.848 ;
     RECT  60.733 36.144 61.477 37.944 ;
     RECT  59.897 39.072 61.477 41.016 ;
     RECT  61.477 36.144 61.549 41.016 ;
     RECT  61.009 33.6 61.573 34.728 ;
     RECT  60.541 24.96 61.58 28.872 ;
     RECT  61.549 36.144 61.621 41.448 ;
     RECT  60.469 45.552 61.657 47.64 ;
     RECT  60.617 48.768 61.657 51.24 ;
     RECT  61.573 33.6 61.669 35.112 ;
     RECT  61.58 24.816 61.808 28.872 ;
     RECT  61.052 30.336 61.808 31.848 ;
     RECT  61.669 33.552 61.808 35.112 ;
     RECT  61.621 36.144 61.808 41.496 ;
     RECT  61.261 42.72 61.808 42.744 ;
     RECT  61.657 45.552 61.808 51.24 ;
     RECT  61.808 2.148 61.912 71.292 ;
     RECT  61.912 2.418 62.104 71.022 ;
     RECT  62.104 26.016 62.129 29.112 ;
     RECT  62.129 26.064 62.273 29.112 ;
     RECT  62.104 30.336 62.273 31.752 ;
     RECT  62.104 36.48 62.849 38.28 ;
     RECT  62.104 50.016 62.921 51.24 ;
     RECT  62.273 26.256 62.993 29.112 ;
     RECT  62.849 36.48 63.029 37.992 ;
     RECT  62.273 30.576 63.065 31.752 ;
     RECT  62.104 41.376 63.097 41.448 ;
     RECT  63.097 41.376 63.133 41.496 ;
     RECT  62.104 45.552 63.317 48.84 ;
     RECT  63.133 41.376 63.425 41.592 ;
     RECT  62.993 26.256 63.443 29.064 ;
     RECT  62.104 39.552 63.457 39.768 ;
     RECT  63.425 41.376 63.457 41.496 ;
     RECT  63.457 39.552 63.74 41.496 ;
     RECT  62.104 33.024 63.785 35.352 ;
     RECT  63.443 26.256 63.889 27.48 ;
     RECT  63.317 45.6 63.889 48.84 ;
     RECT  62.921 50.064 63.889 51.24 ;
     RECT  63.889 45.6 63.893 51.24 ;
     RECT  63.889 25.632 63.961 27.48 ;
     RECT  63.961 25.296 64.141 27.48 ;
     RECT  63.065 30.576 64.145 31.656 ;
     RECT  64.141 25.104 64.357 27.48 ;
     RECT  63.029 36.576 64.357 37.992 ;
     RECT  63.74 39.264 64.357 41.496 ;
     RECT  63.443 28.56 64.397 29.064 ;
     RECT  63.893 46.752 64.397 51.24 ;
     RECT  64.397 46.752 64.403 50.856 ;
     RECT  63.785 33.312 64.405 35.352 ;
     RECT  64.357 36.576 64.405 41.496 ;
     RECT  64.145 30.576 64.429 31.512 ;
     RECT  64.403 47.28 64.433 50.856 ;
     RECT  64.405 33.312 64.451 41.496 ;
     RECT  64.451 35.952 64.492 41.496 ;
     RECT  64.429 29.76 64.541 31.512 ;
     RECT  63.893 45.6 64.541 45.624 ;
     RECT  64.433 47.28 64.541 50.712 ;
     RECT  64.541 29.76 64.577 31.272 ;
     RECT  64.451 33.312 64.649 34.728 ;
     RECT  64.649 33.312 64.789 33.912 ;
     RECT  64.789 32.496 64.829 33.912 ;
     RECT  64.577 29.76 64.937 30.6 ;
     RECT  64.357 24.528 64.981 27.48 ;
     RECT  64.541 47.28 65.009 49.032 ;
     RECT  64.492 36.48 65.045 41.496 ;
     RECT  64.541 50.688 65.225 50.712 ;
     RECT  64.981 23.904 65.333 27.48 ;
     RECT  65.045 36.48 65.441 40.584 ;
     RECT  65.441 39.792 65.469 40.584 ;
     RECT  65.333 24.528 65.477 27.384 ;
     RECT  64.897 46.128 65.581 46.152 ;
     RECT  65.477 26.208 65.585 27.384 ;
     RECT  64.937 30.576 65.585 30.6 ;
     RECT  65.441 36.48 65.585 38.664 ;
     RECT  65.585 26.208 65.621 27.048 ;
     RECT  64.397 28.56 65.621 28.584 ;
     RECT  64.829 32.496 65.621 33.336 ;
     RECT  65.581 45.552 65.621 46.152 ;
     RECT  65.621 26.304 65.657 27.048 ;
     RECT  65.621 32.736 65.657 33.336 ;
     RECT  65.009 47.424 65.765 49.032 ;
     RECT  65.469 39.792 65.801 39.816 ;
     RECT  65.765 49.008 65.945 49.032 ;
     RECT  65.765 47.424 66.013 47.64 ;
     RECT  65.657 26.736 66.017 27.048 ;
     RECT  65.977 29.088 66.125 29.112 ;
     RECT  65.621 45.552 66.301 45.576 ;
     RECT  65.477 24.528 66.445 24.552 ;
     RECT  66.301 45.216 66.661 45.576 ;
     RECT  66.661 44.688 66.697 45.576 ;
     RECT  66.013 46.608 66.697 47.64 ;
     RECT  66.697 44.688 66.769 47.64 ;
     RECT  66.769 44.688 66.913 48.264 ;
     RECT  66.445 24.528 66.985 25.32 ;
     RECT  65.869 33.6 67.057 33.72 ;
     RECT  66.985 24.528 67.208 25.752 ;
     RECT  66.017 26.736 67.208 26.76 ;
     RECT  67.057 33.6 67.208 34.68 ;
     RECT  65.585 36.816 67.208 37.944 ;
     RECT  66.913 44.688 67.208 48.504 ;
     RECT  67.208 2.148 67.312 71.292 ;
     RECT  67.312 2.418 67.504 71.022 ;
     RECT  67.504 25.536 67.853 25.56 ;
     RECT  67.504 45.216 67.889 48.408 ;
     RECT  67.889 45.216 68.105 48.312 ;
     RECT  67.504 30.816 68.141 33.096 ;
     RECT  68.105 45.696 68.177 48.312 ;
     RECT  68.177 46.32 68.321 48.312 ;
     RECT  68.321 46.32 68.393 48.264 ;
     RECT  68.393 46.752 68.429 48.12 ;
     RECT  68.429 46.8 68.465 46.92 ;
     RECT  68.429 47.952 68.501 48.12 ;
     RECT  67.504 27.744 68.533 28.44 ;
     RECT  67.504 36.816 68.533 37.032 ;
     RECT  68.465 46.8 68.609 46.824 ;
     RECT  68.501 47.952 68.717 47.976 ;
     RECT  67.504 39.984 68.749 40.008 ;
     RECT  68.497 25.728 68.785 25.752 ;
     RECT  67.504 34.512 68.861 34.92 ;
     RECT  68.785 25.728 68.893 26.52 ;
     RECT  68.533 27.744 68.893 28.488 ;
     RECT  68.893 25.68 69.037 26.52 ;
     RECT  68.893 27.648 69.037 28.488 ;
     RECT  68.533 36.48 69.149 37.032 ;
     RECT  68.749 39.504 69.181 40.008 ;
     RECT  68.141 30.912 69.581 33.096 ;
     RECT  69.149 36.816 69.581 37.032 ;
     RECT  69.181 38.64 69.581 40.008 ;
     RECT  69.581 30.912 69.613 31.128 ;
     RECT  69.613 30.864 69.689 31.128 ;
     RECT  69.581 39.792 70.013 40.008 ;
     RECT  69.037 25.68 70.081 28.488 ;
     RECT  69.581 32.304 70.081 33.096 ;
     RECT  69.581 36.864 70.085 37.032 ;
     RECT  69.865 21.984 70.265 22.008 ;
     RECT  70.085 37.008 70.265 37.032 ;
     RECT  69.581 38.64 70.265 38.664 ;
     RECT  70.013 39.984 70.369 40.008 ;
     RECT  70.369 39.984 70.373 40.488 ;
     RECT  70.369 42.624 70.481 42.648 ;
     RECT  69.689 30.864 70.632 30.936 ;
     RECT  70.081 32.304 70.693 33.432 ;
     RECT  68.861 34.512 70.693 34.536 ;
     RECT  70.585 23.376 70.801 23.4 ;
     RECT  70.081 25.2 70.801 28.488 ;
     RECT  70.297 29.52 70.801 29.544 ;
     RECT  70.632 30.768 70.801 30.936 ;
     RECT  70.801 25.2 70.837 29.544 ;
     RECT  70.801 30.768 70.837 30.984 ;
     RECT  70.693 32.304 70.837 34.536 ;
     RECT  70.729 47.856 70.837 47.88 ;
     RECT  70.405 48.912 70.837 48.936 ;
     RECT  70.837 30.768 70.913 34.536 ;
     RECT  70.801 23.376 71.017 24.072 ;
     RECT  70.837 47.856 71.017 48.936 ;
     RECT  70.693 49.968 71.017 49.992 ;
     RECT  71.017 23.184 71.053 24.072 ;
     RECT  70.837 25.2 71.053 29.64 ;
     RECT  71.053 23.184 71.125 29.64 ;
     RECT  71.017 47.856 71.197 49.992 ;
     RECT  70.513 37.44 71.233 37.848 ;
     RECT  71.125 46.416 71.233 46.44 ;
     RECT  71.197 47.856 71.233 50.28 ;
     RECT  70.913 34.32 71.269 34.536 ;
     RECT  71.125 22.992 71.305 29.64 ;
     RECT  70.913 30.768 71.305 33.096 ;
     RECT  71.233 45.936 71.305 50.28 ;
     RECT  71.233 36.912 71.665 38.184 ;
     RECT  71.269 34.32 71.701 34.728 ;
     RECT  71.305 45.936 71.701 50.472 ;
     RECT  71.701 34.32 71.737 34.92 ;
     RECT  71.665 36.912 71.737 38.856 ;
     RECT  70.373 40.176 71.737 40.488 ;
     RECT  71.701 45.84 71.737 51.144 ;
     RECT  71.737 34.32 71.773 35.592 ;
     RECT  71.737 36.624 71.773 40.488 ;
     RECT  71.737 42 71.773 42.024 ;
     RECT  71.737 45.552 71.773 51.144 ;
     RECT  71.773 34.32 71.845 40.488 ;
     RECT  71.305 22.992 72.025 33.096 ;
     RECT  71.845 34.32 72.025 40.584 ;
     RECT  72.025 22.992 72.061 40.584 ;
     RECT  72.061 22.992 72.133 40.68 ;
     RECT  71.773 41.904 72.133 42.024 ;
     RECT  71.773 45.264 72.313 51.144 ;
     RECT  72.133 22.992 72.389 42.744 ;
     RECT  72.389 22.992 73.404 42.12 ;
     RECT  72.313 45.264 73.404 51.336 ;
    LAYER M5 ;
     RECT  2.4 2.137 2.52 2.151 ;
     RECT  7.8 2.137 7.92 2.151 ;
     RECT  13.2 2.137 13.32 2.151 ;
     RECT  18.6 2.137 18.72 2.151 ;
     RECT  24 2.137 24.12 2.151 ;
     RECT  29.4 2.137 29.52 2.151 ;
     RECT  34.8 2.137 34.92 2.151 ;
     RECT  40.2 2.137 40.32 2.151 ;
     RECT  45.6 2.137 45.72 2.151 ;
     RECT  51 2.137 51.12 2.151 ;
     RECT  56.4 2.137 56.52 2.151 ;
     RECT  61.8 2.137 61.92 2.151 ;
     RECT  67.2 2.137 67.32 2.151 ;
     RECT  5.568 16.501 5.592 16.933 ;
     RECT  6.576 16.501 6.696 16.933 ;
     RECT  4.368 16.405 4.392 17.077 ;
     RECT  5.568 16.933 6.696 17.077 ;
     RECT  7.8 2.151 8.112 17.077 ;
     RECT  4.368 17.077 8.112 17.605 ;
     RECT  18.6 2.151 18.912 17.605 ;
     RECT  4.368 17.605 8.232 18.179 ;
     RECT  5.28 18.179 8.232 18.419 ;
     RECT  18.6 17.605 19.032 18.467 ;
     RECT  2.4 2.151 2.712 18.565 ;
     RECT  2.4 18.565 3.192 19.189 ;
     RECT  0.144 17.461 0.168 19.285 ;
     RECT  2.304 19.189 3.192 19.427 ;
     RECT  0.144 19.285 0.312 19.619 ;
     RECT  2.304 19.427 3 20.773 ;
     RECT  0.288 19.619 0.312 20.819 ;
     RECT  5.28 18.419 5.784 20.915 ;
     RECT  2.304 20.773 3.528 21.059 ;
     RECT  18.6 18.467 18.912 21.061 ;
     RECT  2.304 21.059 2.952 21.251 ;
     RECT  5.472 20.915 5.784 21.731 ;
     RECT  4.032 21.109 4.056 22.163 ;
     RECT  9.552 18.181 9.576 22.165 ;
     RECT  2.4 21.251 2.952 22.307 ;
     RECT  5.76 21.731 5.784 22.499 ;
     RECT  2.4 22.307 2.808 22.595 ;
     RECT  20.448 21.637 20.472 22.837 ;
     RECT  9.552 22.165 9.864 23.317 ;
     RECT  7.44 18.419 8.232 23.363 ;
     RECT  10.992 22.453 11.016 23.411 ;
     RECT  38.208 17.077 38.232 23.795 ;
     RECT  18.6 21.061 19.08 24.275 ;
     RECT  7.536 23.363 8.232 24.469 ;
     RECT  58.704 23.797 58.728 24.515 ;
     RECT  61.8 2.151 62.112 24.805 ;
     RECT  14.736 24.277 14.76 25.139 ;
     RECT  32.496 23.845 32.52 25.139 ;
     RECT  38.112 24.325 38.136 25.139 ;
     RECT  41.568 24.229 41.592 25.139 ;
     RECT  20.448 22.837 20.616 25.235 ;
     RECT  2.4 22.595 2.712 25.429 ;
     RECT  24 2.151 24.312 25.525 ;
     RECT  7.392 24.469 8.232 25.715 ;
     RECT  12 24.325 12.024 25.715 ;
     RECT  44.448 24.085 44.472 25.715 ;
     RECT  4.224 25.045 4.248 25.763 ;
     RECT  61.632 24.805 62.112 25.859 ;
     RECT  34.8 2.151 35.112 25.861 ;
     RECT  40.2 2.151 40.512 25.861 ;
     RECT  16.704 24.277 16.728 25.955 ;
     RECT  36.72 21.637 36.744 25.955 ;
     RECT  44.064 25.717 44.088 26.197 ;
     RECT  64.992 23.893 65.016 26.197 ;
     RECT  64.992 26.197 65.592 26.243 ;
     RECT  2.4 25.429 2.808 26.339 ;
     RECT  61.68 25.859 62.112 26.341 ;
     RECT  58.128 25.045 58.152 26.531 ;
     RECT  32.832 25.765 32.856 26.533 ;
     RECT  32.832 26.533 33.528 26.675 ;
     RECT  61.68 26.341 62.28 26.675 ;
     RECT  2.4 26.339 2.712 26.677 ;
     RECT  20.592 25.235 20.616 26.725 ;
     RECT  7.44 25.715 8.232 26.819 ;
     RECT  16.896 26.245 16.92 26.819 ;
     RECT  39.648 25.861 40.512 26.819 ;
     RECT  43.104 26.197 44.088 26.819 ;
     RECT  65.568 26.243 65.592 27.059 ;
     RECT  7.8 26.819 8.232 27.205 ;
     RECT  38.064 25.477 38.088 27.205 ;
     RECT  60.672 26.197 60.696 27.205 ;
     RECT  61.68 26.675 62.112 27.205 ;
     RECT  38.064 27.205 38.184 27.347 ;
     RECT  33.408 26.675 33.432 27.395 ;
     RECT  34.8 25.861 35.448 27.395 ;
     RECT  24 25.525 24.504 27.685 ;
     RECT  2.304 26.677 2.712 27.779 ;
     RECT  7.8 27.205 8.28 27.779 ;
     RECT  18.6 24.275 18.912 27.877 ;
     RECT  20.352 26.725 20.616 27.877 ;
     RECT  27.312 27.685 27.336 27.877 ;
     RECT  44.064 26.819 44.088 27.877 ;
     RECT  56.4 2.151 56.712 27.877 ;
     RECT  24 27.685 25.128 27.923 ;
     RECT  27.216 27.877 27.336 27.923 ;
     RECT  18.6 27.877 20.616 27.971 ;
     RECT  7.8 27.779 8.232 28.403 ;
     RECT  13.2 2.151 13.512 28.453 ;
     RECT  14.496 25.717 14.52 28.453 ;
     RECT  18.6 27.971 20.52 28.499 ;
     RECT  29.4 2.151 29.712 28.501 ;
     RECT  0.144 28.501 0.168 28.787 ;
     RECT  29.4 28.501 30.216 28.787 ;
     RECT  60.672 27.205 62.112 28.837 ;
     RECT  32.16 28.741 32.184 28.933 ;
     RECT  33.6 28.261 33.624 28.933 ;
     RECT  34.8 27.395 35.304 28.933 ;
     RECT  38.16 27.347 38.184 28.979 ;
     RECT  7.8 28.403 8.112 29.029 ;
     RECT  9.552 23.317 9.96 29.029 ;
     RECT  63.408 27.733 63.432 29.075 ;
     RECT  9.552 29.029 10.824 29.123 ;
     RECT  24 27.923 24.984 29.123 ;
     RECT  55.584 27.877 56.712 29.123 ;
     RECT  32.16 28.933 32.232 29.219 ;
     RECT  44.064 27.877 44.328 29.219 ;
     RECT  49.008 27.589 49.032 29.219 ;
     RECT  33.6 28.933 35.304 29.267 ;
     RECT  45.6 2.151 45.912 29.365 ;
     RECT  9.696 29.123 10.824 29.507 ;
     RECT  34.176 29.267 35.304 29.605 ;
     RECT  22.176 27.877 22.2 29.651 ;
     RECT  19.92 28.499 20.52 29.699 ;
     RECT  34.176 29.605 36.168 29.699 ;
     RECT  28.368 26.917 28.392 29.747 ;
     RECT  37.152 28.309 37.176 29.893 ;
     RECT  27.216 27.923 27.24 29.989 ;
     RECT  27.216 29.989 27.336 30.035 ;
     RECT  56.016 29.123 56.712 30.083 ;
     RECT  58.128 28.981 58.152 30.227 ;
     RECT  13.2 28.453 14.52 30.275 ;
     RECT  17.088 29.509 17.112 30.275 ;
     RECT  37.152 29.893 37.608 30.275 ;
     RECT  34.8 29.699 36.168 30.323 ;
     RECT  13.2 30.275 13.512 30.325 ;
     RECT  19.92 29.699 19.944 30.371 ;
     RECT  22.512 29.845 22.536 30.563 ;
     RECT  29.4 28.787 29.712 30.565 ;
     RECT  10.8 29.507 10.824 30.661 ;
     RECT  45.6 29.365 46.056 30.803 ;
     RECT  0.288 30.757 0.312 30.805 ;
     RECT  32.208 29.219 32.232 30.851 ;
     RECT  0.192 30.805 0.312 30.899 ;
     RECT  70.704 30.757 70.728 30.899 ;
     RECT  7.104 29.029 8.112 30.949 ;
     RECT  9.696 29.507 9.72 30.949 ;
     RECT  44.304 29.219 44.328 30.949 ;
     RECT  0.192 30.899 0.216 30.995 ;
     RECT  44.208 30.949 44.328 30.995 ;
     RECT  14.496 30.275 14.52 31.141 ;
     RECT  7.104 30.949 9.72 31.235 ;
     RECT  24 29.123 24.312 31.237 ;
     RECT  29.4 30.565 30.696 31.379 ;
     RECT  37.584 30.275 37.608 31.379 ;
     RECT  40.2 26.819 40.512 31.477 ;
     RECT  60.336 28.837 62.112 31.715 ;
     RECT  5.52 31.621 5.544 31.861 ;
     RECT  3.888 30.709 3.912 31.955 ;
     RECT  14.496 31.141 15.144 31.955 ;
     RECT  23.184 31.237 24.312 31.955 ;
     RECT  44.208 30.995 44.232 31.955 ;
     RECT  56.4 30.083 56.712 32.293 ;
     RECT  13.104 30.325 13.512 32.339 ;
     RECT  25.92 31.285 25.944 32.437 ;
     RECT  51 2.151 51.312 32.437 ;
     RECT  25.68 32.437 25.944 32.483 ;
     RECT  48.192 31.285 48.216 32.483 ;
     RECT  33.024 31.861 33.048 32.771 ;
     RECT  59.04 31.813 59.064 32.771 ;
     RECT  2.4 27.779 2.712 32.821 ;
     RECT  27.312 30.035 27.336 33.011 ;
     RECT  25.68 32.483 25.704 33.059 ;
     RECT  5.52 31.861 6.024 33.061 ;
     RECT  4.992 33.061 6.024 33.107 ;
     RECT  4.992 33.107 5.016 33.203 ;
     RECT  10.8 30.661 11.208 33.299 ;
     RECT  61.8 31.715 62.112 33.541 ;
     RECT  14.496 31.955 14.52 33.589 ;
     RECT  34.8 30.323 35.304 33.589 ;
     RECT  36.336 32.437 36.36 33.589 ;
     RECT  43.056 31.861 43.08 34.309 ;
     RECT  6 33.107 6.024 34.355 ;
     RECT  14.496 33.589 14.664 34.355 ;
     RECT  43.056 34.309 43.224 34.355 ;
     RECT  2.304 32.821 2.712 34.403 ;
     RECT  61.68 33.541 62.112 34.405 ;
     RECT  60.336 31.715 60.36 34.693 ;
     RECT  61.584 34.405 62.112 34.693 ;
     RECT  63.984 33.541 64.008 34.739 ;
     RECT  7.104 31.235 8.112 34.741 ;
     RECT  34.8 33.589 36.36 34.835 ;
     RECT  25.824 34.741 25.848 35.029 ;
     RECT  25.728 35.029 25.848 35.075 ;
     RECT  60.336 34.693 62.112 35.123 ;
     RECT  40.2 31.477 41.064 35.269 ;
     RECT  40.2 35.269 41.544 35.315 ;
     RECT  13.2 32.339 13.512 35.317 ;
     RECT  14.496 34.355 14.52 35.317 ;
     RECT  43.2 34.355 43.224 35.317 ;
     RECT  53.28 33.541 53.304 35.413 ;
     RECT  7.104 34.741 8.52 35.507 ;
     RECT  50.016 32.437 51.312 35.699 ;
     RECT  7.104 35.507 8.112 35.845 ;
     RECT  12.096 35.269 12.12 35.891 ;
     RECT  27.888 34.741 27.912 35.891 ;
     RECT  32.4 32.869 32.424 35.939 ;
     RECT  60.336 35.123 60.696 35.939 ;
     RECT  64.416 35.317 64.44 35.987 ;
     RECT  38.208 34.165 38.232 36.131 ;
     RECT  61.68 35.123 62.112 36.133 ;
     RECT  34.8 34.835 35.736 36.275 ;
     RECT  50.736 35.699 51.312 36.371 ;
     RECT  60.336 35.939 60.36 36.421 ;
     RECT  59.856 36.421 60.36 36.467 ;
     RECT  25.728 35.075 25.752 36.515 ;
     RECT  41.52 35.315 41.544 36.515 ;
     RECT  52.992 35.413 53.304 36.659 ;
     RECT  13.2 35.317 14.52 36.853 ;
     RECT  29.4 31.379 29.712 36.853 ;
     RECT  34.8 36.275 35.352 36.899 ;
     RECT  55.584 32.293 56.712 36.947 ;
     RECT  0.144 36.805 0.168 36.995 ;
     RECT  13.2 36.853 14.568 36.997 ;
     RECT  6.576 35.845 8.112 37.043 ;
     RECT  29.4 36.853 29.832 37.043 ;
     RECT  43.2 35.317 43.752 37.043 ;
     RECT  61.392 36.133 62.112 37.043 ;
     RECT  4.608 35.701 4.632 37.091 ;
     RECT  7.104 37.043 8.112 37.091 ;
     RECT  12.816 36.997 14.568 37.139 ;
     RECT  34.8 36.899 35.112 37.477 ;
     RECT  59.856 36.467 59.88 37.667 ;
     RECT  18.6 28.499 18.912 38.101 ;
     RECT  26.928 37.573 26.952 38.195 ;
     RECT  15.84 35.845 15.864 38.485 ;
     RECT  55.776 36.947 56.712 38.533 ;
     RECT  2.4 34.403 2.712 38.581 ;
     RECT  52.992 36.659 53.016 38.675 ;
     RECT  64.368 37.477 64.392 38.677 ;
     RECT  65.376 37.285 65.4 38.677 ;
     RECT  7.8 37.091 8.112 38.725 ;
     RECT  24 31.955 24.312 38.725 ;
     RECT  34.32 37.477 35.112 38.819 ;
     RECT  64.368 38.677 65.4 38.819 ;
     RECT  7.44 38.725 8.112 39.061 ;
     RECT  34.8 38.819 35.112 39.205 ;
     RECT  2.304 38.581 2.712 39.251 ;
     RECT  18.6 38.101 19.416 39.301 ;
     RECT  18.336 39.301 19.416 39.347 ;
     RECT  64.992 38.819 65.4 39.395 ;
     RECT  15.84 38.485 16.056 39.491 ;
     RECT  61.68 37.043 62.112 39.587 ;
     RECT  9.696 31.235 9.72 39.637 ;
     RECT  10.8 33.299 10.824 39.637 ;
     RECT  16.032 39.491 16.056 39.685 ;
     RECT  16.032 39.685 16.296 39.781 ;
     RECT  55.776 38.533 57.288 39.923 ;
     RECT  63.792 39.253 63.816 39.923 ;
     RECT  24 38.725 24.936 40.355 ;
     RECT  18.336 39.347 19.368 40.547 ;
     RECT  65.376 39.395 65.4 40.595 ;
     RECT  12.816 37.139 13.512 40.739 ;
     RECT  43.344 37.043 43.752 40.787 ;
     RECT  7.104 39.061 8.112 40.835 ;
     RECT  18.6 40.547 19.368 40.835 ;
     RECT  2.4 39.251 2.712 40.885 ;
     RECT  38.256 37.573 38.28 41.075 ;
     RECT  12 40.741 12.024 41.651 ;
     RECT  16.032 39.781 16.776 41.651 ;
     RECT  7.44 40.835 8.112 41.795 ;
     RECT  7.8 41.795 8.112 42.133 ;
     RECT  9.696 39.637 10.824 42.227 ;
     RECT  2.4 40.885 2.808 42.515 ;
     RECT  61.8 39.587 62.112 42.709 ;
     RECT  9.696 42.227 9.72 43.283 ;
     RECT  16.032 41.651 16.056 43.379 ;
     RECT  7.8 42.133 8.52 43.571 ;
     RECT  43.344 40.787 43.608 43.573 ;
     RECT  0.144 43.573 0.168 43.859 ;
     RECT  10.752 42.227 10.824 43.955 ;
     RECT  10.8 43.955 10.824 44.437 ;
     RECT  7.8 43.571 8.112 44.965 ;
     RECT  10.8 44.437 11.784 44.965 ;
     RECT  67.2 2.151 67.512 44.965 ;
     RECT  10.272 44.965 11.976 45.059 ;
     RECT  36.72 41.557 36.744 45.155 ;
     RECT  58.224 40.405 58.248 45.155 ;
     RECT  50.88 36.371 51.312 45.203 ;
     RECT  43.344 43.573 43.896 45.299 ;
     RECT  11.856 45.059 11.976 45.541 ;
     RECT  13.2 40.739 13.512 46.069 ;
     RECT  14.544 37.139 14.568 46.069 ;
     RECT  7.44 44.965 8.112 46.117 ;
     RECT  43.344 45.299 43.416 46.211 ;
     RECT  42.144 37.573 42.168 46.259 ;
     RECT  10.272 45.059 10.824 46.499 ;
     RECT  61.296 42.709 62.112 46.549 ;
     RECT  2.4 42.515 2.712 46.597 ;
     RECT  2.4 46.597 2.808 46.645 ;
     RECT  0.144 46.501 0.168 46.691 ;
     RECT  40.2 35.315 40.512 46.693 ;
     RECT  13.2 46.069 14.568 46.787 ;
     RECT  59.856 46.645 59.88 46.787 ;
     RECT  64.368 45.589 64.392 46.787 ;
     RECT  67.104 44.965 67.512 46.789 ;
     RECT  6.864 46.117 8.112 46.835 ;
     RECT  34.8 39.205 35.208 47.027 ;
     RECT  10.32 46.499 10.824 47.075 ;
     RECT  33.12 37.573 33.144 47.125 ;
     RECT  43.344 46.211 43.368 47.269 ;
     RECT  4.992 45.541 5.016 47.315 ;
     RECT  43.344 47.269 43.464 47.315 ;
     RECT  11.856 45.541 12.024 47.363 ;
     RECT  61.008 46.549 62.112 47.363 ;
     RECT  10.56 47.075 10.824 47.603 ;
     RECT  40.2 46.693 41.304 47.651 ;
     RECT  7.68 46.835 8.112 47.845 ;
     RECT  13.2 46.787 13.512 47.845 ;
     RECT  14.544 46.787 14.568 47.845 ;
     RECT  66.96 46.789 67.512 47.939 ;
     RECT  2.304 46.645 2.808 48.035 ;
     RECT  32.496 47.125 33.144 48.371 ;
     RECT  7.68 47.845 8.28 48.419 ;
     RECT  16.272 47.845 16.296 48.467 ;
     RECT  6.576 47.173 6.6 48.515 ;
     RECT  67.104 47.939 67.512 48.515 ;
     RECT  2.304 48.035 2.712 48.707 ;
     RECT  18.6 40.835 18.912 48.949 ;
     RECT  38.208 45.541 38.232 48.995 ;
     RECT  60.576 47.605 60.6 48.997 ;
     RECT  43.44 47.315 43.464 49.043 ;
     RECT  7.8 48.419 8.28 49.045 ;
     RECT  31.248 48.325 31.272 49.187 ;
     RECT  13.2 47.845 14.568 49.619 ;
     RECT  12 47.363 12.024 49.957 ;
     RECT  13.2 49.619 14.28 49.957 ;
     RECT  12 49.957 14.28 50.003 ;
     RECT  63.168 46.117 63.192 50.195 ;
     RECT  18.6 48.949 19.176 50.389 ;
     RECT  0.144 49.237 0.168 50.483 ;
     RECT  7.8 49.045 8.664 50.771 ;
     RECT  12.24 50.003 14.28 50.867 ;
     RECT  64.176 49.525 64.2 50.867 ;
     RECT  16.128 50.101 16.152 50.965 ;
     RECT  60.432 48.997 60.6 51.347 ;
     RECT  18.6 50.389 19.464 52.357 ;
     RECT  16.128 50.965 16.584 53.075 ;
     RECT  16.128 53.075 16.152 53.267 ;
     RECT  22.512 50.389 22.536 54.323 ;
     RECT  53.76 51.397 53.784 55.955 ;
     RECT  18.6 52.357 19.56 58.739 ;
     RECT  12.24 50.867 13.512 59.603 ;
     RECT  46.944 56.005 46.968 59.891 ;
     RECT  40.2 47.651 40.512 60.325 ;
     RECT  40.2 60.325 41.016 64.451 ;
     RECT  34.8 47.027 35.112 64.645 ;
     RECT  34.224 64.645 35.112 69.011 ;
     RECT  33.12 48.371 33.144 69.059 ;
     RECT  22.464 54.661 22.488 70.019 ;
     RECT  10.8 47.603 10.824 70.595 ;
     RECT  26.256 69.157 26.28 70.645 ;
     RECT  2.4 48.707 2.712 71.289 ;
     RECT  7.8 50.771 8.112 71.289 ;
     RECT  13.2 59.603 13.512 71.289 ;
     RECT  18.6 58.739 18.912 71.289 ;
     RECT  24 40.355 24.312 71.289 ;
     RECT  29.4 37.043 29.712 71.289 ;
     RECT  34.8 69.011 35.112 71.289 ;
     RECT  40.2 64.451 40.512 71.289 ;
     RECT  45.6 30.803 45.912 71.289 ;
     RECT  51 45.203 51.312 71.289 ;
     RECT  56.4 39.923 56.712 71.289 ;
     RECT  61.8 47.363 62.112 71.289 ;
     RECT  67.2 48.515 67.512 71.289 ;
     RECT  2.4 71.289 2.52 71.303 ;
     RECT  7.8 71.289 7.92 71.303 ;
     RECT  13.2 71.289 13.32 71.303 ;
     RECT  18.6 71.289 18.72 71.303 ;
     RECT  24 71.289 24.12 71.303 ;
     RECT  29.4 71.289 29.52 71.303 ;
     RECT  34.8 71.289 34.92 71.303 ;
     RECT  40.2 71.289 40.32 71.303 ;
     RECT  45.6 71.289 45.72 71.303 ;
     RECT  51 71.289 51.12 71.303 ;
     RECT  56.4 71.289 56.52 71.303 ;
     RECT  61.8 71.289 61.92 71.303 ;
     RECT  67.2 71.289 67.32 71.303 ;
     RECT  26.256 70.645 26.424 72.373 ;
     RECT  26.256 72.373 26.472 73.424 ;
     RECT  4.392 16.501 5.568 17.077 ;
     RECT  5.592 16.501 6.576 16.933 ;
     RECT  6.696 16.501 7.8 17.077 ;
     RECT  8.232 18.181 9.552 27.205 ;
     RECT  3 19.427 3.192 20.773 ;
     RECT  5.28 20.915 5.472 21.109 ;
     RECT  2.952 21.059 3.528 21.109 ;
     RECT  2.952 21.109 4.032 22.163 ;
     RECT  4.056 21.109 5.472 21.731 ;
     RECT  19.08 21.637 20.448 24.275 ;
     RECT  36.744 21.637 38.208 23.795 ;
     RECT  9.864 22.453 10.992 23.317 ;
     RECT  9.96 23.317 10.992 23.411 ;
     RECT  7.44 23.363 7.536 24.469 ;
     RECT  36.744 23.795 38.136 24.325 ;
     RECT  44.472 24.085 45.6 25.715 ;
     RECT  40.512 24.229 41.568 25.139 ;
     RECT  13.512 24.277 14.736 25.139 ;
     RECT  12.024 24.325 13.2 25.715 ;
     RECT  36.744 24.325 38.112 25.139 ;
     RECT  2.712 25.045 4.224 25.429 ;
     RECT  56.712 25.045 58.128 26.531 ;
     RECT  13.512 25.139 14.52 25.717 ;
     RECT  36.744 25.139 38.088 25.477 ;
     RECT  20.448 25.235 20.592 26.725 ;
     RECT  2.808 25.429 4.224 25.763 ;
     RECT  36.744 25.477 38.064 25.955 ;
     RECT  44.448 25.715 45.6 25.717 ;
     RECT  13.512 25.717 14.496 28.453 ;
     RECT  44.088 25.717 45.6 27.877 ;
     RECT  61.632 25.859 61.68 26.197 ;
     RECT  35.448 25.861 36.72 25.955 ;
     RECT  60.696 26.197 61.68 27.205 ;
     RECT  33.528 26.533 34.8 26.675 ;
     RECT  33.432 26.675 34.8 27.395 ;
     RECT  62.112 26.675 62.28 27.733 ;
     RECT  18.912 26.725 20.352 27.877 ;
     RECT  28.392 26.917 29.4 29.747 ;
     RECT  8.28 27.205 9.552 27.779 ;
     RECT  38.064 27.347 38.16 28.309 ;
     RECT  33.408 27.395 34.8 28.261 ;
     RECT  27.336 27.685 28.368 27.923 ;
     RECT  62.112 27.733 63.408 29.075 ;
     RECT  8.232 27.779 9.552 28.403 ;
     RECT  44.328 27.877 45.6 30.995 ;
     RECT  27.24 27.923 28.368 29.747 ;
     RECT  33.408 28.261 33.6 28.741 ;
     RECT  33.624 28.261 34.8 28.933 ;
     RECT  37.176 28.309 38.16 28.979 ;
     RECT  8.112 28.403 9.552 29.123 ;
     RECT  18.912 28.499 19.92 30.371 ;
     RECT  32.184 28.741 33.6 28.933 ;
     RECT  32.232 28.933 33.6 29.267 ;
     RECT  37.176 28.979 37.608 29.893 ;
     RECT  56.712 28.981 58.128 30.227 ;
     RECT  32.16 29.219 32.208 30.565 ;
     RECT  9.72 29.507 10.8 39.637 ;
     RECT  17.112 29.509 18.6 30.275 ;
     RECT  36.168 29.605 37.152 30.275 ;
     RECT  27.24 29.747 27.336 29.989 ;
     RECT  22.536 29.845 24 30.563 ;
     RECT  27.216 30.035 27.312 31.285 ;
     RECT  13.512 30.275 14.496 35.317 ;
     RECT  36.168 30.275 37.584 30.323 ;
     RECT  23.184 30.563 24 31.237 ;
     RECT  30.696 30.565 32.208 30.851 ;
     RECT  2.712 30.709 3.888 31.955 ;
     RECT  44.232 30.995 45.6 31.955 ;
     RECT  25.944 31.285 27.312 32.483 ;
     RECT  60.36 31.715 61.8 33.541 ;
     RECT  59.064 31.813 60.336 32.771 ;
     RECT  6.024 31.861 7.104 34.355 ;
     RECT  43.08 31.861 44.208 31.955 ;
     RECT  24.312 32.437 25.68 33.059 ;
     RECT  35.304 32.437 36.336 33.589 ;
     RECT  5.016 33.107 6 33.203 ;
     RECT  60.36 33.541 61.68 34.405 ;
     RECT  6.576 34.355 7.104 35.845 ;
     RECT  14.52 34.355 14.664 35.845 ;
     RECT  60.36 34.405 61.584 34.693 ;
     RECT  8.52 34.741 9.696 35.507 ;
     RECT  24.312 34.741 25.824 35.029 ;
     RECT  27.912 34.741 29.4 35.891 ;
     RECT  24.312 35.029 25.728 36.515 ;
     RECT  60.696 35.123 61.68 35.939 ;
     RECT  10.824 35.269 12.096 35.891 ;
     RECT  12.12 35.269 13.2 35.891 ;
     RECT  40.512 35.315 41.52 36.515 ;
     RECT  14.52 35.845 15.84 36.853 ;
     RECT  12.816 35.891 13.2 36.997 ;
     RECT  60.36 35.939 61.68 36.133 ;
     RECT  64.416 35.987 64.44 37.285 ;
     RECT  60.36 36.133 61.392 36.467 ;
     RECT  59.88 36.467 61.392 37.043 ;
     RECT  14.568 36.853 15.84 39.491 ;
     RECT  43.2 37.043 43.344 37.573 ;
     RECT  13.512 37.139 14.544 46.069 ;
     RECT  64.416 37.285 65.376 37.477 ;
     RECT  64.392 37.477 65.376 38.677 ;
     RECT  33.144 37.573 34.32 38.819 ;
     RECT  42.168 37.573 43.344 46.259 ;
     RECT  64.368 38.819 64.992 39.253 ;
     RECT  63.816 39.253 64.992 39.395 ;
     RECT  14.568 39.491 16.032 43.379 ;
     RECT  56.712 39.923 57.288 40.405 ;
     RECT  56.712 40.405 58.224 45.155 ;
     RECT  12.816 40.739 13.2 40.741 ;
     RECT  10.824 40.741 12 41.651 ;
     RECT  12.024 40.741 13.2 41.651 ;
     RECT  35.208 41.557 36.72 45.155 ;
     RECT  8.52 42.133 9.696 43.283 ;
     RECT  9.72 42.227 10.752 43.283 ;
     RECT  10.752 43.955 10.8 44.965 ;
     RECT  11.784 44.437 13.2 44.965 ;
     RECT  11.976 44.965 13.2 45.541 ;
     RECT  10.824 45.059 11.856 47.363 ;
     RECT  12.024 45.541 13.2 49.957 ;
     RECT  62.112 46.117 63.168 50.195 ;
     RECT  63.192 46.117 64.368 46.787 ;
     RECT  43.368 46.211 43.416 47.269 ;
     RECT  59.88 46.645 61.008 46.787 ;
     RECT  13.512 46.787 14.544 47.845 ;
     RECT  60.576 46.787 61.008 47.363 ;
     RECT  6.864 46.835 7.68 47.173 ;
     RECT  6.6 47.173 7.68 48.419 ;
     RECT  10.824 47.363 12 50.003 ;
     RECT  60.576 47.363 61.8 47.605 ;
     RECT  60.6 47.605 61.8 51.347 ;
     RECT  31.272 48.325 32.496 48.371 ;
     RECT  6.6 48.419 7.8 48.515 ;
     RECT  63.192 49.525 64.176 50.195 ;
     RECT  10.824 50.003 12.24 59.603 ;
     RECT  22.536 50.389 24 54.323 ;
     RECT  22.512 54.323 24 54.661 ;
     RECT  22.488 54.661 24 70.019 ;
     RECT  45.912 56.005 46.944 59.891 ;
     RECT  33.144 64.645 34.224 69.011 ;
  END
END ot_smh_own_eg
END LIBRARY
